VERSION 5.8 ;
BUSBITCHARS "[]" ;
DIVIDERCHAR "/" ;
UNITS
    DATABASE MICRONS 1000 ;
END UNITS

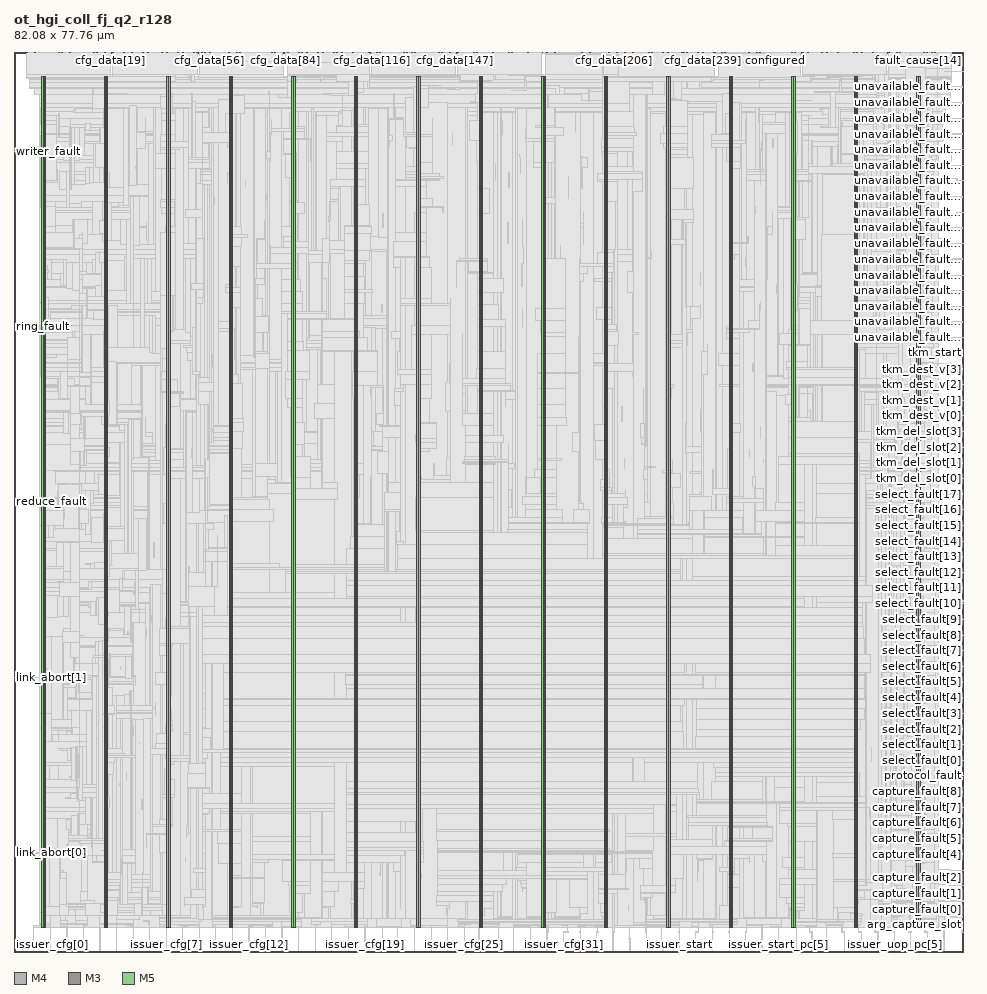
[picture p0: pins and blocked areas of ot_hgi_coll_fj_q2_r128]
MACRO ot_hgi_coll_fj_q2_r128
  FOREIGN ot_hgi_coll_fj_q2_r128 0 0 ;
  CLASS BLOCK ;
  SIZE 82.08 BY 77.76 ;
  PIN arg_capture_slot
    DIRECTION INPUT ;
    USE SIGNAL ;
    PORT
      LAYER M4 ;
        RECT  81.996 1.68 82.08 1.704 ;
    END
  END arg_capture_slot
  PIN capture_fault[0]
    DIRECTION INPUT ;
    USE SIGNAL ;
    PORT
      LAYER M4 ;
        RECT  81.996 3.024 82.08 3.048 ;
    END
  END capture_fault[0]
  PIN capture_fault[1]
    DIRECTION INPUT ;
    USE SIGNAL ;
    PORT
      LAYER M4 ;
        RECT  81.996 4.368 82.08 4.392 ;
    END
  END capture_fault[1]
  PIN capture_fault[2]
    DIRECTION INPUT ;
    USE SIGNAL ;
    PORT
      LAYER M4 ;
        RECT  81.996 5.712 82.08 5.736 ;
    END
  END capture_fault[2]
  PIN capture_fault[3]
    DIRECTION INPUT ;
    USE SIGNAL ;
    PORT
      LAYER M4 ;
        RECT  81.996 7.056 82.08 7.08 ;
    END
  END capture_fault[3]
  PIN capture_fault[4]
    DIRECTION INPUT ;
    USE SIGNAL ;
    PORT
      LAYER M4 ;
        RECT  81.996 8.448 82.08 8.472 ;
    END
  END capture_fault[4]
  PIN capture_fault[5]
    DIRECTION INPUT ;
    USE SIGNAL ;
    PORT
      LAYER M4 ;
        RECT  81.996 9.792 82.08 9.816 ;
    END
  END capture_fault[5]
  PIN capture_fault[6]
    DIRECTION INPUT ;
    USE SIGNAL ;
    PORT
      LAYER M4 ;
        RECT  81.996 11.136 82.08 11.16 ;
    END
  END capture_fault[6]
  PIN capture_fault[7]
    DIRECTION INPUT ;
    USE SIGNAL ;
    PORT
      LAYER M4 ;
        RECT  81.996 12.48 82.08 12.504 ;
    END
  END capture_fault[7]
  PIN capture_fault[8]
    DIRECTION INPUT ;
    USE SIGNAL ;
    PORT
      LAYER M4 ;
        RECT  81.996 13.824 82.08 13.848 ;
    END
  END capture_fault[8]
  PIN cfg_addr[0]
    DIRECTION INPUT ;
    USE SIGNAL ;
    PORT
      LAYER M3 ;
        RECT  1.116 77.722 1.134 77.76 ;
    END
  END cfg_addr[0]
  PIN cfg_addr[10]
    DIRECTION INPUT ;
    USE SIGNAL ;
    PORT
      LAYER M3 ;
        RECT  3.42 77.722 3.438 77.76 ;
    END
  END cfg_addr[10]
  PIN cfg_addr[11]
    DIRECTION INPUT ;
    USE SIGNAL ;
    PORT
      LAYER M3 ;
        RECT  3.672 77.722 3.69 77.76 ;
    END
  END cfg_addr[11]
  PIN cfg_addr[1]
    DIRECTION INPUT ;
    USE SIGNAL ;
    PORT
      LAYER M3 ;
        RECT  1.332 77.722 1.35 77.76 ;
    END
  END cfg_addr[1]
  PIN cfg_addr[2]
    DIRECTION INPUT ;
    USE SIGNAL ;
    PORT
      LAYER M3 ;
        RECT  1.584 77.722 1.602 77.76 ;
    END
  END cfg_addr[2]
  PIN cfg_addr[3]
    DIRECTION INPUT ;
    USE SIGNAL ;
    PORT
      LAYER M3 ;
        RECT  1.8 77.722 1.818 77.76 ;
    END
  END cfg_addr[3]
  PIN cfg_addr[4]
    DIRECTION INPUT ;
    USE SIGNAL ;
    PORT
      LAYER M3 ;
        RECT  2.052 77.722 2.07 77.76 ;
    END
  END cfg_addr[4]
  PIN cfg_addr[5]
    DIRECTION INPUT ;
    USE SIGNAL ;
    PORT
      LAYER M3 ;
        RECT  2.268 77.722 2.286 77.76 ;
    END
  END cfg_addr[5]
  PIN cfg_addr[6]
    DIRECTION INPUT ;
    USE SIGNAL ;
    PORT
      LAYER M3 ;
        RECT  2.52 77.722 2.538 77.76 ;
    END
  END cfg_addr[6]
  PIN cfg_addr[7]
    DIRECTION INPUT ;
    USE SIGNAL ;
    PORT
      LAYER M3 ;
        RECT  2.736 77.722 2.754 77.76 ;
    END
  END cfg_addr[7]
  PIN cfg_addr[8]
    DIRECTION INPUT ;
    USE SIGNAL ;
    PORT
      LAYER M3 ;
        RECT  2.988 77.722 3.006 77.76 ;
    END
  END cfg_addr[8]
  PIN cfg_addr[9]
    DIRECTION INPUT ;
    USE SIGNAL ;
    PORT
      LAYER M3 ;
        RECT  3.204 77.722 3.222 77.76 ;
    END
  END cfg_addr[9]
  PIN cfg_data[0]
    DIRECTION INPUT ;
    USE SIGNAL ;
    PORT
      LAYER M3 ;
        RECT  3.888 77.722 3.906 77.76 ;
    END
  END cfg_data[0]
  PIN cfg_data[100]
    DIRECTION INPUT ;
    USE SIGNAL ;
    PORT
      LAYER M5 ;
        RECT  27.168 77.676 27.192 77.76 ;
    END
  END cfg_data[100]
  PIN cfg_data[101]
    DIRECTION INPUT ;
    USE SIGNAL ;
    PORT
      LAYER M5 ;
        RECT  27.408 77.676 27.432 77.76 ;
    END
  END cfg_data[101]
  PIN cfg_data[102]
    DIRECTION INPUT ;
    USE SIGNAL ;
    PORT
      LAYER M5 ;
        RECT  27.648 77.676 27.672 77.76 ;
    END
  END cfg_data[102]
  PIN cfg_data[103]
    DIRECTION INPUT ;
    USE SIGNAL ;
    PORT
      LAYER M5 ;
        RECT  27.888 77.676 27.912 77.76 ;
    END
  END cfg_data[103]
  PIN cfg_data[104]
    DIRECTION INPUT ;
    USE SIGNAL ;
    PORT
      LAYER M5 ;
        RECT  28.128 77.676 28.152 77.76 ;
    END
  END cfg_data[104]
  PIN cfg_data[105]
    DIRECTION INPUT ;
    USE SIGNAL ;
    PORT
      LAYER M5 ;
        RECT  28.32 77.676 28.344 77.76 ;
    END
  END cfg_data[105]
  PIN cfg_data[106]
    DIRECTION INPUT ;
    USE SIGNAL ;
    PORT
      LAYER M5 ;
        RECT  28.56 77.676 28.584 77.76 ;
    END
  END cfg_data[106]
  PIN cfg_data[107]
    DIRECTION INPUT ;
    USE SIGNAL ;
    PORT
      LAYER M5 ;
        RECT  28.8 77.676 28.824 77.76 ;
    END
  END cfg_data[107]
  PIN cfg_data[108]
    DIRECTION INPUT ;
    USE SIGNAL ;
    PORT
      LAYER M5 ;
        RECT  29.04 77.676 29.064 77.76 ;
    END
  END cfg_data[108]
  PIN cfg_data[109]
    DIRECTION INPUT ;
    USE SIGNAL ;
    PORT
      LAYER M5 ;
        RECT  29.28 77.676 29.304 77.76 ;
    END
  END cfg_data[109]
  PIN cfg_data[10]
    DIRECTION INPUT ;
    USE SIGNAL ;
    PORT
      LAYER M3 ;
        RECT  6.228 77.722 6.246 77.76 ;
    END
  END cfg_data[10]
  PIN cfg_data[110]
    DIRECTION INPUT ;
    USE SIGNAL ;
    PORT
      LAYER M5 ;
        RECT  29.52 77.676 29.544 77.76 ;
    END
  END cfg_data[110]
  PIN cfg_data[111]
    DIRECTION INPUT ;
    USE SIGNAL ;
    PORT
      LAYER M5 ;
        RECT  29.76 77.676 29.784 77.76 ;
    END
  END cfg_data[111]
  PIN cfg_data[112]
    DIRECTION INPUT ;
    USE SIGNAL ;
    PORT
      LAYER M5 ;
        RECT  29.952 77.676 29.976 77.76 ;
    END
  END cfg_data[112]
  PIN cfg_data[113]
    DIRECTION INPUT ;
    USE SIGNAL ;
    PORT
      LAYER M5 ;
        RECT  30.192 77.676 30.216 77.76 ;
    END
  END cfg_data[113]
  PIN cfg_data[114]
    DIRECTION INPUT ;
    USE SIGNAL ;
    PORT
      LAYER M5 ;
        RECT  30.432 77.676 30.456 77.76 ;
    END
  END cfg_data[114]
  PIN cfg_data[115]
    DIRECTION INPUT ;
    USE SIGNAL ;
    PORT
      LAYER M5 ;
        RECT  30.672 77.676 30.696 77.76 ;
    END
  END cfg_data[115]
  PIN cfg_data[116]
    DIRECTION INPUT ;
    USE SIGNAL ;
    PORT
      LAYER M3 ;
        RECT  30.888 77.722 30.906 77.76 ;
    END
  END cfg_data[116]
  PIN cfg_data[117]
    DIRECTION INPUT ;
    USE SIGNAL ;
    PORT
      LAYER M3 ;
        RECT  31.14 77.722 31.158 77.76 ;
    END
  END cfg_data[117]
  PIN cfg_data[118]
    DIRECTION INPUT ;
    USE SIGNAL ;
    PORT
      LAYER M3 ;
        RECT  31.356 77.722 31.374 77.76 ;
    END
  END cfg_data[118]
  PIN cfg_data[119]
    DIRECTION INPUT ;
    USE SIGNAL ;
    PORT
      LAYER M3 ;
        RECT  31.608 77.722 31.626 77.76 ;
    END
  END cfg_data[119]
  PIN cfg_data[11]
    DIRECTION INPUT ;
    USE SIGNAL ;
    PORT
      LAYER M3 ;
        RECT  6.48 77.722 6.498 77.76 ;
    END
  END cfg_data[11]
  PIN cfg_data[120]
    DIRECTION INPUT ;
    USE SIGNAL ;
    PORT
      LAYER M3 ;
        RECT  31.824 77.722 31.842 77.76 ;
    END
  END cfg_data[120]
  PIN cfg_data[121]
    DIRECTION INPUT ;
    USE SIGNAL ;
    PORT
      LAYER M3 ;
        RECT  32.076 77.722 32.094 77.76 ;
    END
  END cfg_data[121]
  PIN cfg_data[122]
    DIRECTION INPUT ;
    USE SIGNAL ;
    PORT
      LAYER M3 ;
        RECT  32.292 77.722 32.31 77.76 ;
    END
  END cfg_data[122]
  PIN cfg_data[123]
    DIRECTION INPUT ;
    USE SIGNAL ;
    PORT
      LAYER M3 ;
        RECT  32.544 77.722 32.562 77.76 ;
    END
  END cfg_data[123]
  PIN cfg_data[124]
    DIRECTION INPUT ;
    USE SIGNAL ;
    PORT
      LAYER M3 ;
        RECT  32.76 77.722 32.778 77.76 ;
    END
  END cfg_data[124]
  PIN cfg_data[125]
    DIRECTION INPUT ;
    USE SIGNAL ;
    PORT
      LAYER M3 ;
        RECT  33.012 77.722 33.03 77.76 ;
    END
  END cfg_data[125]
  PIN cfg_data[126]
    DIRECTION INPUT ;
    USE SIGNAL ;
    PORT
      LAYER M3 ;
        RECT  33.228 77.722 33.246 77.76 ;
    END
  END cfg_data[126]
  PIN cfg_data[127]
    DIRECTION INPUT ;
    USE SIGNAL ;
    PORT
      LAYER M3 ;
        RECT  33.48 77.722 33.498 77.76 ;
    END
  END cfg_data[127]
  PIN cfg_data[128]
    DIRECTION INPUT ;
    USE SIGNAL ;
    PORT
      LAYER M3 ;
        RECT  33.696 77.722 33.714 77.76 ;
    END
  END cfg_data[128]
  PIN cfg_data[129]
    DIRECTION INPUT ;
    USE SIGNAL ;
    PORT
      LAYER M3 ;
        RECT  33.948 77.722 33.966 77.76 ;
    END
  END cfg_data[129]
  PIN cfg_data[12]
    DIRECTION INPUT ;
    USE SIGNAL ;
    PORT
      LAYER M3 ;
        RECT  6.696 77.722 6.714 77.76 ;
    END
  END cfg_data[12]
  PIN cfg_data[130]
    DIRECTION INPUT ;
    USE SIGNAL ;
    PORT
      LAYER M3 ;
        RECT  34.164 77.722 34.182 77.76 ;
    END
  END cfg_data[130]
  PIN cfg_data[131]
    DIRECTION INPUT ;
    USE SIGNAL ;
    PORT
      LAYER M3 ;
        RECT  34.38 77.722 34.398 77.76 ;
    END
  END cfg_data[131]
  PIN cfg_data[132]
    DIRECTION INPUT ;
    USE SIGNAL ;
    PORT
      LAYER M3 ;
        RECT  34.632 77.722 34.65 77.76 ;
    END
  END cfg_data[132]
  PIN cfg_data[133]
    DIRECTION INPUT ;
    USE SIGNAL ;
    PORT
      LAYER M3 ;
        RECT  34.848 77.722 34.866 77.76 ;
    END
  END cfg_data[133]
  PIN cfg_data[134]
    DIRECTION INPUT ;
    USE SIGNAL ;
    PORT
      LAYER M3 ;
        RECT  35.1 77.722 35.118 77.76 ;
    END
  END cfg_data[134]
  PIN cfg_data[135]
    DIRECTION INPUT ;
    USE SIGNAL ;
    PORT
      LAYER M3 ;
        RECT  35.316 77.722 35.334 77.76 ;
    END
  END cfg_data[135]
  PIN cfg_data[136]
    DIRECTION INPUT ;
    USE SIGNAL ;
    PORT
      LAYER M3 ;
        RECT  35.568 77.722 35.586 77.76 ;
    END
  END cfg_data[136]
  PIN cfg_data[137]
    DIRECTION INPUT ;
    USE SIGNAL ;
    PORT
      LAYER M3 ;
        RECT  35.784 77.722 35.802 77.76 ;
    END
  END cfg_data[137]
  PIN cfg_data[138]
    DIRECTION INPUT ;
    USE SIGNAL ;
    PORT
      LAYER M3 ;
        RECT  36.036 77.722 36.054 77.76 ;
    END
  END cfg_data[138]
  PIN cfg_data[139]
    DIRECTION INPUT ;
    USE SIGNAL ;
    PORT
      LAYER M3 ;
        RECT  36.252 77.722 36.27 77.76 ;
    END
  END cfg_data[139]
  PIN cfg_data[13]
    DIRECTION INPUT ;
    USE SIGNAL ;
    PORT
      LAYER M3 ;
        RECT  6.912 77.722 6.93 77.76 ;
    END
  END cfg_data[13]
  PIN cfg_data[140]
    DIRECTION INPUT ;
    USE SIGNAL ;
    PORT
      LAYER M3 ;
        RECT  36.504 77.722 36.522 77.76 ;
    END
  END cfg_data[140]
  PIN cfg_data[141]
    DIRECTION INPUT ;
    USE SIGNAL ;
    PORT
      LAYER M3 ;
        RECT  36.72 77.722 36.738 77.76 ;
    END
  END cfg_data[141]
  PIN cfg_data[142]
    DIRECTION INPUT ;
    USE SIGNAL ;
    PORT
      LAYER M3 ;
        RECT  36.972 77.722 36.99 77.76 ;
    END
  END cfg_data[142]
  PIN cfg_data[143]
    DIRECTION INPUT ;
    USE SIGNAL ;
    PORT
      LAYER M3 ;
        RECT  37.188 77.722 37.206 77.76 ;
    END
  END cfg_data[143]
  PIN cfg_data[144]
    DIRECTION INPUT ;
    USE SIGNAL ;
    PORT
      LAYER M3 ;
        RECT  37.44 77.722 37.458 77.76 ;
    END
  END cfg_data[144]
  PIN cfg_data[145]
    DIRECTION INPUT ;
    USE SIGNAL ;
    PORT
      LAYER M3 ;
        RECT  37.656 77.722 37.674 77.76 ;
    END
  END cfg_data[145]
  PIN cfg_data[146]
    DIRECTION INPUT ;
    USE SIGNAL ;
    PORT
      LAYER M3 ;
        RECT  37.872 77.722 37.89 77.76 ;
    END
  END cfg_data[146]
  PIN cfg_data[147]
    DIRECTION INPUT ;
    USE SIGNAL ;
    PORT
      LAYER M3 ;
        RECT  38.124 77.722 38.142 77.76 ;
    END
  END cfg_data[147]
  PIN cfg_data[148]
    DIRECTION INPUT ;
    USE SIGNAL ;
    PORT
      LAYER M5 ;
        RECT  38.352 77.676 38.376 77.76 ;
    END
  END cfg_data[148]
  PIN cfg_data[149]
    DIRECTION INPUT ;
    USE SIGNAL ;
    PORT
      LAYER M5 ;
        RECT  38.592 77.676 38.616 77.76 ;
    END
  END cfg_data[149]
  PIN cfg_data[14]
    DIRECTION INPUT ;
    USE SIGNAL ;
    PORT
      LAYER M3 ;
        RECT  7.164 77.722 7.182 77.76 ;
    END
  END cfg_data[14]
  PIN cfg_data[150]
    DIRECTION INPUT ;
    USE SIGNAL ;
    PORT
      LAYER M5 ;
        RECT  38.832 77.676 38.856 77.76 ;
    END
  END cfg_data[150]
  PIN cfg_data[151]
    DIRECTION INPUT ;
    USE SIGNAL ;
    PORT
      LAYER M5 ;
        RECT  39.072 77.676 39.096 77.76 ;
    END
  END cfg_data[151]
  PIN cfg_data[152]
    DIRECTION INPUT ;
    USE SIGNAL ;
    PORT
      LAYER M5 ;
        RECT  39.264 77.676 39.288 77.76 ;
    END
  END cfg_data[152]
  PIN cfg_data[153]
    DIRECTION INPUT ;
    USE SIGNAL ;
    PORT
      LAYER M5 ;
        RECT  39.504 77.676 39.528 77.76 ;
    END
  END cfg_data[153]
  PIN cfg_data[154]
    DIRECTION INPUT ;
    USE SIGNAL ;
    PORT
      LAYER M5 ;
        RECT  39.744 77.676 39.768 77.76 ;
    END
  END cfg_data[154]
  PIN cfg_data[155]
    DIRECTION INPUT ;
    USE SIGNAL ;
    PORT
      LAYER M5 ;
        RECT  39.984 77.676 40.008 77.76 ;
    END
  END cfg_data[155]
  PIN cfg_data[156]
    DIRECTION INPUT ;
    USE SIGNAL ;
    PORT
      LAYER M5 ;
        RECT  40.224 77.676 40.248 77.76 ;
    END
  END cfg_data[156]
  PIN cfg_data[157]
    DIRECTION INPUT ;
    USE SIGNAL ;
    PORT
      LAYER M5 ;
        RECT  40.464 77.676 40.488 77.76 ;
    END
  END cfg_data[157]
  PIN cfg_data[158]
    DIRECTION INPUT ;
    USE SIGNAL ;
    PORT
      LAYER M5 ;
        RECT  40.656 77.676 40.68 77.76 ;
    END
  END cfg_data[158]
  PIN cfg_data[159]
    DIRECTION INPUT ;
    USE SIGNAL ;
    PORT
      LAYER M5 ;
        RECT  40.896 77.676 40.92 77.76 ;
    END
  END cfg_data[159]
  PIN cfg_data[15]
    DIRECTION INPUT ;
    USE SIGNAL ;
    PORT
      LAYER M3 ;
        RECT  7.38 77.722 7.398 77.76 ;
    END
  END cfg_data[15]
  PIN cfg_data[160]
    DIRECTION INPUT ;
    USE SIGNAL ;
    PORT
      LAYER M5 ;
        RECT  41.136 77.676 41.16 77.76 ;
    END
  END cfg_data[160]
  PIN cfg_data[161]
    DIRECTION INPUT ;
    USE SIGNAL ;
    PORT
      LAYER M5 ;
        RECT  41.376 77.676 41.4 77.76 ;
    END
  END cfg_data[161]
  PIN cfg_data[162]
    DIRECTION INPUT ;
    USE SIGNAL ;
    PORT
      LAYER M5 ;
        RECT  41.616 77.676 41.64 77.76 ;
    END
  END cfg_data[162]
  PIN cfg_data[163]
    DIRECTION INPUT ;
    USE SIGNAL ;
    PORT
      LAYER M5 ;
        RECT  41.856 77.676 41.88 77.76 ;
    END
  END cfg_data[163]
  PIN cfg_data[164]
    DIRECTION INPUT ;
    USE SIGNAL ;
    PORT
      LAYER M5 ;
        RECT  42.096 77.676 42.12 77.76 ;
    END
  END cfg_data[164]
  PIN cfg_data[165]
    DIRECTION INPUT ;
    USE SIGNAL ;
    PORT
      LAYER M5 ;
        RECT  42.288 77.676 42.312 77.76 ;
    END
  END cfg_data[165]
  PIN cfg_data[166]
    DIRECTION INPUT ;
    USE SIGNAL ;
    PORT
      LAYER M5 ;
        RECT  42.528 77.676 42.552 77.76 ;
    END
  END cfg_data[166]
  PIN cfg_data[167]
    DIRECTION INPUT ;
    USE SIGNAL ;
    PORT
      LAYER M5 ;
        RECT  42.768 77.676 42.792 77.76 ;
    END
  END cfg_data[167]
  PIN cfg_data[168]
    DIRECTION INPUT ;
    USE SIGNAL ;
    PORT
      LAYER M5 ;
        RECT  43.008 77.676 43.032 77.76 ;
    END
  END cfg_data[168]
  PIN cfg_data[169]
    DIRECTION INPUT ;
    USE SIGNAL ;
    PORT
      LAYER M5 ;
        RECT  43.248 77.676 43.272 77.76 ;
    END
  END cfg_data[169]
  PIN cfg_data[16]
    DIRECTION INPUT ;
    USE SIGNAL ;
    PORT
      LAYER M3 ;
        RECT  7.632 77.722 7.65 77.76 ;
    END
  END cfg_data[16]
  PIN cfg_data[170]
    DIRECTION INPUT ;
    USE SIGNAL ;
    PORT
      LAYER M5 ;
        RECT  43.488 77.676 43.512 77.76 ;
    END
  END cfg_data[170]
  PIN cfg_data[171]
    DIRECTION INPUT ;
    USE SIGNAL ;
    PORT
      LAYER M5 ;
        RECT  43.728 77.676 43.752 77.76 ;
    END
  END cfg_data[171]
  PIN cfg_data[172]
    DIRECTION INPUT ;
    USE SIGNAL ;
    PORT
      LAYER M5 ;
        RECT  43.92 77.676 43.944 77.76 ;
    END
  END cfg_data[172]
  PIN cfg_data[173]
    DIRECTION INPUT ;
    USE SIGNAL ;
    PORT
      LAYER M5 ;
        RECT  44.16 77.676 44.184 77.76 ;
    END
  END cfg_data[173]
  PIN cfg_data[174]
    DIRECTION INPUT ;
    USE SIGNAL ;
    PORT
      LAYER M5 ;
        RECT  44.4 77.676 44.424 77.76 ;
    END
  END cfg_data[174]
  PIN cfg_data[175]
    DIRECTION INPUT ;
    USE SIGNAL ;
    PORT
      LAYER M5 ;
        RECT  44.64 77.676 44.664 77.76 ;
    END
  END cfg_data[175]
  PIN cfg_data[176]
    DIRECTION INPUT ;
    USE SIGNAL ;
    PORT
      LAYER M5 ;
        RECT  44.88 77.676 44.904 77.76 ;
    END
  END cfg_data[176]
  PIN cfg_data[177]
    DIRECTION INPUT ;
    USE SIGNAL ;
    PORT
      LAYER M5 ;
        RECT  45.12 77.676 45.144 77.76 ;
    END
  END cfg_data[177]
  PIN cfg_data[178]
    DIRECTION INPUT ;
    USE SIGNAL ;
    PORT
      LAYER M5 ;
        RECT  45.312 77.676 45.336 77.76 ;
    END
  END cfg_data[178]
  PIN cfg_data[179]
    DIRECTION INPUT ;
    USE SIGNAL ;
    PORT
      LAYER M5 ;
        RECT  45.552 77.676 45.576 77.76 ;
    END
  END cfg_data[179]
  PIN cfg_data[17]
    DIRECTION INPUT ;
    USE SIGNAL ;
    PORT
      LAYER M3 ;
        RECT  7.848 77.722 7.866 77.76 ;
    END
  END cfg_data[17]
  PIN cfg_data[180]
    DIRECTION INPUT ;
    USE SIGNAL ;
    PORT
      LAYER M3 ;
        RECT  45.792 77.722 45.81 77.76 ;
    END
  END cfg_data[180]
  PIN cfg_data[181]
    DIRECTION INPUT ;
    USE SIGNAL ;
    PORT
      LAYER M3 ;
        RECT  46.044 77.722 46.062 77.76 ;
    END
  END cfg_data[181]
  PIN cfg_data[182]
    DIRECTION INPUT ;
    USE SIGNAL ;
    PORT
      LAYER M3 ;
        RECT  46.26 77.722 46.278 77.76 ;
    END
  END cfg_data[182]
  PIN cfg_data[183]
    DIRECTION INPUT ;
    USE SIGNAL ;
    PORT
      LAYER M3 ;
        RECT  46.512 77.722 46.53 77.76 ;
    END
  END cfg_data[183]
  PIN cfg_data[184]
    DIRECTION INPUT ;
    USE SIGNAL ;
    PORT
      LAYER M3 ;
        RECT  46.728 77.722 46.746 77.76 ;
    END
  END cfg_data[184]
  PIN cfg_data[185]
    DIRECTION INPUT ;
    USE SIGNAL ;
    PORT
      LAYER M3 ;
        RECT  46.98 77.722 46.998 77.76 ;
    END
  END cfg_data[185]
  PIN cfg_data[186]
    DIRECTION INPUT ;
    USE SIGNAL ;
    PORT
      LAYER M3 ;
        RECT  47.196 77.722 47.214 77.76 ;
    END
  END cfg_data[186]
  PIN cfg_data[187]
    DIRECTION INPUT ;
    USE SIGNAL ;
    PORT
      LAYER M3 ;
        RECT  47.448 77.722 47.466 77.76 ;
    END
  END cfg_data[187]
  PIN cfg_data[188]
    DIRECTION INPUT ;
    USE SIGNAL ;
    PORT
      LAYER M3 ;
        RECT  47.664 77.722 47.682 77.76 ;
    END
  END cfg_data[188]
  PIN cfg_data[189]
    DIRECTION INPUT ;
    USE SIGNAL ;
    PORT
      LAYER M3 ;
        RECT  47.916 77.722 47.934 77.76 ;
    END
  END cfg_data[189]
  PIN cfg_data[18]
    DIRECTION INPUT ;
    USE SIGNAL ;
    PORT
      LAYER M3 ;
        RECT  8.1 77.722 8.118 77.76 ;
    END
  END cfg_data[18]
  PIN cfg_data[190]
    DIRECTION INPUT ;
    USE SIGNAL ;
    PORT
      LAYER M3 ;
        RECT  48.132 77.722 48.15 77.76 ;
    END
  END cfg_data[190]
  PIN cfg_data[191]
    DIRECTION INPUT ;
    USE SIGNAL ;
    PORT
      LAYER M3 ;
        RECT  48.348 77.722 48.366 77.76 ;
    END
  END cfg_data[191]
  PIN cfg_data[192]
    DIRECTION INPUT ;
    USE SIGNAL ;
    PORT
      LAYER M3 ;
        RECT  48.6 77.722 48.618 77.76 ;
    END
  END cfg_data[192]
  PIN cfg_data[193]
    DIRECTION INPUT ;
    USE SIGNAL ;
    PORT
      LAYER M3 ;
        RECT  48.816 77.722 48.834 77.76 ;
    END
  END cfg_data[193]
  PIN cfg_data[194]
    DIRECTION INPUT ;
    USE SIGNAL ;
    PORT
      LAYER M3 ;
        RECT  49.068 77.722 49.086 77.76 ;
    END
  END cfg_data[194]
  PIN cfg_data[195]
    DIRECTION INPUT ;
    USE SIGNAL ;
    PORT
      LAYER M3 ;
        RECT  49.284 77.722 49.302 77.76 ;
    END
  END cfg_data[195]
  PIN cfg_data[196]
    DIRECTION INPUT ;
    USE SIGNAL ;
    PORT
      LAYER M3 ;
        RECT  49.536 77.722 49.554 77.76 ;
    END
  END cfg_data[196]
  PIN cfg_data[197]
    DIRECTION INPUT ;
    USE SIGNAL ;
    PORT
      LAYER M3 ;
        RECT  49.752 77.722 49.77 77.76 ;
    END
  END cfg_data[197]
  PIN cfg_data[198]
    DIRECTION INPUT ;
    USE SIGNAL ;
    PORT
      LAYER M3 ;
        RECT  50.004 77.722 50.022 77.76 ;
    END
  END cfg_data[198]
  PIN cfg_data[199]
    DIRECTION INPUT ;
    USE SIGNAL ;
    PORT
      LAYER M3 ;
        RECT  50.22 77.722 50.238 77.76 ;
    END
  END cfg_data[199]
  PIN cfg_data[19]
    DIRECTION INPUT ;
    USE SIGNAL ;
    PORT
      LAYER M3 ;
        RECT  8.316 77.722 8.334 77.76 ;
    END
  END cfg_data[19]
  PIN cfg_data[1]
    DIRECTION INPUT ;
    USE SIGNAL ;
    PORT
      LAYER M3 ;
        RECT  4.14 77.722 4.158 77.76 ;
    END
  END cfg_data[1]
  PIN cfg_data[200]
    DIRECTION INPUT ;
    USE SIGNAL ;
    PORT
      LAYER M3 ;
        RECT  50.472 77.722 50.49 77.76 ;
    END
  END cfg_data[200]
  PIN cfg_data[201]
    DIRECTION INPUT ;
    USE SIGNAL ;
    PORT
      LAYER M3 ;
        RECT  50.688 77.722 50.706 77.76 ;
    END
  END cfg_data[201]
  PIN cfg_data[202]
    DIRECTION INPUT ;
    USE SIGNAL ;
    PORT
      LAYER M3 ;
        RECT  50.94 77.722 50.958 77.76 ;
    END
  END cfg_data[202]
  PIN cfg_data[203]
    DIRECTION INPUT ;
    USE SIGNAL ;
    PORT
      LAYER M3 ;
        RECT  51.156 77.722 51.174 77.76 ;
    END
  END cfg_data[203]
  PIN cfg_data[204]
    DIRECTION INPUT ;
    USE SIGNAL ;
    PORT
      LAYER M3 ;
        RECT  51.408 77.722 51.426 77.76 ;
    END
  END cfg_data[204]
  PIN cfg_data[205]
    DIRECTION INPUT ;
    USE SIGNAL ;
    PORT
      LAYER M3 ;
        RECT  51.624 77.722 51.642 77.76 ;
    END
  END cfg_data[205]
  PIN cfg_data[206]
    DIRECTION INPUT ;
    USE SIGNAL ;
    PORT
      LAYER M3 ;
        RECT  51.84 77.722 51.858 77.76 ;
    END
  END cfg_data[206]
  PIN cfg_data[207]
    DIRECTION INPUT ;
    USE SIGNAL ;
    PORT
      LAYER M3 ;
        RECT  52.092 77.722 52.11 77.76 ;
    END
  END cfg_data[207]
  PIN cfg_data[208]
    DIRECTION INPUT ;
    USE SIGNAL ;
    PORT
      LAYER M3 ;
        RECT  52.308 77.722 52.326 77.76 ;
    END
  END cfg_data[208]
  PIN cfg_data[209]
    DIRECTION INPUT ;
    USE SIGNAL ;
    PORT
      LAYER M3 ;
        RECT  52.56 77.722 52.578 77.76 ;
    END
  END cfg_data[209]
  PIN cfg_data[20]
    DIRECTION INPUT ;
    USE SIGNAL ;
    PORT
      LAYER M5 ;
        RECT  8.544 77.676 8.568 77.76 ;
    END
  END cfg_data[20]
  PIN cfg_data[210]
    DIRECTION INPUT ;
    USE SIGNAL ;
    PORT
      LAYER M3 ;
        RECT  52.776 77.722 52.794 77.76 ;
    END
  END cfg_data[210]
  PIN cfg_data[211]
    DIRECTION INPUT ;
    USE SIGNAL ;
    PORT
      LAYER M3 ;
        RECT  53.028 77.722 53.046 77.76 ;
    END
  END cfg_data[211]
  PIN cfg_data[212]
    DIRECTION INPUT ;
    USE SIGNAL ;
    PORT
      LAYER M5 ;
        RECT  53.232 77.676 53.256 77.76 ;
    END
  END cfg_data[212]
  PIN cfg_data[213]
    DIRECTION INPUT ;
    USE SIGNAL ;
    PORT
      LAYER M5 ;
        RECT  53.472 77.676 53.496 77.76 ;
    END
  END cfg_data[213]
  PIN cfg_data[214]
    DIRECTION INPUT ;
    USE SIGNAL ;
    PORT
      LAYER M5 ;
        RECT  53.712 77.676 53.736 77.76 ;
    END
  END cfg_data[214]
  PIN cfg_data[215]
    DIRECTION INPUT ;
    USE SIGNAL ;
    PORT
      LAYER M5 ;
        RECT  53.952 77.676 53.976 77.76 ;
    END
  END cfg_data[215]
  PIN cfg_data[216]
    DIRECTION INPUT ;
    USE SIGNAL ;
    PORT
      LAYER M5 ;
        RECT  54.192 77.676 54.216 77.76 ;
    END
  END cfg_data[216]
  PIN cfg_data[217]
    DIRECTION INPUT ;
    USE SIGNAL ;
    PORT
      LAYER M5 ;
        RECT  54.432 77.676 54.456 77.76 ;
    END
  END cfg_data[217]
  PIN cfg_data[218]
    DIRECTION INPUT ;
    USE SIGNAL ;
    PORT
      LAYER M5 ;
        RECT  54.624 77.676 54.648 77.76 ;
    END
  END cfg_data[218]
  PIN cfg_data[219]
    DIRECTION INPUT ;
    USE SIGNAL ;
    PORT
      LAYER M5 ;
        RECT  54.864 77.676 54.888 77.76 ;
    END
  END cfg_data[219]
  PIN cfg_data[21]
    DIRECTION INPUT ;
    USE SIGNAL ;
    PORT
      LAYER M5 ;
        RECT  8.784 77.676 8.808 77.76 ;
    END
  END cfg_data[21]
  PIN cfg_data[220]
    DIRECTION INPUT ;
    USE SIGNAL ;
    PORT
      LAYER M5 ;
        RECT  55.104 77.676 55.128 77.76 ;
    END
  END cfg_data[220]
  PIN cfg_data[221]
    DIRECTION INPUT ;
    USE SIGNAL ;
    PORT
      LAYER M5 ;
        RECT  55.344 77.676 55.368 77.76 ;
    END
  END cfg_data[221]
  PIN cfg_data[222]
    DIRECTION INPUT ;
    USE SIGNAL ;
    PORT
      LAYER M5 ;
        RECT  55.584 77.676 55.608 77.76 ;
    END
  END cfg_data[222]
  PIN cfg_data[223]
    DIRECTION INPUT ;
    USE SIGNAL ;
    PORT
      LAYER M5 ;
        RECT  55.824 77.676 55.848 77.76 ;
    END
  END cfg_data[223]
  PIN cfg_data[224]
    DIRECTION INPUT ;
    USE SIGNAL ;
    PORT
      LAYER M5 ;
        RECT  56.064 77.676 56.088 77.76 ;
    END
  END cfg_data[224]
  PIN cfg_data[225]
    DIRECTION INPUT ;
    USE SIGNAL ;
    PORT
      LAYER M5 ;
        RECT  56.256 77.676 56.28 77.76 ;
    END
  END cfg_data[225]
  PIN cfg_data[226]
    DIRECTION INPUT ;
    USE SIGNAL ;
    PORT
      LAYER M5 ;
        RECT  56.496 77.676 56.52 77.76 ;
    END
  END cfg_data[226]
  PIN cfg_data[227]
    DIRECTION INPUT ;
    USE SIGNAL ;
    PORT
      LAYER M5 ;
        RECT  56.736 77.676 56.76 77.76 ;
    END
  END cfg_data[227]
  PIN cfg_data[228]
    DIRECTION INPUT ;
    USE SIGNAL ;
    PORT
      LAYER M5 ;
        RECT  56.976 77.676 57 77.76 ;
    END
  END cfg_data[228]
  PIN cfg_data[229]
    DIRECTION INPUT ;
    USE SIGNAL ;
    PORT
      LAYER M5 ;
        RECT  57.216 77.676 57.24 77.76 ;
    END
  END cfg_data[229]
  PIN cfg_data[22]
    DIRECTION INPUT ;
    USE SIGNAL ;
    PORT
      LAYER M5 ;
        RECT  9.024 77.676 9.048 77.76 ;
    END
  END cfg_data[22]
  PIN cfg_data[230]
    DIRECTION INPUT ;
    USE SIGNAL ;
    PORT
      LAYER M5 ;
        RECT  57.456 77.676 57.48 77.76 ;
    END
  END cfg_data[230]
  PIN cfg_data[231]
    DIRECTION INPUT ;
    USE SIGNAL ;
    PORT
      LAYER M5 ;
        RECT  57.696 77.676 57.72 77.76 ;
    END
  END cfg_data[231]
  PIN cfg_data[232]
    DIRECTION INPUT ;
    USE SIGNAL ;
    PORT
      LAYER M5 ;
        RECT  57.888 77.676 57.912 77.76 ;
    END
  END cfg_data[232]
  PIN cfg_data[233]
    DIRECTION INPUT ;
    USE SIGNAL ;
    PORT
      LAYER M5 ;
        RECT  58.128 77.676 58.152 77.76 ;
    END
  END cfg_data[233]
  PIN cfg_data[234]
    DIRECTION INPUT ;
    USE SIGNAL ;
    PORT
      LAYER M5 ;
        RECT  58.368 77.676 58.392 77.76 ;
    END
  END cfg_data[234]
  PIN cfg_data[235]
    DIRECTION INPUT ;
    USE SIGNAL ;
    PORT
      LAYER M5 ;
        RECT  58.608 77.676 58.632 77.76 ;
    END
  END cfg_data[235]
  PIN cfg_data[236]
    DIRECTION INPUT ;
    USE SIGNAL ;
    PORT
      LAYER M5 ;
        RECT  58.848 77.676 58.872 77.76 ;
    END
  END cfg_data[236]
  PIN cfg_data[237]
    DIRECTION INPUT ;
    USE SIGNAL ;
    PORT
      LAYER M5 ;
        RECT  59.088 77.676 59.112 77.76 ;
    END
  END cfg_data[237]
  PIN cfg_data[238]
    DIRECTION INPUT ;
    USE SIGNAL ;
    PORT
      LAYER M5 ;
        RECT  59.28 77.676 59.304 77.76 ;
    END
  END cfg_data[238]
  PIN cfg_data[239]
    DIRECTION INPUT ;
    USE SIGNAL ;
    PORT
      LAYER M5 ;
        RECT  59.52 77.676 59.544 77.76 ;
    END
  END cfg_data[239]
  PIN cfg_data[23]
    DIRECTION INPUT ;
    USE SIGNAL ;
    PORT
      LAYER M5 ;
        RECT  9.264 77.676 9.288 77.76 ;
    END
  END cfg_data[23]
  PIN cfg_data[240]
    DIRECTION INPUT ;
    USE SIGNAL ;
    PORT
      LAYER M5 ;
        RECT  59.76 77.676 59.784 77.76 ;
    END
  END cfg_data[240]
  PIN cfg_data[241]
    DIRECTION INPUT ;
    USE SIGNAL ;
    PORT
      LAYER M5 ;
        RECT  60 77.676 60.024 77.76 ;
    END
  END cfg_data[241]
  PIN cfg_data[242]
    DIRECTION INPUT ;
    USE SIGNAL ;
    PORT
      LAYER M5 ;
        RECT  60.24 77.676 60.264 77.76 ;
    END
  END cfg_data[242]
  PIN cfg_data[243]
    DIRECTION INPUT ;
    USE SIGNAL ;
    PORT
      LAYER M5 ;
        RECT  60.48 77.676 60.504 77.76 ;
    END
  END cfg_data[243]
  PIN cfg_data[244]
    DIRECTION INPUT ;
    USE SIGNAL ;
    PORT
      LAYER M3 ;
        RECT  60.696 77.722 60.714 77.76 ;
    END
  END cfg_data[244]
  PIN cfg_data[245]
    DIRECTION INPUT ;
    USE SIGNAL ;
    PORT
      LAYER M3 ;
        RECT  60.948 77.722 60.966 77.76 ;
    END
  END cfg_data[245]
  PIN cfg_data[246]
    DIRECTION INPUT ;
    USE SIGNAL ;
    PORT
      LAYER M3 ;
        RECT  61.164 77.722 61.182 77.76 ;
    END
  END cfg_data[246]
  PIN cfg_data[247]
    DIRECTION INPUT ;
    USE SIGNAL ;
    PORT
      LAYER M3 ;
        RECT  61.416 77.722 61.434 77.76 ;
    END
  END cfg_data[247]
  PIN cfg_data[248]
    DIRECTION INPUT ;
    USE SIGNAL ;
    PORT
      LAYER M3 ;
        RECT  61.632 77.722 61.65 77.76 ;
    END
  END cfg_data[248]
  PIN cfg_data[249]
    DIRECTION INPUT ;
    USE SIGNAL ;
    PORT
      LAYER M3 ;
        RECT  61.884 77.722 61.902 77.76 ;
    END
  END cfg_data[249]
  PIN cfg_data[24]
    DIRECTION INPUT ;
    USE SIGNAL ;
    PORT
      LAYER M5 ;
        RECT  9.504 77.676 9.528 77.76 ;
    END
  END cfg_data[24]
  PIN cfg_data[250]
    DIRECTION INPUT ;
    USE SIGNAL ;
    PORT
      LAYER M3 ;
        RECT  62.1 77.722 62.118 77.76 ;
    END
  END cfg_data[250]
  PIN cfg_data[251]
    DIRECTION INPUT ;
    USE SIGNAL ;
    PORT
      LAYER M3 ;
        RECT  62.316 77.722 62.334 77.76 ;
    END
  END cfg_data[251]
  PIN cfg_data[252]
    DIRECTION INPUT ;
    USE SIGNAL ;
    PORT
      LAYER M3 ;
        RECT  62.568 77.722 62.586 77.76 ;
    END
  END cfg_data[252]
  PIN cfg_data[253]
    DIRECTION INPUT ;
    USE SIGNAL ;
    PORT
      LAYER M3 ;
        RECT  62.784 77.722 62.802 77.76 ;
    END
  END cfg_data[253]
  PIN cfg_data[254]
    DIRECTION INPUT ;
    USE SIGNAL ;
    PORT
      LAYER M3 ;
        RECT  63.036 77.722 63.054 77.76 ;
    END
  END cfg_data[254]
  PIN cfg_data[255]
    DIRECTION INPUT ;
    USE SIGNAL ;
    PORT
      LAYER M3 ;
        RECT  63.252 77.722 63.27 77.76 ;
    END
  END cfg_data[255]
  PIN cfg_data[25]
    DIRECTION INPUT ;
    USE SIGNAL ;
    PORT
      LAYER M5 ;
        RECT  9.696 77.676 9.72 77.76 ;
    END
  END cfg_data[25]
  PIN cfg_data[26]
    DIRECTION INPUT ;
    USE SIGNAL ;
    PORT
      LAYER M5 ;
        RECT  9.936 77.676 9.96 77.76 ;
    END
  END cfg_data[26]
  PIN cfg_data[27]
    DIRECTION INPUT ;
    USE SIGNAL ;
    PORT
      LAYER M5 ;
        RECT  10.176 77.676 10.2 77.76 ;
    END
  END cfg_data[27]
  PIN cfg_data[28]
    DIRECTION INPUT ;
    USE SIGNAL ;
    PORT
      LAYER M5 ;
        RECT  10.416 77.676 10.44 77.76 ;
    END
  END cfg_data[28]
  PIN cfg_data[29]
    DIRECTION INPUT ;
    USE SIGNAL ;
    PORT
      LAYER M5 ;
        RECT  10.656 77.676 10.68 77.76 ;
    END
  END cfg_data[29]
  PIN cfg_data[2]
    DIRECTION INPUT ;
    USE SIGNAL ;
    PORT
      LAYER M3 ;
        RECT  4.356 77.722 4.374 77.76 ;
    END
  END cfg_data[2]
  PIN cfg_data[30]
    DIRECTION INPUT ;
    USE SIGNAL ;
    PORT
      LAYER M5 ;
        RECT  10.896 77.676 10.92 77.76 ;
    END
  END cfg_data[30]
  PIN cfg_data[31]
    DIRECTION INPUT ;
    USE SIGNAL ;
    PORT
      LAYER M5 ;
        RECT  11.136 77.676 11.16 77.76 ;
    END
  END cfg_data[31]
  PIN cfg_data[32]
    DIRECTION INPUT ;
    USE SIGNAL ;
    PORT
      LAYER M5 ;
        RECT  11.328 77.676 11.352 77.76 ;
    END
  END cfg_data[32]
  PIN cfg_data[33]
    DIRECTION INPUT ;
    USE SIGNAL ;
    PORT
      LAYER M5 ;
        RECT  11.568 77.676 11.592 77.76 ;
    END
  END cfg_data[33]
  PIN cfg_data[34]
    DIRECTION INPUT ;
    USE SIGNAL ;
    PORT
      LAYER M5 ;
        RECT  11.808 77.676 11.832 77.76 ;
    END
  END cfg_data[34]
  PIN cfg_data[35]
    DIRECTION INPUT ;
    USE SIGNAL ;
    PORT
      LAYER M5 ;
        RECT  12.048 77.676 12.072 77.76 ;
    END
  END cfg_data[35]
  PIN cfg_data[36]
    DIRECTION INPUT ;
    USE SIGNAL ;
    PORT
      LAYER M5 ;
        RECT  12.288 77.676 12.312 77.76 ;
    END
  END cfg_data[36]
  PIN cfg_data[37]
    DIRECTION INPUT ;
    USE SIGNAL ;
    PORT
      LAYER M5 ;
        RECT  12.528 77.676 12.552 77.76 ;
    END
  END cfg_data[37]
  PIN cfg_data[38]
    DIRECTION INPUT ;
    USE SIGNAL ;
    PORT
      LAYER M5 ;
        RECT  12.768 77.676 12.792 77.76 ;
    END
  END cfg_data[38]
  PIN cfg_data[39]
    DIRECTION INPUT ;
    USE SIGNAL ;
    PORT
      LAYER M5 ;
        RECT  12.96 77.676 12.984 77.76 ;
    END
  END cfg_data[39]
  PIN cfg_data[3]
    DIRECTION INPUT ;
    USE SIGNAL ;
    PORT
      LAYER M3 ;
        RECT  4.608 77.722 4.626 77.76 ;
    END
  END cfg_data[3]
  PIN cfg_data[40]
    DIRECTION INPUT ;
    USE SIGNAL ;
    PORT
      LAYER M5 ;
        RECT  13.2 77.676 13.224 77.76 ;
    END
  END cfg_data[40]
  PIN cfg_data[41]
    DIRECTION INPUT ;
    USE SIGNAL ;
    PORT
      LAYER M5 ;
        RECT  13.44 77.676 13.464 77.76 ;
    END
  END cfg_data[41]
  PIN cfg_data[42]
    DIRECTION INPUT ;
    USE SIGNAL ;
    PORT
      LAYER M5 ;
        RECT  13.68 77.676 13.704 77.76 ;
    END
  END cfg_data[42]
  PIN cfg_data[43]
    DIRECTION INPUT ;
    USE SIGNAL ;
    PORT
      LAYER M5 ;
        RECT  13.92 77.676 13.944 77.76 ;
    END
  END cfg_data[43]
  PIN cfg_data[44]
    DIRECTION INPUT ;
    USE SIGNAL ;
    PORT
      LAYER M5 ;
        RECT  14.16 77.676 14.184 77.76 ;
    END
  END cfg_data[44]
  PIN cfg_data[45]
    DIRECTION INPUT ;
    USE SIGNAL ;
    PORT
      LAYER M5 ;
        RECT  14.352 77.676 14.376 77.76 ;
    END
  END cfg_data[45]
  PIN cfg_data[46]
    DIRECTION INPUT ;
    USE SIGNAL ;
    PORT
      LAYER M5 ;
        RECT  14.592 77.676 14.616 77.76 ;
    END
  END cfg_data[46]
  PIN cfg_data[47]
    DIRECTION INPUT ;
    USE SIGNAL ;
    PORT
      LAYER M5 ;
        RECT  14.832 77.676 14.856 77.76 ;
    END
  END cfg_data[47]
  PIN cfg_data[48]
    DIRECTION INPUT ;
    USE SIGNAL ;
    PORT
      LAYER M5 ;
        RECT  15.072 77.676 15.096 77.76 ;
    END
  END cfg_data[48]
  PIN cfg_data[49]
    DIRECTION INPUT ;
    USE SIGNAL ;
    PORT
      LAYER M5 ;
        RECT  15.312 77.676 15.336 77.76 ;
    END
  END cfg_data[49]
  PIN cfg_data[4]
    DIRECTION INPUT ;
    USE SIGNAL ;
    PORT
      LAYER M3 ;
        RECT  4.824 77.722 4.842 77.76 ;
    END
  END cfg_data[4]
  PIN cfg_data[50]
    DIRECTION INPUT ;
    USE SIGNAL ;
    PORT
      LAYER M5 ;
        RECT  15.552 77.676 15.576 77.76 ;
    END
  END cfg_data[50]
  PIN cfg_data[51]
    DIRECTION INPUT ;
    USE SIGNAL ;
    PORT
      LAYER M5 ;
        RECT  15.792 77.676 15.816 77.76 ;
    END
  END cfg_data[51]
  PIN cfg_data[52]
    DIRECTION INPUT ;
    USE SIGNAL ;
    PORT
      LAYER M3 ;
        RECT  16.02 77.722 16.038 77.76 ;
    END
  END cfg_data[52]
  PIN cfg_data[53]
    DIRECTION INPUT ;
    USE SIGNAL ;
    PORT
      LAYER M3 ;
        RECT  16.236 77.722 16.254 77.76 ;
    END
  END cfg_data[53]
  PIN cfg_data[54]
    DIRECTION INPUT ;
    USE SIGNAL ;
    PORT
      LAYER M3 ;
        RECT  16.488 77.722 16.506 77.76 ;
    END
  END cfg_data[54]
  PIN cfg_data[55]
    DIRECTION INPUT ;
    USE SIGNAL ;
    PORT
      LAYER M3 ;
        RECT  16.704 77.722 16.722 77.76 ;
    END
  END cfg_data[55]
  PIN cfg_data[56]
    DIRECTION INPUT ;
    USE SIGNAL ;
    PORT
      LAYER M3 ;
        RECT  16.92 77.722 16.938 77.76 ;
    END
  END cfg_data[56]
  PIN cfg_data[57]
    DIRECTION INPUT ;
    USE SIGNAL ;
    PORT
      LAYER M3 ;
        RECT  17.172 77.722 17.19 77.76 ;
    END
  END cfg_data[57]
  PIN cfg_data[58]
    DIRECTION INPUT ;
    USE SIGNAL ;
    PORT
      LAYER M3 ;
        RECT  17.388 77.722 17.406 77.76 ;
    END
  END cfg_data[58]
  PIN cfg_data[59]
    DIRECTION INPUT ;
    USE SIGNAL ;
    PORT
      LAYER M3 ;
        RECT  17.64 77.722 17.658 77.76 ;
    END
  END cfg_data[59]
  PIN cfg_data[5]
    DIRECTION INPUT ;
    USE SIGNAL ;
    PORT
      LAYER M3 ;
        RECT  5.076 77.722 5.094 77.76 ;
    END
  END cfg_data[5]
  PIN cfg_data[60]
    DIRECTION INPUT ;
    USE SIGNAL ;
    PORT
      LAYER M3 ;
        RECT  17.856 77.722 17.874 77.76 ;
    END
  END cfg_data[60]
  PIN cfg_data[61]
    DIRECTION INPUT ;
    USE SIGNAL ;
    PORT
      LAYER M3 ;
        RECT  18.108 77.722 18.126 77.76 ;
    END
  END cfg_data[61]
  PIN cfg_data[62]
    DIRECTION INPUT ;
    USE SIGNAL ;
    PORT
      LAYER M3 ;
        RECT  18.324 77.722 18.342 77.76 ;
    END
  END cfg_data[62]
  PIN cfg_data[63]
    DIRECTION INPUT ;
    USE SIGNAL ;
    PORT
      LAYER M3 ;
        RECT  18.576 77.722 18.594 77.76 ;
    END
  END cfg_data[63]
  PIN cfg_data[64]
    DIRECTION INPUT ;
    USE SIGNAL ;
    PORT
      LAYER M3 ;
        RECT  18.792 77.722 18.81 77.76 ;
    END
  END cfg_data[64]
  PIN cfg_data[65]
    DIRECTION INPUT ;
    USE SIGNAL ;
    PORT
      LAYER M3 ;
        RECT  19.044 77.722 19.062 77.76 ;
    END
  END cfg_data[65]
  PIN cfg_data[66]
    DIRECTION INPUT ;
    USE SIGNAL ;
    PORT
      LAYER M3 ;
        RECT  19.26 77.722 19.278 77.76 ;
    END
  END cfg_data[66]
  PIN cfg_data[67]
    DIRECTION INPUT ;
    USE SIGNAL ;
    PORT
      LAYER M3 ;
        RECT  19.512 77.722 19.53 77.76 ;
    END
  END cfg_data[67]
  PIN cfg_data[68]
    DIRECTION INPUT ;
    USE SIGNAL ;
    PORT
      LAYER M3 ;
        RECT  19.728 77.722 19.746 77.76 ;
    END
  END cfg_data[68]
  PIN cfg_data[69]
    DIRECTION INPUT ;
    USE SIGNAL ;
    PORT
      LAYER M3 ;
        RECT  19.98 77.722 19.998 77.76 ;
    END
  END cfg_data[69]
  PIN cfg_data[6]
    DIRECTION INPUT ;
    USE SIGNAL ;
    PORT
      LAYER M3 ;
        RECT  5.292 77.722 5.31 77.76 ;
    END
  END cfg_data[6]
  PIN cfg_data[70]
    DIRECTION INPUT ;
    USE SIGNAL ;
    PORT
      LAYER M3 ;
        RECT  20.196 77.722 20.214 77.76 ;
    END
  END cfg_data[70]
  PIN cfg_data[71]
    DIRECTION INPUT ;
    USE SIGNAL ;
    PORT
      LAYER M3 ;
        RECT  20.412 77.722 20.43 77.76 ;
    END
  END cfg_data[71]
  PIN cfg_data[72]
    DIRECTION INPUT ;
    USE SIGNAL ;
    PORT
      LAYER M3 ;
        RECT  20.664 77.722 20.682 77.76 ;
    END
  END cfg_data[72]
  PIN cfg_data[73]
    DIRECTION INPUT ;
    USE SIGNAL ;
    PORT
      LAYER M3 ;
        RECT  20.88 77.722 20.898 77.76 ;
    END
  END cfg_data[73]
  PIN cfg_data[74]
    DIRECTION INPUT ;
    USE SIGNAL ;
    PORT
      LAYER M3 ;
        RECT  21.132 77.722 21.15 77.76 ;
    END
  END cfg_data[74]
  PIN cfg_data[75]
    DIRECTION INPUT ;
    USE SIGNAL ;
    PORT
      LAYER M3 ;
        RECT  21.348 77.722 21.366 77.76 ;
    END
  END cfg_data[75]
  PIN cfg_data[76]
    DIRECTION INPUT ;
    USE SIGNAL ;
    PORT
      LAYER M3 ;
        RECT  21.6 77.722 21.618 77.76 ;
    END
  END cfg_data[76]
  PIN cfg_data[77]
    DIRECTION INPUT ;
    USE SIGNAL ;
    PORT
      LAYER M3 ;
        RECT  21.816 77.722 21.834 77.76 ;
    END
  END cfg_data[77]
  PIN cfg_data[78]
    DIRECTION INPUT ;
    USE SIGNAL ;
    PORT
      LAYER M3 ;
        RECT  22.068 77.722 22.086 77.76 ;
    END
  END cfg_data[78]
  PIN cfg_data[79]
    DIRECTION INPUT ;
    USE SIGNAL ;
    PORT
      LAYER M3 ;
        RECT  22.284 77.722 22.302 77.76 ;
    END
  END cfg_data[79]
  PIN cfg_data[7]
    DIRECTION INPUT ;
    USE SIGNAL ;
    PORT
      LAYER M3 ;
        RECT  5.544 77.722 5.562 77.76 ;
    END
  END cfg_data[7]
  PIN cfg_data[80]
    DIRECTION INPUT ;
    USE SIGNAL ;
    PORT
      LAYER M3 ;
        RECT  22.536 77.722 22.554 77.76 ;
    END
  END cfg_data[80]
  PIN cfg_data[81]
    DIRECTION INPUT ;
    USE SIGNAL ;
    PORT
      LAYER M3 ;
        RECT  22.752 77.722 22.77 77.76 ;
    END
  END cfg_data[81]
  PIN cfg_data[82]
    DIRECTION INPUT ;
    USE SIGNAL ;
    PORT
      LAYER M3 ;
        RECT  23.004 77.722 23.022 77.76 ;
    END
  END cfg_data[82]
  PIN cfg_data[83]
    DIRECTION INPUT ;
    USE SIGNAL ;
    PORT
      LAYER M3 ;
        RECT  23.22 77.722 23.238 77.76 ;
    END
  END cfg_data[83]
  PIN cfg_data[84]
    DIRECTION INPUT ;
    USE SIGNAL ;
    PORT
      LAYER M5 ;
        RECT  23.472 77.676 23.496 77.76 ;
    END
  END cfg_data[84]
  PIN cfg_data[85]
    DIRECTION INPUT ;
    USE SIGNAL ;
    PORT
      LAYER M5 ;
        RECT  23.664 77.676 23.688 77.76 ;
    END
  END cfg_data[85]
  PIN cfg_data[86]
    DIRECTION INPUT ;
    USE SIGNAL ;
    PORT
      LAYER M5 ;
        RECT  23.904 77.676 23.928 77.76 ;
    END
  END cfg_data[86]
  PIN cfg_data[87]
    DIRECTION INPUT ;
    USE SIGNAL ;
    PORT
      LAYER M5 ;
        RECT  24.144 77.676 24.168 77.76 ;
    END
  END cfg_data[87]
  PIN cfg_data[88]
    DIRECTION INPUT ;
    USE SIGNAL ;
    PORT
      LAYER M5 ;
        RECT  24.384 77.676 24.408 77.76 ;
    END
  END cfg_data[88]
  PIN cfg_data[89]
    DIRECTION INPUT ;
    USE SIGNAL ;
    PORT
      LAYER M5 ;
        RECT  24.624 77.676 24.648 77.76 ;
    END
  END cfg_data[89]
  PIN cfg_data[8]
    DIRECTION INPUT ;
    USE SIGNAL ;
    PORT
      LAYER M3 ;
        RECT  5.76 77.722 5.778 77.76 ;
    END
  END cfg_data[8]
  PIN cfg_data[90]
    DIRECTION INPUT ;
    USE SIGNAL ;
    PORT
      LAYER M5 ;
        RECT  24.864 77.676 24.888 77.76 ;
    END
  END cfg_data[90]
  PIN cfg_data[91]
    DIRECTION INPUT ;
    USE SIGNAL ;
    PORT
      LAYER M5 ;
        RECT  25.104 77.676 25.128 77.76 ;
    END
  END cfg_data[91]
  PIN cfg_data[92]
    DIRECTION INPUT ;
    USE SIGNAL ;
    PORT
      LAYER M5 ;
        RECT  25.296 77.676 25.32 77.76 ;
    END
  END cfg_data[92]
  PIN cfg_data[93]
    DIRECTION INPUT ;
    USE SIGNAL ;
    PORT
      LAYER M5 ;
        RECT  25.536 77.676 25.56 77.76 ;
    END
  END cfg_data[93]
  PIN cfg_data[94]
    DIRECTION INPUT ;
    USE SIGNAL ;
    PORT
      LAYER M5 ;
        RECT  25.776 77.676 25.8 77.76 ;
    END
  END cfg_data[94]
  PIN cfg_data[95]
    DIRECTION INPUT ;
    USE SIGNAL ;
    PORT
      LAYER M5 ;
        RECT  26.016 77.676 26.04 77.76 ;
    END
  END cfg_data[95]
  PIN cfg_data[96]
    DIRECTION INPUT ;
    USE SIGNAL ;
    PORT
      LAYER M5 ;
        RECT  26.256 77.676 26.28 77.76 ;
    END
  END cfg_data[96]
  PIN cfg_data[97]
    DIRECTION INPUT ;
    USE SIGNAL ;
    PORT
      LAYER M5 ;
        RECT  26.496 77.676 26.52 77.76 ;
    END
  END cfg_data[97]
  PIN cfg_data[98]
    DIRECTION INPUT ;
    USE SIGNAL ;
    PORT
      LAYER M5 ;
        RECT  26.688 77.676 26.712 77.76 ;
    END
  END cfg_data[98]
  PIN cfg_data[99]
    DIRECTION INPUT ;
    USE SIGNAL ;
    PORT
      LAYER M5 ;
        RECT  26.928 77.676 26.952 77.76 ;
    END
  END cfg_data[99]
  PIN cfg_data[9]
    DIRECTION INPUT ;
    USE SIGNAL ;
    PORT
      LAYER M3 ;
        RECT  6.012 77.722 6.03 77.76 ;
    END
  END cfg_data[9]
  PIN cfg_target[0]
    DIRECTION INPUT ;
    USE SIGNAL ;
    PORT
      LAYER M3 ;
        RECT  63.504 77.722 63.522 77.76 ;
    END
  END cfg_target[0]
  PIN cfg_target[1]
    DIRECTION INPUT ;
    USE SIGNAL ;
    PORT
      LAYER M3 ;
        RECT  63.72 77.722 63.738 77.76 ;
    END
  END cfg_target[1]
  PIN cfg_target[2]
    DIRECTION INPUT ;
    USE SIGNAL ;
    PORT
      LAYER M3 ;
        RECT  63.972 77.722 63.99 77.76 ;
    END
  END cfg_target[2]
  PIN cfg_target[3]
    DIRECTION INPUT ;
    USE SIGNAL ;
    PORT
      LAYER M3 ;
        RECT  64.188 77.722 64.206 77.76 ;
    END
  END cfg_target[3]
  PIN cfg_target[4]
    DIRECTION INPUT ;
    USE SIGNAL ;
    PORT
      LAYER M3 ;
        RECT  64.44 77.722 64.458 77.76 ;
    END
  END cfg_target[4]
  PIN cfg_target[5]
    DIRECTION INPUT ;
    USE SIGNAL ;
    PORT
      LAYER M3 ;
        RECT  64.656 77.722 64.674 77.76 ;
    END
  END cfg_target[5]
  PIN cfg_target[6]
    DIRECTION INPUT ;
    USE SIGNAL ;
    PORT
      LAYER M3 ;
        RECT  64.908 77.722 64.926 77.76 ;
    END
  END cfg_target[6]
  PIN cfg_target[7]
    DIRECTION INPUT ;
    USE SIGNAL ;
    PORT
      LAYER M3 ;
        RECT  65.124 77.722 65.142 77.76 ;
    END
  END cfg_target[7]
  PIN cfg_v
    DIRECTION INPUT ;
    USE SIGNAL ;
    PORT
      LAYER M3 ;
        RECT  65.376 77.722 65.394 77.76 ;
    END
  END cfg_v
  PIN clk
    DIRECTION INPUT ;
    USE SIGNAL ;
    PORT
      LAYER M3 ;
        RECT  65.592 77.722 65.61 77.76 ;
    END
  END clk
  PIN configured
    DIRECTION OUTPUT ;
    USE SIGNAL ;
    PORT
      LAYER M3 ;
        RECT  65.808 77.722 65.826 77.76 ;
    END
  END configured
  PIN desc_base[0]
    DIRECTION INPUT ;
    USE SIGNAL ;
    PORT
      LAYER M3 ;
        RECT  66.06 77.722 66.078 77.76 ;
    END
  END desc_base[0]
  PIN desc_base[10]
    DIRECTION INPUT ;
    USE SIGNAL ;
    PORT
      LAYER M5 ;
        RECT  68.4 77.676 68.424 77.76 ;
    END
  END desc_base[10]
  PIN desc_base[11]
    DIRECTION INPUT ;
    USE SIGNAL ;
    PORT
      LAYER M5 ;
        RECT  68.592 77.676 68.616 77.76 ;
    END
  END desc_base[11]
  PIN desc_base[1]
    DIRECTION INPUT ;
    USE SIGNAL ;
    PORT
      LAYER M3 ;
        RECT  66.276 77.722 66.294 77.76 ;
    END
  END desc_base[1]
  PIN desc_base[2]
    DIRECTION INPUT ;
    USE SIGNAL ;
    PORT
      LAYER M3 ;
        RECT  66.528 77.722 66.546 77.76 ;
    END
  END desc_base[2]
  PIN desc_base[3]
    DIRECTION INPUT ;
    USE SIGNAL ;
    PORT
      LAYER M3 ;
        RECT  66.744 77.722 66.762 77.76 ;
    END
  END desc_base[3]
  PIN desc_base[4]
    DIRECTION INPUT ;
    USE SIGNAL ;
    PORT
      LAYER M3 ;
        RECT  66.996 77.722 67.014 77.76 ;
    END
  END desc_base[4]
  PIN desc_base[5]
    DIRECTION INPUT ;
    USE SIGNAL ;
    PORT
      LAYER M3 ;
        RECT  67.212 77.722 67.23 77.76 ;
    END
  END desc_base[5]
  PIN desc_base[6]
    DIRECTION INPUT ;
    USE SIGNAL ;
    PORT
      LAYER M3 ;
        RECT  67.464 77.722 67.482 77.76 ;
    END
  END desc_base[6]
  PIN desc_base[7]
    DIRECTION INPUT ;
    USE SIGNAL ;
    PORT
      LAYER M3 ;
        RECT  67.68 77.722 67.698 77.76 ;
    END
  END desc_base[7]
  PIN desc_base[8]
    DIRECTION INPUT ;
    USE SIGNAL ;
    PORT
      LAYER M3 ;
        RECT  67.932 77.722 67.95 77.76 ;
    END
  END desc_base[8]
  PIN desc_base[9]
    DIRECTION INPUT ;
    USE SIGNAL ;
    PORT
      LAYER M5 ;
        RECT  68.16 77.676 68.184 77.76 ;
    END
  END desc_base[9]
  PIN desc_limit[0]
    DIRECTION INPUT ;
    USE SIGNAL ;
    PORT
      LAYER M5 ;
        RECT  68.832 77.676 68.856 77.76 ;
    END
  END desc_limit[0]
  PIN desc_limit[10]
    DIRECTION INPUT ;
    USE SIGNAL ;
    PORT
      LAYER M5 ;
        RECT  71.184 77.676 71.208 77.76 ;
    END
  END desc_limit[10]
  PIN desc_limit[11]
    DIRECTION INPUT ;
    USE SIGNAL ;
    PORT
      LAYER M5 ;
        RECT  71.424 77.676 71.448 77.76 ;
    END
  END desc_limit[11]
  PIN desc_limit[12]
    DIRECTION INPUT ;
    USE SIGNAL ;
    PORT
      LAYER M5 ;
        RECT  71.664 77.676 71.688 77.76 ;
    END
  END desc_limit[12]
  PIN desc_limit[1]
    DIRECTION INPUT ;
    USE SIGNAL ;
    PORT
      LAYER M5 ;
        RECT  69.072 77.676 69.096 77.76 ;
    END
  END desc_limit[1]
  PIN desc_limit[2]
    DIRECTION INPUT ;
    USE SIGNAL ;
    PORT
      LAYER M5 ;
        RECT  69.312 77.676 69.336 77.76 ;
    END
  END desc_limit[2]
  PIN desc_limit[3]
    DIRECTION INPUT ;
    USE SIGNAL ;
    PORT
      LAYER M5 ;
        RECT  69.552 77.676 69.576 77.76 ;
    END
  END desc_limit[3]
  PIN desc_limit[4]
    DIRECTION INPUT ;
    USE SIGNAL ;
    PORT
      LAYER M5 ;
        RECT  69.792 77.676 69.816 77.76 ;
    END
  END desc_limit[4]
  PIN desc_limit[5]
    DIRECTION INPUT ;
    USE SIGNAL ;
    PORT
      LAYER M5 ;
        RECT  70.032 77.676 70.056 77.76 ;
    END
  END desc_limit[5]
  PIN desc_limit[6]
    DIRECTION INPUT ;
    USE SIGNAL ;
    PORT
      LAYER M5 ;
        RECT  70.224 77.676 70.248 77.76 ;
    END
  END desc_limit[6]
  PIN desc_limit[7]
    DIRECTION INPUT ;
    USE SIGNAL ;
    PORT
      LAYER M5 ;
        RECT  70.464 77.676 70.488 77.76 ;
    END
  END desc_limit[7]
  PIN desc_limit[8]
    DIRECTION INPUT ;
    USE SIGNAL ;
    PORT
      LAYER M5 ;
        RECT  70.704 77.676 70.728 77.76 ;
    END
  END desc_limit[8]
  PIN desc_limit[9]
    DIRECTION INPUT ;
    USE SIGNAL ;
    PORT
      LAYER M5 ;
        RECT  70.944 77.676 70.968 77.76 ;
    END
  END desc_limit[9]
  PIN desc_loops[0]
    DIRECTION INPUT ;
    USE SIGNAL ;
    PORT
      LAYER M5 ;
        RECT  71.856 77.676 71.88 77.76 ;
    END
  END desc_loops[0]
  PIN desc_loops[10]
    DIRECTION INPUT ;
    USE SIGNAL ;
    PORT
      LAYER M5 ;
        RECT  74.208 77.676 74.232 77.76 ;
    END
  END desc_loops[10]
  PIN desc_loops[11]
    DIRECTION INPUT ;
    USE SIGNAL ;
    PORT
      LAYER M5 ;
        RECT  74.448 77.676 74.472 77.76 ;
    END
  END desc_loops[11]
  PIN desc_loops[12]
    DIRECTION INPUT ;
    USE SIGNAL ;
    PORT
      LAYER M5 ;
        RECT  74.688 77.676 74.712 77.76 ;
    END
  END desc_loops[12]
  PIN desc_loops[13]
    DIRECTION INPUT ;
    USE SIGNAL ;
    PORT
      LAYER M5 ;
        RECT  74.88 77.676 74.904 77.76 ;
    END
  END desc_loops[13]
  PIN desc_loops[14]
    DIRECTION INPUT ;
    USE SIGNAL ;
    PORT
      LAYER M5 ;
        RECT  75.12 77.676 75.144 77.76 ;
    END
  END desc_loops[14]
  PIN desc_loops[15]
    DIRECTION INPUT ;
    USE SIGNAL ;
    PORT
      LAYER M5 ;
        RECT  75.36 77.676 75.384 77.76 ;
    END
  END desc_loops[15]
  PIN desc_loops[1]
    DIRECTION INPUT ;
    USE SIGNAL ;
    PORT
      LAYER M5 ;
        RECT  72.096 77.676 72.12 77.76 ;
    END
  END desc_loops[1]
  PIN desc_loops[2]
    DIRECTION INPUT ;
    USE SIGNAL ;
    PORT
      LAYER M5 ;
        RECT  72.336 77.676 72.36 77.76 ;
    END
  END desc_loops[2]
  PIN desc_loops[3]
    DIRECTION INPUT ;
    USE SIGNAL ;
    PORT
      LAYER M5 ;
        RECT  72.576 77.676 72.6 77.76 ;
    END
  END desc_loops[3]
  PIN desc_loops[4]
    DIRECTION INPUT ;
    USE SIGNAL ;
    PORT
      LAYER M5 ;
        RECT  72.816 77.676 72.84 77.76 ;
    END
  END desc_loops[4]
  PIN desc_loops[5]
    DIRECTION INPUT ;
    USE SIGNAL ;
    PORT
      LAYER M5 ;
        RECT  73.056 77.676 73.08 77.76 ;
    END
  END desc_loops[5]
  PIN desc_loops[6]
    DIRECTION INPUT ;
    USE SIGNAL ;
    PORT
      LAYER M5 ;
        RECT  73.248 77.676 73.272 77.76 ;
    END
  END desc_loops[6]
  PIN desc_loops[7]
    DIRECTION INPUT ;
    USE SIGNAL ;
    PORT
      LAYER M5 ;
        RECT  73.488 77.676 73.512 77.76 ;
    END
  END desc_loops[7]
  PIN desc_loops[8]
    DIRECTION INPUT ;
    USE SIGNAL ;
    PORT
      LAYER M5 ;
        RECT  73.728 77.676 73.752 77.76 ;
    END
  END desc_loops[8]
  PIN desc_loops[9]
    DIRECTION INPUT ;
    USE SIGNAL ;
    PORT
      LAYER M5 ;
        RECT  73.968 77.676 73.992 77.76 ;
    END
  END desc_loops[9]
  PIN desc_v
    DIRECTION INPUT ;
    USE SIGNAL ;
    PORT
      LAYER M3 ;
        RECT  75.6 77.722 75.618 77.76 ;
    END
  END desc_v
  PIN fault
    DIRECTION OUTPUT ;
    USE SIGNAL ;
    PORT
      LAYER M3 ;
        RECT  75.816 77.722 75.834 77.76 ;
    END
  END fault
  PIN fault_cause[0]
    DIRECTION OUTPUT ;
    USE SIGNAL ;
    PORT
      LAYER M3 ;
        RECT  76.068 77.722 76.086 77.76 ;
    END
  END fault_cause[0]
  PIN fault_cause[10]
    DIRECTION OUTPUT ;
    USE SIGNAL ;
    PORT
      LAYER M3 ;
        RECT  78.408 77.722 78.426 77.76 ;
    END
  END fault_cause[10]
  PIN fault_cause[11]
    DIRECTION OUTPUT ;
    USE SIGNAL ;
    PORT
      LAYER M3 ;
        RECT  78.624 77.722 78.642 77.76 ;
    END
  END fault_cause[11]
  PIN fault_cause[12]
    DIRECTION OUTPUT ;
    USE SIGNAL ;
    PORT
      LAYER M3 ;
        RECT  78.876 77.722 78.894 77.76 ;
    END
  END fault_cause[12]
  PIN fault_cause[13]
    DIRECTION OUTPUT ;
    USE SIGNAL ;
    PORT
      LAYER M3 ;
        RECT  79.092 77.722 79.11 77.76 ;
    END
  END fault_cause[13]
  PIN fault_cause[14]
    DIRECTION OUTPUT ;
    USE SIGNAL ;
    PORT
      LAYER M3 ;
        RECT  79.308 77.722 79.326 77.76 ;
    END
  END fault_cause[14]
  PIN fault_cause[15]
    DIRECTION OUTPUT ;
    USE SIGNAL ;
    PORT
      LAYER M3 ;
        RECT  79.56 77.722 79.578 77.76 ;
    END
  END fault_cause[15]
  PIN fault_cause[1]
    DIRECTION OUTPUT ;
    USE SIGNAL ;
    PORT
      LAYER M3 ;
        RECT  76.284 77.722 76.302 77.76 ;
    END
  END fault_cause[1]
  PIN fault_cause[2]
    DIRECTION OUTPUT ;
    USE SIGNAL ;
    PORT
      LAYER M3 ;
        RECT  76.536 77.722 76.554 77.76 ;
    END
  END fault_cause[2]
  PIN fault_cause[3]
    DIRECTION OUTPUT ;
    USE SIGNAL ;
    PORT
      LAYER M3 ;
        RECT  76.752 77.722 76.77 77.76 ;
    END
  END fault_cause[3]
  PIN fault_cause[4]
    DIRECTION OUTPUT ;
    USE SIGNAL ;
    PORT
      LAYER M3 ;
        RECT  77.004 77.722 77.022 77.76 ;
    END
  END fault_cause[4]
  PIN fault_cause[5]
    DIRECTION OUTPUT ;
    USE SIGNAL ;
    PORT
      LAYER M3 ;
        RECT  77.22 77.722 77.238 77.76 ;
    END
  END fault_cause[5]
  PIN fault_cause[6]
    DIRECTION OUTPUT ;
    USE SIGNAL ;
    PORT
      LAYER M3 ;
        RECT  77.472 77.722 77.49 77.76 ;
    END
  END fault_cause[6]
  PIN fault_cause[7]
    DIRECTION OUTPUT ;
    USE SIGNAL ;
    PORT
      LAYER M3 ;
        RECT  77.688 77.722 77.706 77.76 ;
    END
  END fault_cause[7]
  PIN fault_cause[8]
    DIRECTION OUTPUT ;
    USE SIGNAL ;
    PORT
      LAYER M3 ;
        RECT  77.94 77.722 77.958 77.76 ;
    END
  END fault_cause[8]
  PIN fault_cause[9]
    DIRECTION OUTPUT ;
    USE SIGNAL ;
    PORT
      LAYER M3 ;
        RECT  78.156 77.722 78.174 77.76 ;
    END
  END fault_cause[9]
  PIN init_busy
    DIRECTION OUTPUT ;
    USE SIGNAL ;
    PORT
      LAYER M3 ;
        RECT  79.776 77.722 79.794 77.76 ;
    END
  END init_busy
  PIN issuer_busy
    DIRECTION INPUT ;
    USE SIGNAL ;
    PORT
      LAYER M3 ;
        RECT  1.692 0 1.71 0.038 ;
    END
  END issuer_busy
  PIN issuer_cfg[0]
    DIRECTION OUTPUT ;
    USE SIGNAL ;
    PORT
      LAYER M3 ;
        RECT  3.132 0 3.15 0.038 ;
    END
  END issuer_cfg[0]
  PIN issuer_cfg[10]
    DIRECTION OUTPUT ;
    USE SIGNAL ;
    PORT
      LAYER M3 ;
        RECT  17.424 0 17.442 0.038 ;
    END
  END issuer_cfg[10]
  PIN issuer_cfg[11]
    DIRECTION OUTPUT ;
    USE SIGNAL ;
    PORT
      LAYER M3 ;
        RECT  18.864 0 18.882 0.038 ;
    END
  END issuer_cfg[11]
  PIN issuer_cfg[12]
    DIRECTION OUTPUT ;
    USE SIGNAL ;
    PORT
      LAYER M3 ;
        RECT  20.304 0 20.322 0.038 ;
    END
  END issuer_cfg[12]
  PIN issuer_cfg[13]
    DIRECTION OUTPUT ;
    USE SIGNAL ;
    PORT
      LAYER M3 ;
        RECT  21.744 0 21.762 0.038 ;
    END
  END issuer_cfg[13]
  PIN issuer_cfg[14]
    DIRECTION OUTPUT ;
    USE SIGNAL ;
    PORT
      LAYER M3 ;
        RECT  23.148 0 23.166 0.038 ;
    END
  END issuer_cfg[14]
  PIN issuer_cfg[15]
    DIRECTION OUTPUT ;
    USE SIGNAL ;
    PORT
      LAYER M3 ;
        RECT  24.588 0 24.606 0.038 ;
    END
  END issuer_cfg[15]
  PIN issuer_cfg[16]
    DIRECTION OUTPUT ;
    USE SIGNAL ;
    PORT
      LAYER M3 ;
        RECT  26.028 0 26.046 0.038 ;
    END
  END issuer_cfg[16]
  PIN issuer_cfg[17]
    DIRECTION OUTPUT ;
    USE SIGNAL ;
    PORT
      LAYER M3 ;
        RECT  27.432 0 27.45 0.038 ;
    END
  END issuer_cfg[17]
  PIN issuer_cfg[18]
    DIRECTION OUTPUT ;
    USE SIGNAL ;
    PORT
      LAYER M3 ;
        RECT  28.872 0 28.89 0.038 ;
    END
  END issuer_cfg[18]
  PIN issuer_cfg[19]
    DIRECTION OUTPUT ;
    USE SIGNAL ;
    PORT
      LAYER M3 ;
        RECT  30.312 0 30.33 0.038 ;
    END
  END issuer_cfg[19]
  PIN issuer_cfg[1]
    DIRECTION OUTPUT ;
    USE SIGNAL ;
    PORT
      LAYER M3 ;
        RECT  4.572 0 4.59 0.038 ;
    END
  END issuer_cfg[1]
  PIN issuer_cfg[20]
    DIRECTION OUTPUT ;
    USE SIGNAL ;
    PORT
      LAYER M3 ;
        RECT  31.752 0 31.77 0.038 ;
    END
  END issuer_cfg[20]
  PIN issuer_cfg[21]
    DIRECTION OUTPUT ;
    USE SIGNAL ;
    PORT
      LAYER M3 ;
        RECT  33.156 0 33.174 0.038 ;
    END
  END issuer_cfg[21]
  PIN issuer_cfg[22]
    DIRECTION OUTPUT ;
    USE SIGNAL ;
    PORT
      LAYER M3 ;
        RECT  34.596 0 34.614 0.038 ;
    END
  END issuer_cfg[22]
  PIN issuer_cfg[23]
    DIRECTION OUTPUT ;
    USE SIGNAL ;
    PORT
      LAYER M3 ;
        RECT  36.036 0 36.054 0.038 ;
    END
  END issuer_cfg[23]
  PIN issuer_cfg[24]
    DIRECTION OUTPUT ;
    USE SIGNAL ;
    PORT
      LAYER M3 ;
        RECT  37.44 0 37.458 0.038 ;
    END
  END issuer_cfg[24]
  PIN issuer_cfg[25]
    DIRECTION OUTPUT ;
    USE SIGNAL ;
    PORT
      LAYER M3 ;
        RECT  38.88 0 38.898 0.038 ;
    END
  END issuer_cfg[25]
  PIN issuer_cfg[26]
    DIRECTION OUTPUT ;
    USE SIGNAL ;
    PORT
      LAYER M3 ;
        RECT  40.32 0 40.338 0.038 ;
    END
  END issuer_cfg[26]
  PIN issuer_cfg[27]
    DIRECTION OUTPUT ;
    USE SIGNAL ;
    PORT
      LAYER M3 ;
        RECT  41.76 0 41.778 0.038 ;
    END
  END issuer_cfg[27]
  PIN issuer_cfg[28]
    DIRECTION OUTPUT ;
    USE SIGNAL ;
    PORT
      LAYER M3 ;
        RECT  43.164 0 43.182 0.038 ;
    END
  END issuer_cfg[28]
  PIN issuer_cfg[29]
    DIRECTION OUTPUT ;
    USE SIGNAL ;
    PORT
      LAYER M3 ;
        RECT  44.604 0 44.622 0.038 ;
    END
  END issuer_cfg[29]
  PIN issuer_cfg[2]
    DIRECTION OUTPUT ;
    USE SIGNAL ;
    PORT
      LAYER M3 ;
        RECT  6.012 0 6.03 0.038 ;
    END
  END issuer_cfg[2]
  PIN issuer_cfg[30]
    DIRECTION OUTPUT ;
    USE SIGNAL ;
    PORT
      LAYER M3 ;
        RECT  46.044 0 46.062 0.038 ;
    END
  END issuer_cfg[30]
  PIN issuer_cfg[31]
    DIRECTION OUTPUT ;
    USE SIGNAL ;
    PORT
      LAYER M5 ;
        RECT  47.472 0 47.496 0.084 ;
    END
  END issuer_cfg[31]
  PIN issuer_cfg[32]
    DIRECTION OUTPUT ;
    USE SIGNAL ;
    PORT
      LAYER M5 ;
        RECT  48.912 0 48.936 0.084 ;
    END
  END issuer_cfg[32]
  PIN issuer_cfg[33]
    DIRECTION OUTPUT ;
    USE SIGNAL ;
    PORT
      LAYER M5 ;
        RECT  50.304 0 50.328 0.084 ;
    END
  END issuer_cfg[33]
  PIN issuer_cfg[34]
    DIRECTION OUTPUT ;
    USE SIGNAL ;
    PORT
      LAYER M5 ;
        RECT  51.744 0 51.768 0.084 ;
    END
  END issuer_cfg[34]
  PIN issuer_cfg[35]
    DIRECTION OUTPUT ;
    USE SIGNAL ;
    PORT
      LAYER M5 ;
        RECT  53.184 0 53.208 0.084 ;
    END
  END issuer_cfg[35]
  PIN issuer_cfg[36]
    DIRECTION OUTPUT ;
    USE SIGNAL ;
    PORT
      LAYER M5 ;
        RECT  54.624 0 54.648 0.084 ;
    END
  END issuer_cfg[36]
  PIN issuer_cfg[3]
    DIRECTION OUTPUT ;
    USE SIGNAL ;
    PORT
      LAYER M3 ;
        RECT  7.416 0 7.434 0.038 ;
    END
  END issuer_cfg[3]
  PIN issuer_cfg[4]
    DIRECTION OUTPUT ;
    USE SIGNAL ;
    PORT
      LAYER M3 ;
        RECT  8.856 0 8.874 0.038 ;
    END
  END issuer_cfg[4]
  PIN issuer_cfg[5]
    DIRECTION OUTPUT ;
    USE SIGNAL ;
    PORT
      LAYER M3 ;
        RECT  10.296 0 10.314 0.038 ;
    END
  END issuer_cfg[5]
  PIN issuer_cfg[6]
    DIRECTION OUTPUT ;
    USE SIGNAL ;
    PORT
      LAYER M3 ;
        RECT  11.7 0 11.718 0.038 ;
    END
  END issuer_cfg[6]
  PIN issuer_cfg[7]
    DIRECTION OUTPUT ;
    USE SIGNAL ;
    PORT
      LAYER M3 ;
        RECT  13.14 0 13.158 0.038 ;
    END
  END issuer_cfg[7]
  PIN issuer_cfg[8]
    DIRECTION OUTPUT ;
    USE SIGNAL ;
    PORT
      LAYER M3 ;
        RECT  14.58 0 14.598 0.038 ;
    END
  END issuer_cfg[8]
  PIN issuer_cfg[9]
    DIRECTION OUTPUT ;
    USE SIGNAL ;
    PORT
      LAYER M3 ;
        RECT  16.02 0 16.038 0.038 ;
    END
  END issuer_cfg[9]
  PIN issuer_fault
    DIRECTION INPUT ;
    USE SIGNAL ;
    PORT
      LAYER M5 ;
        RECT  56.064 0 56.088 0.084 ;
    END
  END issuer_fault
  PIN issuer_start
    DIRECTION OUTPUT ;
    USE SIGNAL ;
    PORT
      LAYER M5 ;
        RECT  57.456 0 57.48 0.084 ;
    END
  END issuer_start
  PIN issuer_start_pc[0]
    DIRECTION OUTPUT ;
    USE SIGNAL ;
    PORT
      LAYER M5 ;
        RECT  58.896 0 58.92 0.084 ;
    END
  END issuer_start_pc[0]
  PIN issuer_start_pc[1]
    DIRECTION OUTPUT ;
    USE SIGNAL ;
    PORT
      LAYER M5 ;
        RECT  60.336 0 60.36 0.084 ;
    END
  END issuer_start_pc[1]
  PIN issuer_start_pc[2]
    DIRECTION OUTPUT ;
    USE SIGNAL ;
    PORT
      LAYER M5 ;
        RECT  61.776 0 61.8 0.084 ;
    END
  END issuer_start_pc[2]
  PIN issuer_start_pc[3]
    DIRECTION OUTPUT ;
    USE SIGNAL ;
    PORT
      LAYER M5 ;
        RECT  63.216 0 63.24 0.084 ;
    END
  END issuer_start_pc[3]
  PIN issuer_start_pc[4]
    DIRECTION OUTPUT ;
    USE SIGNAL ;
    PORT
      LAYER M5 ;
        RECT  64.608 0 64.632 0.084 ;
    END
  END issuer_start_pc[4]
  PIN issuer_start_pc[5]
    DIRECTION OUTPUT ;
    USE SIGNAL ;
    PORT
      LAYER M5 ;
        RECT  66.048 0 66.072 0.084 ;
    END
  END issuer_start_pc[5]
  PIN issuer_start_pc[6]
    DIRECTION OUTPUT ;
    USE SIGNAL ;
    PORT
      LAYER M5 ;
        RECT  67.488 0 67.512 0.084 ;
    END
  END issuer_start_pc[6]
  PIN issuer_uop_pc[0]
    DIRECTION INPUT ;
    USE SIGNAL ;
    PORT
      LAYER M5 ;
        RECT  68.928 0 68.952 0.084 ;
    END
  END issuer_uop_pc[0]
  PIN issuer_uop_pc[1]
    DIRECTION INPUT ;
    USE SIGNAL ;
    PORT
      LAYER M5 ;
        RECT  70.32 0 70.344 0.084 ;
    END
  END issuer_uop_pc[1]
  PIN issuer_uop_pc[2]
    DIRECTION INPUT ;
    USE SIGNAL ;
    PORT
      LAYER M5 ;
        RECT  71.76 0 71.784 0.084 ;
    END
  END issuer_uop_pc[2]
  PIN issuer_uop_pc[3]
    DIRECTION INPUT ;
    USE SIGNAL ;
    PORT
      LAYER M5 ;
        RECT  73.2 0 73.224 0.084 ;
    END
  END issuer_uop_pc[3]
  PIN issuer_uop_pc[4]
    DIRECTION INPUT ;
    USE SIGNAL ;
    PORT
      LAYER M5 ;
        RECT  74.64 0 74.664 0.084 ;
    END
  END issuer_uop_pc[4]
  PIN issuer_uop_pc[5]
    DIRECTION INPUT ;
    USE SIGNAL ;
    PORT
      LAYER M5 ;
        RECT  76.08 0 76.104 0.084 ;
    END
  END issuer_uop_pc[5]
  PIN issuer_uop_pc[6]
    DIRECTION INPUT ;
    USE SIGNAL ;
    PORT
      LAYER M5 ;
        RECT  77.472 0 77.496 0.084 ;
    END
  END issuer_uop_pc[6]
  PIN issuer_uop_v
    DIRECTION INPUT ;
    USE SIGNAL ;
    PORT
      LAYER M5 ;
        RECT  78.912 0 78.936 0.084 ;
    END
  END issuer_uop_v
  PIN launch_v
    DIRECTION INPUT ;
    USE SIGNAL ;
    PORT
      LAYER M3 ;
        RECT  80.028 77.722 80.046 77.76 ;
    END
  END launch_v
  PIN link_abort[0]
    DIRECTION INPUT ;
    USE SIGNAL ;
    PORT
      LAYER M4 ;
        RECT  0 8.544 0.084 8.568 ;
    END
  END link_abort[0]
  PIN link_abort[1]
    DIRECTION INPUT ;
    USE SIGNAL ;
    PORT
      LAYER M4 ;
        RECT  0 23.712 0.084 23.736 ;
    END
  END link_abort[1]
  PIN program_active
    DIRECTION INPUT ;
    USE SIGNAL ;
    PORT
      LAYER M5 ;
        RECT  80.352 0 80.376 0.084 ;
    END
  END program_active
  PIN program_fault
    DIRECTION OUTPUT ;
    USE SIGNAL ;
    PORT
      LAYER M3 ;
        RECT  80.244 77.722 80.262 77.76 ;
    END
  END program_fault
  PIN protocol_fault
    DIRECTION INPUT ;
    USE SIGNAL ;
    PORT
      LAYER M4 ;
        RECT  81.996 15.216 82.08 15.24 ;
    END
  END protocol_fault
  PIN qid[0]
    DIRECTION INPUT ;
    USE SIGNAL ;
    PORT
      LAYER M3 ;
        RECT  80.496 77.722 80.514 77.76 ;
    END
  END qid[0]
  PIN qid[1]
    DIRECTION INPUT ;
    USE SIGNAL ;
    PORT
      LAYER M3 ;
        RECT  80.712 77.722 80.73 77.76 ;
    END
  END qid[1]
  PIN reduce_fault
    DIRECTION INPUT ;
    USE SIGNAL ;
    PORT
      LAYER M4 ;
        RECT  0 38.88 0.084 38.904 ;
    END
  END reduce_fault
  PIN ring_fault
    DIRECTION INPUT ;
    USE SIGNAL ;
    PORT
      LAYER M4 ;
        RECT  0 54 0.084 54.024 ;
    END
  END ring_fault
  PIN rst_n
    DIRECTION INPUT ;
    USE SIGNAL ;
    PORT
      LAYER M3 ;
        RECT  80.964 77.722 80.982 77.76 ;
    END
  END rst_n
  PIN select_fault[0]
    DIRECTION INPUT ;
    USE SIGNAL ;
    PORT
      LAYER M4 ;
        RECT  81.996 16.56 82.08 16.584 ;
    END
  END select_fault[0]
  PIN select_fault[10]
    DIRECTION INPUT ;
    USE SIGNAL ;
    PORT
      LAYER M4 ;
        RECT  81.996 30.096 82.08 30.12 ;
    END
  END select_fault[10]
  PIN select_fault[11]
    DIRECTION INPUT ;
    USE SIGNAL ;
    PORT
      LAYER M4 ;
        RECT  81.996 31.44 82.08 31.464 ;
    END
  END select_fault[11]
  PIN select_fault[12]
    DIRECTION INPUT ;
    USE SIGNAL ;
    PORT
      LAYER M4 ;
        RECT  81.996 32.784 82.08 32.808 ;
    END
  END select_fault[12]
  PIN select_fault[13]
    DIRECTION INPUT ;
    USE SIGNAL ;
    PORT
      LAYER M4 ;
        RECT  81.996 34.128 82.08 34.152 ;
    END
  END select_fault[13]
  PIN select_fault[14]
    DIRECTION INPUT ;
    USE SIGNAL ;
    PORT
      LAYER M4 ;
        RECT  81.996 35.472 82.08 35.496 ;
    END
  END select_fault[14]
  PIN select_fault[15]
    DIRECTION INPUT ;
    USE SIGNAL ;
    PORT
      LAYER M4 ;
        RECT  81.996 36.816 82.08 36.84 ;
    END
  END select_fault[15]
  PIN select_fault[16]
    DIRECTION INPUT ;
    USE SIGNAL ;
    PORT
      LAYER M4 ;
        RECT  81.996 38.208 82.08 38.232 ;
    END
  END select_fault[16]
  PIN select_fault[17]
    DIRECTION INPUT ;
    USE SIGNAL ;
    PORT
      LAYER M4 ;
        RECT  81.996 39.552 82.08 39.576 ;
    END
  END select_fault[17]
  PIN select_fault[1]
    DIRECTION INPUT ;
    USE SIGNAL ;
    PORT
      LAYER M4 ;
        RECT  81.996 17.904 82.08 17.928 ;
    END
  END select_fault[1]
  PIN select_fault[2]
    DIRECTION INPUT ;
    USE SIGNAL ;
    PORT
      LAYER M4 ;
        RECT  81.996 19.248 82.08 19.272 ;
    END
  END select_fault[2]
  PIN select_fault[3]
    DIRECTION INPUT ;
    USE SIGNAL ;
    PORT
      LAYER M4 ;
        RECT  81.996 20.592 82.08 20.616 ;
    END
  END select_fault[3]
  PIN select_fault[4]
    DIRECTION INPUT ;
    USE SIGNAL ;
    PORT
      LAYER M4 ;
        RECT  81.996 21.936 82.08 21.96 ;
    END
  END select_fault[4]
  PIN select_fault[5]
    DIRECTION INPUT ;
    USE SIGNAL ;
    PORT
      LAYER M4 ;
        RECT  81.996 23.328 82.08 23.352 ;
    END
  END select_fault[5]
  PIN select_fault[6]
    DIRECTION INPUT ;
    USE SIGNAL ;
    PORT
      LAYER M4 ;
        RECT  81.996 24.672 82.08 24.696 ;
    END
  END select_fault[6]
  PIN select_fault[7]
    DIRECTION INPUT ;
    USE SIGNAL ;
    PORT
      LAYER M4 ;
        RECT  81.996 26.016 82.08 26.04 ;
    END
  END select_fault[7]
  PIN select_fault[8]
    DIRECTION INPUT ;
    USE SIGNAL ;
    PORT
      LAYER M4 ;
        RECT  81.996 27.36 82.08 27.384 ;
    END
  END select_fault[8]
  PIN select_fault[9]
    DIRECTION INPUT ;
    USE SIGNAL ;
    PORT
      LAYER M4 ;
        RECT  81.996 28.704 82.08 28.728 ;
    END
  END select_fault[9]
  PIN tkm_del_slot[0]
    DIRECTION INPUT ;
    USE SIGNAL ;
    PORT
      LAYER M4 ;
        RECT  81.996 40.896 82.08 40.92 ;
    END
  END tkm_del_slot[0]
  PIN tkm_del_slot[1]
    DIRECTION INPUT ;
    USE SIGNAL ;
    PORT
      LAYER M4 ;
        RECT  81.996 42.24 82.08 42.264 ;
    END
  END tkm_del_slot[1]
  PIN tkm_del_slot[2]
    DIRECTION INPUT ;
    USE SIGNAL ;
    PORT
      LAYER M4 ;
        RECT  81.996 43.584 82.08 43.608 ;
    END
  END tkm_del_slot[2]
  PIN tkm_del_slot[3]
    DIRECTION INPUT ;
    USE SIGNAL ;
    PORT
      LAYER M4 ;
        RECT  81.996 44.976 82.08 45 ;
    END
  END tkm_del_slot[3]
  PIN tkm_dest_v[0]
    DIRECTION INPUT ;
    USE SIGNAL ;
    PORT
      LAYER M4 ;
        RECT  81.996 46.32 82.08 46.344 ;
    END
  END tkm_dest_v[0]
  PIN tkm_dest_v[1]
    DIRECTION INPUT ;
    USE SIGNAL ;
    PORT
      LAYER M4 ;
        RECT  81.996 47.664 82.08 47.688 ;
    END
  END tkm_dest_v[1]
  PIN tkm_dest_v[2]
    DIRECTION INPUT ;
    USE SIGNAL ;
    PORT
      LAYER M4 ;
        RECT  81.996 49.008 82.08 49.032 ;
    END
  END tkm_dest_v[2]
  PIN tkm_dest_v[3]
    DIRECTION INPUT ;
    USE SIGNAL ;
    PORT
      LAYER M4 ;
        RECT  81.996 50.352 82.08 50.376 ;
    END
  END tkm_dest_v[3]
  PIN tkm_start
    DIRECTION INPUT ;
    USE SIGNAL ;
    PORT
      LAYER M4 ;
        RECT  81.996 51.744 82.08 51.768 ;
    END
  END tkm_start
  PIN unavailable_fault[0]
    DIRECTION INPUT ;
    USE SIGNAL ;
    PORT
      LAYER M4 ;
        RECT  81.996 53.088 82.08 53.112 ;
    END
  END unavailable_fault[0]
  PIN unavailable_fault[10]
    DIRECTION INPUT ;
    USE SIGNAL ;
    PORT
      LAYER M4 ;
        RECT  81.996 66.624 82.08 66.648 ;
    END
  END unavailable_fault[10]
  PIN unavailable_fault[11]
    DIRECTION INPUT ;
    USE SIGNAL ;
    PORT
      LAYER M4 ;
        RECT  81.996 67.968 82.08 67.992 ;
    END
  END unavailable_fault[11]
  PIN unavailable_fault[12]
    DIRECTION INPUT ;
    USE SIGNAL ;
    PORT
      LAYER M4 ;
        RECT  81.996 69.312 82.08 69.336 ;
    END
  END unavailable_fault[12]
  PIN unavailable_fault[13]
    DIRECTION INPUT ;
    USE SIGNAL ;
    PORT
      LAYER M4 ;
        RECT  81.996 70.656 82.08 70.68 ;
    END
  END unavailable_fault[13]
  PIN unavailable_fault[14]
    DIRECTION INPUT ;
    USE SIGNAL ;
    PORT
      LAYER M4 ;
        RECT  81.996 72 82.08 72.024 ;
    END
  END unavailable_fault[14]
  PIN unavailable_fault[15]
    DIRECTION INPUT ;
    USE SIGNAL ;
    PORT
      LAYER M4 ;
        RECT  81.996 73.344 82.08 73.368 ;
    END
  END unavailable_fault[15]
  PIN unavailable_fault[16]
    DIRECTION INPUT ;
    USE SIGNAL ;
    PORT
      LAYER M4 ;
        RECT  81.996 74.736 82.08 74.76 ;
    END
  END unavailable_fault[16]
  PIN unavailable_fault[17]
    DIRECTION INPUT ;
    USE SIGNAL ;
    PORT
      LAYER M4 ;
        RECT  81.996 76.08 82.08 76.104 ;
    END
  END unavailable_fault[17]
  PIN unavailable_fault[1]
    DIRECTION INPUT ;
    USE SIGNAL ;
    PORT
      LAYER M4 ;
        RECT  81.996 54.432 82.08 54.456 ;
    END
  END unavailable_fault[1]
  PIN unavailable_fault[2]
    DIRECTION INPUT ;
    USE SIGNAL ;
    PORT
      LAYER M4 ;
        RECT  81.996 55.776 82.08 55.8 ;
    END
  END unavailable_fault[2]
  PIN unavailable_fault[3]
    DIRECTION INPUT ;
    USE SIGNAL ;
    PORT
      LAYER M4 ;
        RECT  81.996 57.12 82.08 57.144 ;
    END
  END unavailable_fault[3]
  PIN unavailable_fault[4]
    DIRECTION INPUT ;
    USE SIGNAL ;
    PORT
      LAYER M4 ;
        RECT  81.996 58.464 82.08 58.488 ;
    END
  END unavailable_fault[4]
  PIN unavailable_fault[5]
    DIRECTION INPUT ;
    USE SIGNAL ;
    PORT
      LAYER M4 ;
        RECT  81.996 59.856 82.08 59.88 ;
    END
  END unavailable_fault[5]
  PIN unavailable_fault[6]
    DIRECTION INPUT ;
    USE SIGNAL ;
    PORT
      LAYER M4 ;
        RECT  81.996 61.2 82.08 61.224 ;
    END
  END unavailable_fault[6]
  PIN unavailable_fault[7]
    DIRECTION INPUT ;
    USE SIGNAL ;
    PORT
      LAYER M4 ;
        RECT  81.996 62.544 82.08 62.568 ;
    END
  END unavailable_fault[7]
  PIN unavailable_fault[8]
    DIRECTION INPUT ;
    USE SIGNAL ;
    PORT
      LAYER M4 ;
        RECT  81.996 63.888 82.08 63.912 ;
    END
  END unavailable_fault[8]
  PIN unavailable_fault[9]
    DIRECTION INPUT ;
    USE SIGNAL ;
    PORT
      LAYER M4 ;
        RECT  81.996 65.232 82.08 65.256 ;
    END
  END unavailable_fault[9]
  PIN writer_fault
    DIRECTION INPUT ;
    USE SIGNAL ;
    PORT
      LAYER M4 ;
        RECT  0 69.168 0.084 69.192 ;
    END
  END writer_fault
  PIN VDD
    DIRECTION INOUT ;
    USE POWER ;
    PORT
      LAYER M5 ;
        RECT  78.192 2.151 78.312 75.609 ;
        RECT  72.792 2.151 72.912 75.609 ;
        RECT  67.392 2.151 67.512 75.609 ;
        RECT  61.992 2.151 62.112 75.609 ;
        RECT  56.592 2.151 56.712 75.609 ;
        RECT  51.192 2.151 51.312 75.609 ;
        RECT  45.792 2.151 45.912 75.609 ;
        RECT  40.392 2.151 40.512 75.609 ;
        RECT  34.992 2.151 35.112 75.609 ;
        RECT  29.592 2.151 29.712 75.609 ;
        RECT  24.192 2.151 24.312 75.609 ;
        RECT  18.792 2.151 18.912 75.609 ;
        RECT  13.392 2.151 13.512 75.609 ;
        RECT  7.992 2.151 8.112 75.609 ;
        RECT  2.592 2.151 2.712 75.609 ;
    END
  END VDD
  PIN VSS
    DIRECTION INOUT ;
    USE GROUND ;
    PORT
      LAYER M5 ;
        RECT  78 2.137 78.12 75.623 ;
        RECT  72.6 2.137 72.72 75.623 ;
        RECT  67.2 2.137 67.32 75.623 ;
        RECT  61.8 2.137 61.92 75.623 ;
        RECT  56.4 2.137 56.52 75.623 ;
        RECT  51 2.137 51.12 75.623 ;
        RECT  45.6 2.137 45.72 75.623 ;
        RECT  40.2 2.137 40.32 75.623 ;
        RECT  34.8 2.137 34.92 75.623 ;
        RECT  29.4 2.137 29.52 75.623 ;
        RECT  24 2.137 24.12 75.623 ;
        RECT  18.6 2.137 18.72 75.623 ;
        RECT  13.2 2.137 13.32 75.623 ;
        RECT  7.8 2.137 7.92 75.623 ;
        RECT  2.4 2.137 2.52 75.623 ;
    END
  END VSS
  OBS
    LAYER LVTN ;
     RECT  39.42 10.125 39.798 10.26 ;
     RECT  14.85 15.525 15.282 15.66 ;
     RECT  12.366 16.2 12.798 16.335 ;
     RECT  24.246 16.605 24.57 16.74 ;
     RECT  12.582 17.685 12.852 17.82 ;
     RECT  52.866 18.765 53.244 18.9 ;
     RECT  28.782 19.305 29.214 19.44 ;
     RECT  55.62 19.44 56.052 19.575 ;
     RECT  54.81 19.98 55.296 20.115 ;
     RECT  55.728 19.98 56.16 20.115 ;
     RECT  54.54 20.385 55.026 20.52 ;
     RECT  55.566 20.385 55.89 20.52 ;
     RECT  56.268 20.385 56.808 20.52 ;
     RECT  54.324 20.52 54.81 20.655 ;
     RECT  49.356 20.925 50.22 21.06 ;
     RECT  54.324 20.925 54.81 21.06 ;
     RECT  55.242 20.925 55.674 21.06 ;
     RECT  56.322 21.06 57.078 21.195 ;
     RECT  56.538 21.6 56.97 21.735 ;
     RECT  25.164 22.005 25.488 22.14 ;
     RECT  54.702 22.005 55.026 22.14 ;
     RECT  55.35 22.005 55.782 22.14 ;
     RECT  56.43 22.005 56.97 22.14 ;
     RECT  35.1 23.22 35.424 23.355 ;
     RECT  34.83 23.625 35.478 23.76 ;
     RECT  20.088 25.245 20.628 25.38 ;
     RECT  53.946 26.325 54.486 26.46 ;
     RECT  56.7 27 57.456 27.135 ;
     RECT  21.006 27.54 21.276 27.675 ;
     RECT  21.222 27.945 21.654 28.08 ;
     RECT  58.482 29.16 58.806 29.295 ;
     RECT  59.562 29.16 59.724 29.295 ;
     RECT  28.566 30.78 29.214 30.915 ;
     RECT  29.754 31.185 30.294 31.32 ;
     RECT  45.63 33.48 45.954 33.615 ;
     RECT  49.41 33.48 49.95 33.615 ;
     RECT  57.672 34.02 57.996 34.155 ;
     RECT  38.178 36.18 38.718 36.315 ;
     RECT  75.492 36.585 76.032 36.72 ;
     RECT  68.526 42.66 69.066 42.795 ;
     RECT  68.31 43.065 69.714 43.2 ;
     RECT  37.8 43.2 38.124 43.335 ;
     RECT  68.58 43.2 68.85 43.335 ;
     RECT  36.666 43.605 36.99 43.74 ;
     RECT  68.472 43.74 68.904 43.875 ;
     RECT  66.042 44.145 67.446 44.28 ;
     RECT  66.96 44.28 67.338 44.415 ;
     RECT  37.368 44.685 38.124 44.82 ;
     RECT  35.37 44.82 35.694 44.955 ;
     RECT  37.908 44.82 38.232 44.955 ;
     RECT  37.8 46.98 38.88 47.115 ;
     RECT  15.606 61.02 16.146 61.155 ;
     RECT  74.25 67.5 75.654 67.635 ;
     RECT  37.368 68.58 38.448 68.715 ;
     RECT  13.608 69.525 14.04 69.66 ;
     RECT  53.73 69.66 54.108 69.795 ;
     RECT  53.892 70.605 54.324 70.74 ;
     RECT  13.662 71.145 13.986 71.28 ;
     RECT  13.824 71.28 14.094 71.415 ;
     RECT  60.102 71.28 60.48 71.415 ;
     RECT  12.528 71.685 13.284 71.82 ;
     RECT  50.598 71.685 50.976 71.82 ;
     RECT  13.176 71.82 13.446 71.955 ;
     RECT  59.076 71.82 59.508 71.955 ;
     RECT  65.826 73.98 67.23 74.115 ;
     RECT  75.114 74.52 76.518 74.655 ;
    LAYER LVTP ;
     RECT  39.42 9.99 39.798 10.125 ;
     RECT  14.85 15.39 15.282 15.525 ;
     RECT  12.366 16.335 12.798 16.47 ;
     RECT  24.246 16.47 24.57 16.605 ;
     RECT  12.582 17.55 12.852 17.685 ;
     RECT  52.866 18.63 53.244 18.765 ;
     RECT  28.782 19.17 29.214 19.305 ;
     RECT  55.62 19.575 56.052 19.71 ;
     RECT  54.81 20.115 55.296 20.25 ;
     RECT  55.728 20.115 56.16 20.25 ;
     RECT  54.54 20.25 55.026 20.385 ;
     RECT  55.566 20.25 55.89 20.385 ;
     RECT  56.268 20.25 56.808 20.385 ;
     RECT  49.356 20.79 50.22 20.925 ;
     RECT  54.324 20.655 54.81 20.925 ;
     RECT  55.242 20.79 55.674 20.925 ;
     RECT  56.322 21.195 57.078 21.33 ;
     RECT  56.538 21.735 56.97 21.87 ;
     RECT  25.164 21.87 25.488 22.005 ;
     RECT  54.702 21.87 55.026 22.005 ;
     RECT  55.35 21.87 55.782 22.005 ;
     RECT  56.43 21.87 56.97 22.005 ;
     RECT  35.1 23.355 35.424 23.49 ;
     RECT  34.83 23.49 35.478 23.625 ;
     RECT  20.088 25.11 20.628 25.245 ;
     RECT  53.946 26.19 54.486 26.325 ;
     RECT  56.7 27.135 57.456 27.27 ;
     RECT  21.006 27.675 21.276 27.81 ;
     RECT  21.222 27.81 21.654 27.945 ;
     RECT  58.482 29.295 58.806 29.43 ;
     RECT  59.562 29.295 59.724 29.43 ;
     RECT  28.566 30.915 29.214 31.05 ;
     RECT  29.754 31.05 30.294 31.185 ;
     RECT  45.63 33.615 45.954 33.75 ;
     RECT  49.41 33.615 49.95 33.75 ;
     RECT  57.672 34.155 57.996 34.29 ;
     RECT  38.178 36.315 38.718 36.45 ;
     RECT  75.492 36.45 76.032 36.585 ;
     RECT  68.526 42.795 69.066 42.93 ;
     RECT  68.31 42.93 69.714 43.065 ;
     RECT  37.8 43.335 38.124 43.47 ;
     RECT  68.58 43.335 68.85 43.47 ;
     RECT  36.666 43.47 36.99 43.605 ;
     RECT  68.472 43.875 68.904 44.01 ;
     RECT  66.042 44.01 67.446 44.145 ;
     RECT  66.96 44.415 67.338 44.55 ;
     RECT  37.368 44.55 38.124 44.685 ;
     RECT  35.37 44.955 35.694 45.09 ;
     RECT  37.908 44.955 38.232 45.09 ;
     RECT  37.8 47.115 38.88 47.25 ;
     RECT  15.606 61.155 16.146 61.29 ;
     RECT  74.25 67.635 75.654 67.77 ;
     RECT  37.368 68.715 38.448 68.85 ;
     RECT  13.608 69.39 14.04 69.525 ;
     RECT  53.73 69.795 54.108 69.93 ;
     RECT  53.892 70.47 54.324 70.605 ;
     RECT  13.662 71.01 13.986 71.145 ;
     RECT  13.824 71.415 14.094 71.55 ;
     RECT  60.102 71.415 60.48 71.55 ;
     RECT  12.528 71.55 13.284 71.685 ;
     RECT  50.598 71.55 50.976 71.685 ;
     RECT  13.176 71.955 13.446 72.09 ;
     RECT  59.076 71.955 59.508 72.09 ;
     RECT  65.826 74.115 67.23 74.25 ;
     RECT  75.114 74.655 76.518 74.79 ;
    LAYER RVTN ;
     RECT  2.16 2.16 79.92 2.295 ;
     RECT  2.16 2.565 79.92 2.835 ;
     RECT  2.16 3.105 79.92 3.375 ;
     RECT  2.16 3.645 79.92 3.915 ;
     RECT  2.16 4.185 79.92 4.455 ;
     RECT  2.16 4.725 79.92 4.995 ;
     RECT  2.16 5.265 79.92 5.535 ;
     RECT  2.16 5.805 79.92 6.075 ;
     RECT  2.16 6.345 79.92 6.615 ;
     RECT  2.16 6.885 79.92 7.155 ;
     RECT  2.16 7.425 79.92 7.695 ;
     RECT  2.16 7.965 79.92 8.235 ;
     RECT  2.16 8.505 79.92 8.775 ;
     RECT  2.16 9.045 79.92 9.315 ;
     RECT  2.16 9.585 79.92 9.855 ;
     RECT  2.16 10.125 39.42 10.26 ;
     RECT  39.798 10.125 79.92 10.26 ;
     RECT  2.16 10.26 79.92 10.395 ;
     RECT  2.16 10.665 79.92 10.935 ;
     RECT  2.16 11.205 79.92 11.475 ;
     RECT  2.16 11.745 79.92 12.015 ;
     RECT  2.16 12.285 79.92 12.555 ;
     RECT  2.16 12.825 79.92 13.095 ;
     RECT  2.16 13.365 79.92 13.635 ;
     RECT  2.16 13.905 79.92 14.175 ;
     RECT  2.16 14.445 79.92 14.715 ;
     RECT  2.16 14.985 79.92 15.255 ;
     RECT  2.16 15.525 14.85 15.66 ;
     RECT  15.282 15.525 79.92 15.66 ;
     RECT  2.16 15.66 79.92 15.795 ;
     RECT  2.16 16.065 79.92 16.2 ;
     RECT  2.16 16.2 12.366 16.335 ;
     RECT  12.798 16.2 79.92 16.335 ;
     RECT  2.16 16.605 24.246 16.74 ;
     RECT  24.57 16.605 79.92 16.74 ;
     RECT  2.16 16.74 79.92 16.875 ;
     RECT  2.16 17.145 79.92 17.415 ;
     RECT  2.16 17.685 12.582 17.82 ;
     RECT  12.852 17.685 79.92 17.82 ;
     RECT  2.16 17.82 79.92 17.955 ;
     RECT  2.16 18.225 79.92 18.495 ;
     RECT  2.16 18.765 52.866 18.9 ;
     RECT  53.244 18.765 79.92 18.9 ;
     RECT  2.16 18.9 79.92 19.035 ;
     RECT  2.16 19.305 28.782 19.44 ;
     RECT  29.214 19.305 79.92 19.44 ;
     RECT  2.16 19.44 55.62 19.575 ;
     RECT  56.052 19.44 79.92 19.575 ;
     RECT  2.16 19.845 79.92 19.98 ;
     RECT  2.16 19.98 54.81 20.115 ;
     RECT  55.296 19.98 55.728 20.115 ;
     RECT  56.16 19.98 79.92 20.115 ;
     RECT  2.16 20.385 54.54 20.52 ;
     RECT  55.026 20.385 55.566 20.52 ;
     RECT  55.89 20.385 56.268 20.52 ;
     RECT  56.808 20.385 79.92 20.52 ;
     RECT  2.16 20.52 54.324 20.655 ;
     RECT  54.81 20.52 79.92 20.655 ;
     RECT  2.16 20.925 49.356 21.06 ;
     RECT  50.22 20.925 54.324 21.06 ;
     RECT  54.81 20.925 55.242 21.06 ;
     RECT  55.674 20.925 79.92 21.06 ;
     RECT  2.16 21.06 56.322 21.195 ;
     RECT  57.078 21.06 79.92 21.195 ;
     RECT  2.16 21.465 79.92 21.6 ;
     RECT  2.16 21.6 56.538 21.735 ;
     RECT  56.97 21.6 79.92 21.735 ;
     RECT  2.16 22.005 25.164 22.14 ;
     RECT  25.488 22.005 54.702 22.14 ;
     RECT  55.026 22.005 55.35 22.14 ;
     RECT  55.782 22.005 56.43 22.14 ;
     RECT  56.97 22.005 79.92 22.14 ;
     RECT  2.16 22.14 79.92 22.275 ;
     RECT  2.16 22.545 79.92 22.815 ;
     RECT  2.16 23.085 79.92 23.22 ;
     RECT  2.16 23.22 35.1 23.355 ;
     RECT  35.424 23.22 79.92 23.355 ;
     RECT  2.16 23.625 34.83 23.76 ;
     RECT  35.478 23.625 79.92 23.76 ;
     RECT  2.16 23.76 79.92 23.895 ;
     RECT  2.16 24.165 79.92 24.435 ;
     RECT  2.16 24.705 79.92 24.975 ;
     RECT  2.16 25.245 20.088 25.38 ;
     RECT  20.628 25.245 79.92 25.38 ;
     RECT  2.16 25.38 79.92 25.515 ;
     RECT  2.16 25.785 79.92 26.055 ;
     RECT  2.16 26.325 53.946 26.46 ;
     RECT  54.486 26.325 79.92 26.46 ;
     RECT  2.16 26.46 79.92 26.595 ;
     RECT  2.16 26.865 79.92 27 ;
     RECT  2.16 27 56.7 27.135 ;
     RECT  57.456 27 79.92 27.135 ;
     RECT  2.16 27.405 79.92 27.54 ;
     RECT  2.16 27.54 21.006 27.675 ;
     RECT  21.276 27.54 79.92 27.675 ;
     RECT  2.16 27.945 21.222 28.08 ;
     RECT  21.654 27.945 79.92 28.08 ;
     RECT  2.16 28.08 79.92 28.215 ;
     RECT  2.16 28.485 79.92 28.755 ;
     RECT  2.16 29.025 79.92 29.16 ;
     RECT  2.16 29.16 58.482 29.295 ;
     RECT  58.806 29.16 59.562 29.295 ;
     RECT  59.724 29.16 79.92 29.295 ;
     RECT  2.16 29.565 79.92 29.835 ;
     RECT  2.16 30.105 79.92 30.375 ;
     RECT  2.16 30.645 79.92 30.78 ;
     RECT  2.16 30.78 28.566 30.915 ;
     RECT  29.214 30.78 79.92 30.915 ;
     RECT  2.16 31.185 29.754 31.32 ;
     RECT  30.294 31.185 79.92 31.32 ;
     RECT  2.16 31.32 79.92 31.455 ;
     RECT  2.16 31.725 79.92 31.995 ;
     RECT  2.16 32.265 79.92 32.535 ;
     RECT  2.16 32.805 79.92 33.075 ;
     RECT  2.16 33.345 79.92 33.48 ;
     RECT  2.16 33.48 45.63 33.615 ;
     RECT  45.954 33.48 49.41 33.615 ;
     RECT  49.95 33.48 79.92 33.615 ;
     RECT  2.16 33.885 79.92 34.02 ;
     RECT  2.16 34.02 57.672 34.155 ;
     RECT  57.996 34.02 79.92 34.155 ;
     RECT  2.16 34.425 79.92 34.695 ;
     RECT  2.16 34.965 79.92 35.235 ;
     RECT  2.16 35.505 79.92 35.775 ;
     RECT  2.16 36.045 79.92 36.18 ;
     RECT  2.16 36.18 38.178 36.315 ;
     RECT  38.718 36.18 79.92 36.315 ;
     RECT  2.16 36.585 75.492 36.72 ;
     RECT  76.032 36.585 79.92 36.72 ;
     RECT  2.16 36.72 79.92 36.855 ;
     RECT  2.16 37.125 79.92 37.395 ;
     RECT  2.16 37.665 79.92 37.935 ;
     RECT  2.16 38.205 79.92 38.475 ;
     RECT  2.16 38.745 79.92 39.015 ;
     RECT  2.16 39.285 79.92 39.555 ;
     RECT  2.16 39.825 79.92 40.095 ;
     RECT  2.16 40.365 79.92 40.635 ;
     RECT  2.16 40.905 79.92 41.175 ;
     RECT  2.16 41.445 79.92 41.715 ;
     RECT  2.16 41.985 79.92 42.255 ;
     RECT  2.16 42.525 79.92 42.66 ;
     RECT  2.16 42.66 68.526 42.795 ;
     RECT  69.066 42.66 79.92 42.795 ;
     RECT  2.16 43.065 68.31 43.2 ;
     RECT  69.714 43.065 79.92 43.2 ;
     RECT  2.16 43.2 37.8 43.335 ;
     RECT  38.124 43.2 68.58 43.335 ;
     RECT  68.85 43.2 79.92 43.335 ;
     RECT  2.16 43.605 36.666 43.74 ;
     RECT  36.99 43.605 79.92 43.74 ;
     RECT  2.16 43.74 68.472 43.875 ;
     RECT  68.904 43.74 79.92 43.875 ;
     RECT  2.16 44.145 66.042 44.28 ;
     RECT  67.446 44.145 79.92 44.28 ;
     RECT  2.16 44.28 66.96 44.415 ;
     RECT  67.338 44.28 79.92 44.415 ;
     RECT  2.16 44.685 37.368 44.82 ;
     RECT  38.124 44.685 79.92 44.82 ;
     RECT  2.16 44.82 35.37 44.955 ;
     RECT  35.694 44.82 37.908 44.955 ;
     RECT  38.232 44.82 79.92 44.955 ;
     RECT  2.16 45.225 79.92 45.495 ;
     RECT  2.16 45.765 79.92 46.035 ;
     RECT  2.16 46.305 79.92 46.575 ;
     RECT  2.16 46.845 79.92 46.98 ;
     RECT  2.16 46.98 37.8 47.115 ;
     RECT  38.88 46.98 79.92 47.115 ;
     RECT  2.16 47.385 79.92 47.655 ;
     RECT  2.16 47.925 79.92 48.195 ;
     RECT  2.16 48.465 79.92 48.735 ;
     RECT  2.16 49.005 79.92 49.275 ;
     RECT  2.16 49.545 79.92 49.815 ;
     RECT  2.16 50.085 79.92 50.355 ;
     RECT  2.16 50.625 79.92 50.895 ;
     RECT  2.16 51.165 79.92 51.435 ;
     RECT  2.16 51.705 79.92 51.975 ;
     RECT  2.16 52.245 79.92 52.515 ;
     RECT  2.16 52.785 79.92 53.055 ;
     RECT  2.16 53.325 79.92 53.595 ;
     RECT  2.16 53.865 79.92 54.135 ;
     RECT  2.16 54.405 79.92 54.675 ;
     RECT  2.16 54.945 79.92 55.215 ;
     RECT  2.16 55.485 79.92 55.755 ;
     RECT  2.16 56.025 79.92 56.295 ;
     RECT  2.16 56.565 79.92 56.835 ;
     RECT  2.16 57.105 79.92 57.375 ;
     RECT  2.16 57.645 79.92 57.915 ;
     RECT  2.16 58.185 79.92 58.455 ;
     RECT  2.16 58.725 79.92 58.995 ;
     RECT  2.16 59.265 79.92 59.535 ;
     RECT  2.16 59.805 79.92 60.075 ;
     RECT  2.16 60.345 79.92 60.615 ;
     RECT  2.16 60.885 79.92 61.02 ;
     RECT  2.16 61.02 15.606 61.155 ;
     RECT  16.146 61.02 79.92 61.155 ;
     RECT  2.16 61.425 79.92 61.695 ;
     RECT  2.16 61.965 79.92 62.235 ;
     RECT  2.16 62.505 79.92 62.775 ;
     RECT  2.16 63.045 79.92 63.315 ;
     RECT  2.16 63.585 79.92 63.855 ;
     RECT  2.16 64.125 79.92 64.395 ;
     RECT  2.16 64.665 79.92 64.935 ;
     RECT  2.16 65.205 79.92 65.475 ;
     RECT  2.16 65.745 79.92 66.015 ;
     RECT  2.16 66.285 79.92 66.555 ;
     RECT  2.16 66.825 79.92 67.095 ;
     RECT  2.16 67.365 79.92 67.5 ;
     RECT  2.16 67.5 74.25 67.635 ;
     RECT  75.654 67.5 79.92 67.635 ;
     RECT  2.16 67.905 79.92 68.175 ;
     RECT  2.16 68.445 79.92 68.58 ;
     RECT  2.16 68.58 37.368 68.715 ;
     RECT  38.448 68.58 79.92 68.715 ;
     RECT  2.16 68.985 79.92 69.255 ;
     RECT  2.16 69.525 13.608 69.66 ;
     RECT  14.04 69.525 79.92 69.66 ;
     RECT  2.16 69.66 53.73 69.795 ;
     RECT  54.108 69.66 79.92 69.795 ;
     RECT  2.16 70.065 79.92 70.335 ;
     RECT  2.16 70.605 53.892 70.74 ;
     RECT  54.324 70.605 79.92 70.74 ;
     RECT  2.16 70.74 79.92 70.875 ;
     RECT  2.16 71.145 13.662 71.28 ;
     RECT  13.986 71.145 79.92 71.28 ;
     RECT  2.16 71.28 13.824 71.415 ;
     RECT  14.094 71.28 60.102 71.415 ;
     RECT  60.48 71.28 79.92 71.415 ;
     RECT  2.16 71.685 12.528 71.82 ;
     RECT  13.284 71.685 50.598 71.82 ;
     RECT  50.976 71.685 79.92 71.82 ;
     RECT  2.16 71.82 13.176 71.955 ;
     RECT  13.446 71.82 59.076 71.955 ;
     RECT  59.508 71.82 79.92 71.955 ;
     RECT  2.16 72.225 79.92 72.495 ;
     RECT  2.16 72.765 79.92 73.035 ;
     RECT  2.16 73.305 79.92 73.575 ;
     RECT  2.16 73.845 79.92 73.98 ;
     RECT  2.16 73.98 65.826 74.115 ;
     RECT  67.23 73.98 79.92 74.115 ;
     RECT  2.16 74.385 79.92 74.52 ;
     RECT  2.16 74.52 75.114 74.655 ;
     RECT  76.518 74.52 79.92 74.655 ;
     RECT  2.16 74.925 79.92 75.195 ;
     RECT  2.16 75.465 79.92 75.6 ;
    LAYER RVTP ;
     RECT  2.16 2.295 79.92 2.565 ;
     RECT  2.16 2.835 79.92 3.105 ;
     RECT  2.16 3.375 79.92 3.645 ;
     RECT  2.16 3.915 79.92 4.185 ;
     RECT  2.16 4.455 79.92 4.725 ;
     RECT  2.16 4.995 79.92 5.265 ;
     RECT  2.16 5.535 79.92 5.805 ;
     RECT  2.16 6.075 79.92 6.345 ;
     RECT  2.16 6.615 79.92 6.885 ;
     RECT  2.16 7.155 79.92 7.425 ;
     RECT  2.16 7.695 79.92 7.965 ;
     RECT  2.16 8.235 79.92 8.505 ;
     RECT  2.16 8.775 79.92 9.045 ;
     RECT  2.16 9.315 79.92 9.585 ;
     RECT  2.16 9.855 79.92 9.99 ;
     RECT  2.16 9.99 39.42 10.125 ;
     RECT  39.798 9.99 79.92 10.125 ;
     RECT  2.16 10.395 79.92 10.665 ;
     RECT  2.16 10.935 79.92 11.205 ;
     RECT  2.16 11.475 79.92 11.745 ;
     RECT  2.16 12.015 79.92 12.285 ;
     RECT  2.16 12.555 79.92 12.825 ;
     RECT  2.16 13.095 79.92 13.365 ;
     RECT  2.16 13.635 79.92 13.905 ;
     RECT  2.16 14.175 79.92 14.445 ;
     RECT  2.16 14.715 79.92 14.985 ;
     RECT  2.16 15.255 79.92 15.39 ;
     RECT  2.16 15.39 14.85 15.525 ;
     RECT  15.282 15.39 79.92 15.525 ;
     RECT  2.16 15.795 79.92 16.065 ;
     RECT  2.16 16.335 12.366 16.47 ;
     RECT  12.798 16.335 79.92 16.47 ;
     RECT  2.16 16.47 24.246 16.605 ;
     RECT  24.57 16.47 79.92 16.605 ;
     RECT  2.16 16.875 79.92 17.145 ;
     RECT  2.16 17.415 79.92 17.55 ;
     RECT  2.16 17.55 12.582 17.685 ;
     RECT  12.852 17.55 79.92 17.685 ;
     RECT  2.16 17.955 79.92 18.225 ;
     RECT  2.16 18.495 79.92 18.63 ;
     RECT  2.16 18.63 52.866 18.765 ;
     RECT  53.244 18.63 79.92 18.765 ;
     RECT  2.16 19.035 79.92 19.17 ;
     RECT  2.16 19.17 28.782 19.305 ;
     RECT  29.214 19.17 79.92 19.305 ;
     RECT  2.16 19.575 55.62 19.71 ;
     RECT  56.052 19.575 79.92 19.71 ;
     RECT  2.16 19.71 79.92 19.845 ;
     RECT  2.16 20.115 54.81 20.25 ;
     RECT  55.296 20.115 55.728 20.25 ;
     RECT  56.16 20.115 79.92 20.25 ;
     RECT  2.16 20.25 54.54 20.385 ;
     RECT  55.026 20.25 55.566 20.385 ;
     RECT  55.89 20.25 56.268 20.385 ;
     RECT  56.808 20.25 79.92 20.385 ;
     RECT  2.16 20.655 54.324 20.79 ;
     RECT  54.81 20.655 79.92 20.79 ;
     RECT  2.16 20.79 49.356 20.925 ;
     RECT  50.22 20.79 54.324 20.925 ;
     RECT  54.81 20.79 55.242 20.925 ;
     RECT  55.674 20.79 79.92 20.925 ;
     RECT  2.16 21.195 56.322 21.33 ;
     RECT  57.078 21.195 79.92 21.33 ;
     RECT  2.16 21.33 79.92 21.465 ;
     RECT  2.16 21.735 56.538 21.87 ;
     RECT  2.16 21.87 25.164 22.005 ;
     RECT  25.488 21.87 54.702 22.005 ;
     RECT  55.026 21.87 55.35 22.005 ;
     RECT  55.782 21.87 56.43 22.005 ;
     RECT  56.97 21.735 79.92 22.005 ;
     RECT  2.16 22.275 79.92 22.545 ;
     RECT  2.16 22.815 79.92 23.085 ;
     RECT  2.16 23.355 35.1 23.49 ;
     RECT  35.424 23.355 79.92 23.49 ;
     RECT  2.16 23.49 34.83 23.625 ;
     RECT  35.478 23.49 79.92 23.625 ;
     RECT  2.16 23.895 79.92 24.165 ;
     RECT  2.16 24.435 79.92 24.705 ;
     RECT  2.16 24.975 79.92 25.11 ;
     RECT  2.16 25.11 20.088 25.245 ;
     RECT  20.628 25.11 79.92 25.245 ;
     RECT  2.16 25.515 79.92 25.785 ;
     RECT  2.16 26.055 79.92 26.19 ;
     RECT  2.16 26.19 53.946 26.325 ;
     RECT  54.486 26.19 79.92 26.325 ;
     RECT  2.16 26.595 79.92 26.865 ;
     RECT  2.16 27.135 56.7 27.27 ;
     RECT  57.456 27.135 79.92 27.27 ;
     RECT  2.16 27.27 79.92 27.405 ;
     RECT  2.16 27.675 21.006 27.81 ;
     RECT  21.276 27.675 79.92 27.81 ;
     RECT  2.16 27.81 21.222 27.945 ;
     RECT  21.654 27.81 79.92 27.945 ;
     RECT  2.16 28.215 79.92 28.485 ;
     RECT  2.16 28.755 79.92 29.025 ;
     RECT  2.16 29.295 58.482 29.43 ;
     RECT  58.806 29.295 59.562 29.43 ;
     RECT  59.724 29.295 79.92 29.43 ;
     RECT  2.16 29.43 79.92 29.565 ;
     RECT  2.16 29.835 79.92 30.105 ;
     RECT  2.16 30.375 79.92 30.645 ;
     RECT  2.16 30.915 28.566 31.05 ;
     RECT  29.214 30.915 79.92 31.05 ;
     RECT  2.16 31.05 29.754 31.185 ;
     RECT  30.294 31.05 79.92 31.185 ;
     RECT  2.16 31.455 79.92 31.725 ;
     RECT  2.16 31.995 79.92 32.265 ;
     RECT  2.16 32.535 79.92 32.805 ;
     RECT  2.16 33.075 79.92 33.345 ;
     RECT  2.16 33.615 45.63 33.75 ;
     RECT  45.954 33.615 49.41 33.75 ;
     RECT  49.95 33.615 79.92 33.75 ;
     RECT  2.16 33.75 79.92 33.885 ;
     RECT  2.16 34.155 57.672 34.29 ;
     RECT  57.996 34.155 79.92 34.29 ;
     RECT  2.16 34.29 79.92 34.425 ;
     RECT  2.16 34.695 79.92 34.965 ;
     RECT  2.16 35.235 79.92 35.505 ;
     RECT  2.16 35.775 79.92 36.045 ;
     RECT  2.16 36.315 38.178 36.45 ;
     RECT  38.718 36.315 79.92 36.45 ;
     RECT  2.16 36.45 75.492 36.585 ;
     RECT  76.032 36.45 79.92 36.585 ;
     RECT  2.16 36.855 79.92 37.125 ;
     RECT  2.16 37.395 79.92 37.665 ;
     RECT  2.16 37.935 79.92 38.205 ;
     RECT  2.16 38.475 79.92 38.745 ;
     RECT  2.16 39.015 79.92 39.285 ;
     RECT  2.16 39.555 79.92 39.825 ;
     RECT  2.16 40.095 79.92 40.365 ;
     RECT  2.16 40.635 79.92 40.905 ;
     RECT  2.16 41.175 79.92 41.445 ;
     RECT  2.16 41.715 79.92 41.985 ;
     RECT  2.16 42.255 79.92 42.525 ;
     RECT  2.16 42.795 68.526 42.93 ;
     RECT  69.066 42.795 79.92 42.93 ;
     RECT  2.16 42.93 68.31 43.065 ;
     RECT  69.714 42.93 79.92 43.065 ;
     RECT  2.16 43.335 37.8 43.47 ;
     RECT  38.124 43.335 68.58 43.47 ;
     RECT  68.85 43.335 79.92 43.47 ;
     RECT  2.16 43.47 36.666 43.605 ;
     RECT  36.99 43.47 79.92 43.605 ;
     RECT  2.16 43.875 68.472 44.01 ;
     RECT  68.904 43.875 79.92 44.01 ;
     RECT  2.16 44.01 66.042 44.145 ;
     RECT  67.446 44.01 79.92 44.145 ;
     RECT  2.16 44.415 66.96 44.55 ;
     RECT  67.338 44.415 79.92 44.55 ;
     RECT  2.16 44.55 37.368 44.685 ;
     RECT  38.124 44.55 79.92 44.685 ;
     RECT  2.16 44.955 35.37 45.09 ;
     RECT  35.694 44.955 37.908 45.09 ;
     RECT  38.232 44.955 79.92 45.09 ;
     RECT  2.16 45.09 79.92 45.225 ;
     RECT  2.16 45.495 79.92 45.765 ;
     RECT  2.16 46.035 79.92 46.305 ;
     RECT  2.16 46.575 79.92 46.845 ;
     RECT  2.16 47.115 37.8 47.25 ;
     RECT  38.88 47.115 79.92 47.25 ;
     RECT  2.16 47.25 79.92 47.385 ;
     RECT  2.16 47.655 79.92 47.925 ;
     RECT  2.16 48.195 79.92 48.465 ;
     RECT  2.16 48.735 79.92 49.005 ;
     RECT  2.16 49.275 79.92 49.545 ;
     RECT  2.16 49.815 79.92 50.085 ;
     RECT  2.16 50.355 79.92 50.625 ;
     RECT  2.16 50.895 79.92 51.165 ;
     RECT  2.16 51.435 79.92 51.705 ;
     RECT  2.16 51.975 79.92 52.245 ;
     RECT  2.16 52.515 79.92 52.785 ;
     RECT  2.16 53.055 79.92 53.325 ;
     RECT  2.16 53.595 79.92 53.865 ;
     RECT  2.16 54.135 79.92 54.405 ;
     RECT  2.16 54.675 79.92 54.945 ;
     RECT  2.16 55.215 79.92 55.485 ;
     RECT  2.16 55.755 79.92 56.025 ;
     RECT  2.16 56.295 79.92 56.565 ;
     RECT  2.16 56.835 79.92 57.105 ;
     RECT  2.16 57.375 79.92 57.645 ;
     RECT  2.16 57.915 79.92 58.185 ;
     RECT  2.16 58.455 79.92 58.725 ;
     RECT  2.16 58.995 79.92 59.265 ;
     RECT  2.16 59.535 79.92 59.805 ;
     RECT  2.16 60.075 79.92 60.345 ;
     RECT  2.16 60.615 79.92 60.885 ;
     RECT  2.16 61.155 15.606 61.29 ;
     RECT  16.146 61.155 79.92 61.29 ;
     RECT  2.16 61.29 79.92 61.425 ;
     RECT  2.16 61.695 79.92 61.965 ;
     RECT  2.16 62.235 79.92 62.505 ;
     RECT  2.16 62.775 79.92 63.045 ;
     RECT  2.16 63.315 79.92 63.585 ;
     RECT  2.16 63.855 79.92 64.125 ;
     RECT  2.16 64.395 79.92 64.665 ;
     RECT  2.16 64.935 79.92 65.205 ;
     RECT  2.16 65.475 79.92 65.745 ;
     RECT  2.16 66.015 79.92 66.285 ;
     RECT  2.16 66.555 79.92 66.825 ;
     RECT  2.16 67.095 79.92 67.365 ;
     RECT  2.16 67.635 74.25 67.77 ;
     RECT  75.654 67.635 79.92 67.77 ;
     RECT  2.16 67.77 79.92 67.905 ;
     RECT  2.16 68.175 79.92 68.445 ;
     RECT  2.16 68.715 37.368 68.85 ;
     RECT  38.448 68.715 79.92 68.85 ;
     RECT  2.16 68.85 79.92 68.985 ;
     RECT  2.16 69.255 79.92 69.39 ;
     RECT  2.16 69.39 13.608 69.525 ;
     RECT  14.04 69.39 79.92 69.525 ;
     RECT  2.16 69.795 53.73 69.93 ;
     RECT  54.108 69.795 79.92 69.93 ;
     RECT  2.16 69.93 79.92 70.065 ;
     RECT  2.16 70.335 79.92 70.47 ;
     RECT  2.16 70.47 53.892 70.605 ;
     RECT  54.324 70.47 79.92 70.605 ;
     RECT  2.16 70.875 79.92 71.01 ;
     RECT  2.16 71.01 13.662 71.145 ;
     RECT  13.986 71.01 79.92 71.145 ;
     RECT  2.16 71.415 13.824 71.55 ;
     RECT  14.094 71.415 60.102 71.55 ;
     RECT  60.48 71.415 79.92 71.55 ;
     RECT  2.16 71.55 12.528 71.685 ;
     RECT  13.284 71.55 50.598 71.685 ;
     RECT  50.976 71.55 79.92 71.685 ;
     RECT  2.16 71.955 13.176 72.09 ;
     RECT  13.446 71.955 59.076 72.09 ;
     RECT  59.508 71.955 79.92 72.09 ;
     RECT  2.16 72.09 79.92 72.225 ;
     RECT  2.16 72.495 79.92 72.765 ;
     RECT  2.16 73.035 79.92 73.305 ;
     RECT  2.16 73.575 79.92 73.845 ;
     RECT  2.16 74.115 65.826 74.25 ;
     RECT  67.23 74.115 79.92 74.25 ;
     RECT  2.16 74.25 79.92 74.385 ;
     RECT  2.16 74.655 75.114 74.79 ;
     RECT  76.518 74.655 79.92 74.79 ;
     RECT  2.16 74.79 79.92 74.925 ;
     RECT  2.16 75.195 79.92 75.465 ;
    LAYER M1 ;
     RECT  2.16 2.151 79.92 75.609 ;
    LAYER M2 ;
     RECT  1.327 74.592 1.579 74.61 ;
     RECT  1.111 75.51 1.579 75.528 ;
     RECT  1.579 74.592 1.795 75.528 ;
     RECT  1.687 2.232 2.16 2.25 ;
     RECT  1.795 74.052 2.16 75.528 ;
     RECT  2.371 76.896 2.543 76.914 ;
     RECT  3.415 76.896 3.875 76.914 ;
     RECT  7.843 77.706 7.979 77.724 ;
     RECT  31.747 0.036 31.847 0.054 ;
     RECT  2.16 2.151 32.467 75.609 ;
     RECT  32.467 2.106 33.503 75.609 ;
     RECT  33.503 2.151 34.843 75.609 ;
     RECT  34.843 2.151 35.267 75.69 ;
     RECT  40.171 0.036 40.343 0.054 ;
     RECT  41.755 0.036 41.855 0.054 ;
     RECT  45.787 77.706 45.959 77.724 ;
     RECT  35.267 2.151 46.039 75.609 ;
     RECT  46.039 1.728 46.139 75.609 ;
     RECT  46.139 2.151 48.667 75.609 ;
     RECT  48.667 2.106 49.199 75.609 ;
     RECT  53.131 1.152 53.231 1.17 ;
     RECT  60.691 76.986 60.835 77.004 ;
     RECT  60.835 76.896 60.935 77.076 ;
     RECT  60.935 76.986 60.971 77.076 ;
     RECT  61.879 77.706 61.979 77.724 ;
     RECT  67.135 77.706 67.559 77.724 ;
     RECT  49.199 2.151 73.975 75.609 ;
     RECT  73.975 2.151 75.839 76.104 ;
     RECT  78.403 76.896 79.187 76.914 ;
     RECT  75.839 2.151 79.92 75.609 ;
     RECT  79.92 72 80.051 73.53 ;
     RECT  79.92 70.074 80.267 70.632 ;
     RECT  79.92 2.232 80.375 3.096 ;
     RECT  79.92 8.478 80.375 8.496 ;
     RECT  79.92 9.828 80.375 9.846 ;
     RECT  79.92 32.742 80.375 32.76 ;
     RECT  79.92 35.55 80.375 35.568 ;
     RECT  79.92 40.842 80.375 40.86 ;
     RECT  79.92 47.628 80.375 47.646 ;
     RECT  79.92 42.3 80.411 42.318 ;
     RECT  79.92 67.914 80.411 68.13 ;
     RECT  80.267 70.614 80.411 70.632 ;
     RECT  80.051 72 80.411 72.684 ;
     RECT  79.92 74.358 80.411 75.186 ;
     RECT  80.411 72.666 80.519 72.684 ;
     RECT  79.92 11.25 80.735 11.268 ;
     RECT  80.051 73.512 80.735 73.53 ;
     RECT  79.92 5.85 80.807 5.868 ;
     RECT  80.375 2.538 80.915 3.096 ;
     RECT  79.92 7.128 80.915 7.146 ;
     RECT  79.92 46.35 80.915 46.368 ;
     RECT  79.92 50.868 80.915 50.886 ;
     RECT  80.411 74.358 80.915 75.15 ;
     RECT  79.92 12.528 80.951 12.546 ;
     RECT  79.92 15.462 80.951 15.48 ;
     RECT  79.92 16.812 80.951 16.83 ;
     RECT  79.92 17.892 80.951 17.91 ;
     RECT  79.92 19.512 80.951 19.53 ;
     RECT  79.92 20.592 80.951 20.61 ;
     RECT  79.92 21.942 80.951 21.96 ;
     RECT  79.92 24.678 80.951 24.696 ;
     RECT  79.92 25.992 80.951 26.01 ;
     RECT  79.92 28.692 80.951 28.71 ;
     RECT  79.92 31.392 80.951 31.41 ;
     RECT  79.92 34.128 80.951 34.146 ;
     RECT  79.92 36.792 80.951 36.81 ;
     RECT  79.92 39.492 80.951 39.51 ;
     RECT  79.92 43.542 80.951 43.56 ;
     RECT  79.92 45.162 80.951 45.18 ;
     RECT  79.92 51.912 80.951 51.93 ;
     RECT  79.92 53.262 80.951 53.28 ;
     RECT  79.92 54.612 80.951 54.63 ;
     RECT  79.92 55.692 80.951 55.71 ;
     RECT  79.92 57.312 80.951 57.33 ;
     RECT  79.92 58.464 80.951 58.482 ;
     RECT  79.92 60.012 80.951 60.03 ;
     RECT  79.92 61.632 80.951 61.65 ;
     RECT  79.92 62.442 80.951 62.46 ;
     RECT  79.92 65.142 80.951 65.16 ;
     RECT  80.915 74.862 80.951 75.15 ;
     RECT  79.92 48.816 80.987 48.834 ;
     RECT  80.411 68.112 80.987 68.13 ;
     RECT  80.951 75.132 80.987 75.15 ;
     RECT  79.92 27.342 81.491 27.36 ;
     RECT  79.92 38.178 81.491 38.196 ;
     RECT  79.92 63.792 81.491 63.81 ;
     RECT  79.92 66.798 81.491 66.816 ;
     RECT  79.92 23.256 81.527 23.274 ;
     RECT  80.915 2.538 81.923 2.556 ;
     RECT  79.92 4.392 81.995 4.41 ;
     RECT  79.92 30.312 81.995 30.33 ;
    LAYER M3 ;
     RECT  31.752 0.012 31.77 0.031 ;
     RECT  40.32 0.012 40.338 0.031 ;
     RECT  41.76 0.012 41.778 0.031 ;
     RECT  31.752 0.031 31.842 0.059 ;
     RECT  40.176 0.031 40.338 0.059 ;
     RECT  41.76 0.031 41.85 0.059 ;
     RECT  53.208 0.091 53.226 1.147 ;
     RECT  53.136 1.147 53.226 1.175 ;
     RECT  46.044 0.012 46.062 1.723 ;
     RECT  31.824 0.059 31.842 2.101 ;
     RECT  33.156 0.012 33.174 2.101 ;
     RECT  48.924 1.723 48.942 2.101 ;
     RECT  1.692 0.012 1.71 2.143 ;
     RECT  3.132 0.012 3.15 2.143 ;
     RECT  7.416 0.012 7.434 2.143 ;
     RECT  13.14 0.012 13.158 2.143 ;
     RECT  18.864 0.012 18.882 2.143 ;
     RECT  24.588 0.012 24.606 2.143 ;
     RECT  28.872 0.012 28.89 2.143 ;
     RECT  34.596 0.012 34.614 2.143 ;
     RECT  40.176 0.059 40.194 2.143 ;
     RECT  46.044 1.723 46.134 2.143 ;
     RECT  50.436 1.723 50.454 2.143 ;
     RECT  55.944 0.571 55.962 2.143 ;
     RECT  61.776 1.723 61.794 2.143 ;
     RECT  67.572 0.091 67.59 2.143 ;
     RECT  72.972 1.723 72.99 2.143 ;
     RECT  78.696 1.723 78.714 2.143 ;
     RECT  4.572 0.012 4.59 2.191 ;
     RECT  6.012 0.012 6.03 2.191 ;
     RECT  10.296 0.012 10.314 2.191 ;
     RECT  13.14 2.143 13.305 2.191 ;
     RECT  14.58 0.012 14.598 2.191 ;
     RECT  17.424 0.012 17.442 2.191 ;
     RECT  20.304 0.012 20.322 2.191 ;
     RECT  21.744 0.012 21.762 2.191 ;
     RECT  23.148 0.012 23.166 2.191 ;
     RECT  24.015 2.143 24.606 2.191 ;
     RECT  28.872 2.143 29.505 2.191 ;
     RECT  30.312 0.012 30.33 2.191 ;
     RECT  31.824 2.101 33.498 2.191 ;
     RECT  34.596 2.143 34.905 2.191 ;
     RECT  37.44 0.012 37.458 2.191 ;
     RECT  38.88 0.012 38.898 2.191 ;
     RECT  40.176 2.143 40.305 2.191 ;
     RECT  41.832 0.059 41.85 2.191 ;
     RECT  43.164 0.012 43.182 2.191 ;
     RECT  45.615 2.143 46.134 2.191 ;
     RECT  48.672 2.101 49.194 2.191 ;
     RECT  50.436 2.143 51.105 2.191 ;
     RECT  54.648 1.723 54.666 2.191 ;
     RECT  55.944 2.143 56.505 2.191 ;
     RECT  59.148 1.723 59.166 2.191 ;
     RECT  60.336 1.723 60.354 2.191 ;
     RECT  66.06 0.091 66.078 2.191 ;
     RECT  68.724 1.723 68.742 2.191 ;
     RECT  16.02 0.012 16.038 2.227 ;
     RECT  43.164 2.191 43.542 2.227 ;
     RECT  44.604 0.012 44.622 2.227 ;
     RECT  1.692 2.143 3.15 2.255 ;
     RECT  74.376 1.723 74.394 2.255 ;
     RECT  75.852 1.723 75.87 2.255 ;
     RECT  77.256 1.723 77.274 2.255 ;
     RECT  80.352 0.571 80.37 2.255 ;
     RECT  6.012 2.191 6.102 2.263 ;
     RECT  10.08 2.191 10.314 2.263 ;
     RECT  14.58 2.191 15.03 2.263 ;
     RECT  15.912 2.227 16.038 2.263 ;
     RECT  20.304 2.191 20.646 2.263 ;
     RECT  21.744 2.191 22.338 2.263 ;
     RECT  34.272 2.191 34.905 2.263 ;
     RECT  36.036 0.012 36.054 2.263 ;
     RECT  37.404 2.191 37.458 2.263 ;
     RECT  43.164 2.227 44.622 2.263 ;
     RECT  45.36 2.191 46.134 2.263 ;
     RECT  47.844 1.723 47.862 2.263 ;
     RECT  48.672 2.191 49.374 2.263 ;
     RECT  50.112 2.191 51.105 2.263 ;
     RECT  51.84 1.723 51.858 2.263 ;
     RECT  53.136 1.175 53.154 2.263 ;
     RECT  54.648 2.191 56.505 2.263 ;
     RECT  57.492 1.723 57.51 2.263 ;
     RECT  63.252 1.723 63.27 2.263 ;
     RECT  67.215 2.143 67.59 2.263 ;
     RECT  68.4 2.191 69.354 2.263 ;
     RECT  70.2 0.571 70.218 2.263 ;
     RECT  71.532 1.723 71.55 2.263 ;
     RECT  8.856 0.012 8.874 2.299 ;
     RECT  18.615 2.143 18.882 2.299 ;
     RECT  26.028 0.012 26.046 2.299 ;
     RECT  48.672 2.263 51.105 2.299 ;
     RECT  51.84 2.263 53.154 2.299 ;
     RECT  54.648 2.263 57.51 2.299 ;
     RECT  63.252 2.263 63.558 2.299 ;
     RECT  64.62 0.091 64.638 2.299 ;
     RECT  17.172 2.191 17.442 2.335 ;
     RECT  26.028 2.299 26.19 2.335 ;
     RECT  70.2 2.263 71.55 2.335 ;
     RECT  3.996 2.191 4.59 2.371 ;
     RECT  6.012 2.263 6.354 2.371 ;
     RECT  7.416 2.143 7.905 2.371 ;
     RECT  8.856 2.299 8.946 2.371 ;
     RECT  9.684 2.263 10.35 2.371 ;
     RECT  11.7 0.012 11.718 2.371 ;
     RECT  14.22 2.263 16.038 2.371 ;
     RECT  17.172 2.335 17.658 2.371 ;
     RECT  18.615 2.299 18.99 2.371 ;
     RECT  20.304 2.263 22.338 2.371 ;
     RECT  25.812 2.335 26.19 2.371 ;
     RECT  27.432 0.012 27.45 2.371 ;
     RECT  28.584 2.191 29.505 2.371 ;
     RECT  38.376 2.191 38.898 2.371 ;
     RECT  40.176 2.191 41.85 2.371 ;
     RECT  43.164 2.263 46.134 2.371 ;
     RECT  47.268 2.263 47.862 2.371 ;
     RECT  48.672 2.299 57.51 2.371 ;
     RECT  60.084 2.191 60.39 2.371 ;
     RECT  61.776 2.143 61.905 2.371 ;
     RECT  63.252 2.299 64.638 2.371 ;
     RECT  65.376 2.191 66.33 2.371 ;
     RECT  70.128 2.335 71.55 2.371 ;
     RECT  72.615 2.143 72.99 2.371 ;
     RECT  78.015 2.143 78.714 2.371 ;
     RECT  12.564 2.191 13.305 2.413 ;
     RECT  14.112 2.371 16.038 2.413 ;
     RECT  27.432 2.371 29.505 2.413 ;
     RECT  30.312 2.191 30.582 2.413 ;
     RECT  38.376 2.371 39.402 2.461 ;
     RECT  40.176 2.371 41.958 2.461 ;
     RECT  2.304 2.255 3.15 2.489 ;
     RECT  3.996 2.371 6.354 2.489 ;
     RECT  7.416 2.371 10.35 2.489 ;
     RECT  58.536 2.191 59.166 2.533 ;
     RECT  60.084 2.371 62.514 2.533 ;
     RECT  81.9 1.675 81.918 2.561 ;
     RECT  38.376 2.461 41.958 2.569 ;
     RECT  43.164 2.371 57.51 2.569 ;
     RECT  67.215 2.263 69.354 2.569 ;
     RECT  70.128 2.371 71.694 2.569 ;
     RECT  12.564 2.413 16.038 2.605 ;
     RECT  27.432 2.413 30.582 2.605 ;
     RECT  38.376 2.569 57.51 2.605 ;
     RECT  58.536 2.533 62.514 2.605 ;
     RECT  67.215 2.569 71.694 2.605 ;
     RECT  72.615 2.371 73.17 2.605 ;
     RECT  11.664 2.371 11.718 2.641 ;
     RECT  17.172 2.371 22.338 2.641 ;
     RECT  23.148 2.191 24.822 2.641 ;
     RECT  25.668 2.371 26.514 2.641 ;
     RECT  27.252 2.605 30.582 2.641 ;
     RECT  38.376 2.605 62.514 2.641 ;
     RECT  67.215 2.605 73.17 2.641 ;
     RECT  3.996 2.489 4.59 2.759 ;
     RECT  5.328 2.489 6.354 2.759 ;
     RECT  11.196 2.641 11.718 2.759 ;
     RECT  77.4 2.371 79.326 2.803 ;
     RECT  17.172 2.641 24.822 2.827 ;
     RECT  38.304 2.641 62.514 2.831 ;
     RECT  8.82 2.489 10.35 2.839 ;
     RECT  75.96 2.371 76.302 2.839 ;
     RECT  12.564 2.605 16.182 2.875 ;
     RECT  17.028 2.827 24.822 2.875 ;
     RECT  25.668 2.641 30.582 2.875 ;
     RECT  34.272 2.263 37.458 2.875 ;
     RECT  38.304 2.831 54.486 2.875 ;
     RECT  55.224 2.831 62.514 2.875 ;
     RECT  63.252 2.371 66.33 2.875 ;
     RECT  67.215 2.641 73.206 2.875 ;
     RECT  55.224 2.875 73.206 2.903 ;
     RECT  77.4 2.803 79.686 2.909 ;
     RECT  31.32 2.191 33.498 2.911 ;
     RECT  34.272 2.875 54.486 2.911 ;
     RECT  12.564 2.875 30.582 3.001 ;
     RECT  31.32 2.911 54.486 3.001 ;
     RECT  75.96 2.839 76.374 3.001 ;
     RECT  75.816 3.001 76.374 3.037 ;
     RECT  80.892 3.019 80.91 3.101 ;
     RECT  2.415 2.489 3.15 3.115 ;
     RECT  3.996 2.759 4.41 3.115 ;
     RECT  72.615 2.903 73.206 3.145 ;
     RECT  11.808 3.145 11.826 3.181 ;
     RECT  12.564 3.001 54.486 3.181 ;
     RECT  75.816 3.037 76.626 3.181 ;
     RECT  72.615 3.145 73.35 3.299 ;
     RECT  72.615 3.299 73.206 3.335 ;
     RECT  77.688 2.909 79.686 3.335 ;
     RECT  2.415 3.115 4.41 3.379 ;
     RECT  7.416 2.489 8.097 3.379 ;
     RECT  8.82 2.839 10.854 3.379 ;
     RECT  2.34 3.379 4.41 3.437 ;
     RECT  74.916 2.371 74.934 3.451 ;
     RECT  7.416 3.379 10.854 3.569 ;
     RECT  5.328 2.759 5.346 3.613 ;
     RECT  6.336 2.759 6.354 3.613 ;
     RECT  7.416 3.569 8.154 3.613 ;
     RECT  8.928 3.569 10.854 3.613 ;
     RECT  11.808 3.181 54.486 3.613 ;
     RECT  2.415 3.437 4.41 3.649 ;
     RECT  5.22 3.613 5.346 3.649 ;
     RECT  6.336 3.613 8.154 3.649 ;
     RECT  55.224 2.903 71.874 3.685 ;
     RECT  72.615 3.335 72.897 3.685 ;
     RECT  75.816 3.181 76.95 3.721 ;
     RECT  77.724 3.335 79.686 3.721 ;
     RECT  2.415 3.649 8.154 3.839 ;
     RECT  8.928 3.613 54.486 3.847 ;
     RECT  55.224 3.685 72.897 3.847 ;
     RECT  74.88 3.451 74.934 3.847 ;
     RECT  75.708 3.721 76.986 3.847 ;
     RECT  2.415 3.839 8.097 3.875 ;
     RECT  74.88 3.847 76.986 3.931 ;
     RECT  4.68 3.875 8.097 3.947 ;
     RECT  77.724 3.721 79.794 3.947 ;
     RECT  2.415 3.875 3.942 3.965 ;
     RECT  4.68 3.947 4.698 3.983 ;
     RECT  8.928 3.847 72.897 4.081 ;
     RECT  5.472 3.947 8.097 4.109 ;
     RECT  74.7 3.931 76.986 4.157 ;
     RECT  77.724 3.947 79.686 4.181 ;
     RECT  75.852 4.157 76.986 4.261 ;
     RECT  77.724 4.181 79.506 4.261 ;
     RECT  74.7 4.157 75.042 4.351 ;
     RECT  75.852 4.261 79.506 4.379 ;
     RECT  5.724 4.109 6.966 4.415 ;
     RECT  76.14 4.379 78.297 4.415 ;
     RECT  81.972 4.363 81.99 4.415 ;
     RECT  74.664 4.351 75.042 4.487 ;
     RECT  8.928 4.081 72.99 4.507 ;
     RECT  7.815 4.109 8.097 4.693 ;
     RECT  8.928 4.507 73.458 4.693 ;
     RECT  76.248 4.415 78.297 4.793 ;
     RECT  5.724 4.415 6.318 5.189 ;
     RECT  7.815 4.693 73.458 5.305 ;
     RECT  7.815 5.305 73.926 5.431 ;
     RECT  75.024 4.487 75.042 5.431 ;
     RECT  76.248 4.793 76.986 5.459 ;
     RECT  76.248 5.459 76.806 5.773 ;
     RECT  80.784 5.707 80.802 5.873 ;
     RECT  79.2 4.379 79.506 5.881 ;
     RECT  79.2 5.881 79.722 5.999 ;
     RECT  7.815 5.431 75.042 6.007 ;
     RECT  76.068 5.773 76.806 6.007 ;
     RECT  78.015 4.793 78.297 6.151 ;
     RECT  79.2 5.999 79.506 6.151 ;
     RECT  7.815 6.007 76.806 6.232 ;
     RECT  78.015 6.151 79.506 6.232 ;
     RECT  3.924 3.965 3.942 6.283 ;
     RECT  3.924 6.283 3.978 6.781 ;
     RECT  3.924 6.781 4.302 7.079 ;
     RECT  80.892 7.051 80.91 7.151 ;
     RECT  7.815 6.232 79.506 7.735 ;
     RECT  5.796 5.189 6.318 8.311 ;
     RECT  7.092 7.735 79.506 8.311 ;
     RECT  80.352 8.443 80.37 8.501 ;
     RECT  2.415 3.965 3.042 8.539 ;
     RECT  2.304 8.539 3.042 8.545 ;
     RECT  3.924 7.079 3.942 8.545 ;
     RECT  2.304 8.545 3.942 8.735 ;
     RECT  2.415 8.735 3.942 8.815 ;
     RECT  2.415 8.815 4.122 8.851 ;
     RECT  2.415 8.851 4.59 8.969 ;
     RECT  4.572 8.969 4.59 9.275 ;
     RECT  5.796 8.311 79.506 9.391 ;
     RECT  5.652 9.391 79.506 9.643 ;
     RECT  5.616 9.643 79.506 9.661 ;
     RECT  5.616 9.661 79.794 9.787 ;
     RECT  5.616 9.787 80.37 9.851 ;
     RECT  4.824 9.895 4.842 9.931 ;
     RECT  5.616 9.851 79.794 9.931 ;
     RECT  4.824 9.931 79.794 10.027 ;
     RECT  4.716 10.027 79.794 10.229 ;
     RECT  4.716 10.229 79.506 10.597 ;
     RECT  80.712 11.131 80.73 11.273 ;
     RECT  4.572 10.597 79.506 11.407 ;
     RECT  2.415 8.969 3.762 11.551 ;
     RECT  4.536 11.407 79.506 11.551 ;
     RECT  2.415 11.551 79.506 12.181 ;
     RECT  2.415 12.181 79.794 12.479 ;
     RECT  80.928 12.475 80.946 12.551 ;
     RECT  2.415 12.479 79.506 13.819 ;
     RECT  2.415 13.819 79.794 14.207 ;
     RECT  2.415 14.207 79.506 14.909 ;
     RECT  80.928 15.211 80.946 15.485 ;
     RECT  2.415 14.909 3.042 16.141 ;
     RECT  3.816 14.909 79.506 16.141 ;
     RECT  2.415 16.141 79.578 16.331 ;
     RECT  80.928 16.555 80.946 16.835 ;
     RECT  80.928 17.887 80.946 17.933 ;
     RECT  2.415 16.331 79.506 18.221 ;
     RECT  2.415 18.221 3.042 19.111 ;
     RECT  3.816 18.221 79.506 19.111 ;
     RECT  2.415 19.111 79.506 19.309 ;
     RECT  2.34 19.309 79.506 19.373 ;
     RECT  80.928 19.243 80.946 19.535 ;
     RECT  2.415 19.373 79.506 20.587 ;
     RECT  80.928 20.587 80.946 20.624 ;
     RECT  2.34 20.587 79.506 20.651 ;
     RECT  2.415 20.651 79.506 20.731 ;
     RECT  2.415 20.731 79.614 20.849 ;
     RECT  2.415 20.849 79.578 21.775 ;
     RECT  2.376 21.775 79.578 21.929 ;
     RECT  80.928 21.928 80.946 21.965 ;
     RECT  2.415 21.929 79.578 23.089 ;
     RECT  2.34 23.089 79.578 23.161 ;
     RECT  2.34 23.161 79.722 23.351 ;
     RECT  81.504 23.251 81.522 23.357 ;
     RECT  2.34 23.351 79.578 23.707 ;
     RECT  2.304 23.707 79.578 23.855 ;
     RECT  80.928 24.664 80.946 24.701 ;
     RECT  2.376 23.855 79.578 25.079 ;
     RECT  2.376 25.079 79.506 25.745 ;
     RECT  80.928 25.987 80.946 26.045 ;
     RECT  2.415 25.745 79.506 26.365 ;
     RECT  2.415 26.365 79.686 26.519 ;
     RECT  2.415 26.519 79.506 27.175 ;
     RECT  81.468 27.337 81.486 27.389 ;
     RECT  80.928 28.687 80.946 28.733 ;
     RECT  2.376 27.175 79.506 29.291 ;
     RECT  2.412 29.291 79.506 29.911 ;
     RECT  2.412 29.911 79.794 30.037 ;
     RECT  2.376 30.037 79.794 30.173 ;
     RECT  81.972 30.091 81.99 30.335 ;
     RECT  2.376 30.173 79.614 31.189 ;
     RECT  2.376 31.189 79.794 31.451 ;
     RECT  80.928 31.387 80.946 31.469 ;
     RECT  2.415 31.451 79.794 32.189 ;
     RECT  80.352 32.737 80.37 32.813 ;
     RECT  2.415 32.189 79.506 33.151 ;
     RECT  80.928 34.123 80.946 34.16 ;
     RECT  2.376 33.151 79.506 34.591 ;
     RECT  2.376 34.591 79.794 34.889 ;
     RECT  2.376 34.889 79.506 35.429 ;
     RECT  80.352 35.467 80.37 35.573 ;
     RECT  2.415 35.429 79.506 36.589 ;
     RECT  80.928 36.787 80.946 36.845 ;
     RECT  2.34 36.589 79.506 38.155 ;
     RECT  2.34 38.155 79.65 38.173 ;
     RECT  81.468 38.173 81.486 38.237 ;
     RECT  2.34 38.173 79.866 38.273 ;
     RECT  2.34 38.273 79.506 38.579 ;
     RECT  2.34 38.579 79.218 38.875 ;
     RECT  2.304 38.875 79.218 39.209 ;
     RECT  2.304 39.209 2.697 39.245 ;
     RECT  3.492 39.209 79.218 39.281 ;
     RECT  80.928 39.487 80.946 39.581 ;
     RECT  3.816 39.281 79.218 40.441 ;
     RECT  3.564 40.441 79.218 40.469 ;
     RECT  80.352 40.837 80.37 40.925 ;
     RECT  3.564 40.469 6.174 41.485 ;
     RECT  6.984 40.469 79.218 41.485 ;
     RECT  3.564 41.485 79.218 41.521 ;
     RECT  2.415 39.245 2.697 41.605 ;
     RECT  3.492 41.521 79.218 41.605 ;
     RECT  2.415 41.605 79.218 41.881 ;
     RECT  2.415 41.881 79.722 42.179 ;
     RECT  80.388 42.235 80.406 42.323 ;
     RECT  2.415 42.179 79.29 43.141 ;
     RECT  2.376 43.141 79.29 43.411 ;
     RECT  80.928 43.537 80.946 43.613 ;
     RECT  2.376 43.411 79.578 43.709 ;
     RECT  2.376 43.709 31.266 43.799 ;
     RECT  32.112 43.709 79.578 43.871 ;
     RECT  32.112 43.871 79.254 44.237 ;
     RECT  32.112 44.237 71.694 44.455 ;
     RECT  32.04 44.455 71.694 44.689 ;
     RECT  2.376 43.799 31.086 44.879 ;
     RECT  72.432 44.237 79.254 44.959 ;
     RECT  32.004 44.689 71.694 44.995 ;
     RECT  72.432 44.959 79.29 44.995 ;
     RECT  32.004 44.995 79.29 45.149 ;
     RECT  80.928 44.971 80.946 45.185 ;
     RECT  2.415 44.879 31.086 45.403 ;
     RECT  2.415 45.403 31.122 45.451 ;
     RECT  32.004 45.149 49.518 45.451 ;
     RECT  2.415 45.451 49.518 45.761 ;
     RECT  50.328 45.149 79.29 45.931 ;
     RECT  50.292 45.931 79.29 46.003 ;
     RECT  2.415 45.761 48.942 46.111 ;
     RECT  80.892 46.315 80.91 46.373 ;
     RECT  2.376 46.111 48.942 46.579 ;
     RECT  2.376 46.579 49.014 46.741 ;
     RECT  49.752 46.003 79.29 46.741 ;
     RECT  2.376 46.741 79.29 46.769 ;
     RECT  80.352 47.623 80.37 47.693 ;
     RECT  2.415 46.769 79.29 47.731 ;
     RECT  2.376 47.731 79.29 48.811 ;
     RECT  2.376 48.811 79.578 48.901 ;
     RECT  2.376 48.901 79.65 48.941 ;
     RECT  2.376 48.941 79.578 48.965 ;
     RECT  2.376 48.965 79.434 49.001 ;
     RECT  80.964 48.811 80.982 49.037 ;
     RECT  2.376 49.001 79.29 49.747 ;
     RECT  2.304 49.747 79.29 50.161 ;
     RECT  2.304 50.161 79.47 50.521 ;
     RECT  2.304 50.521 79.794 50.819 ;
     RECT  2.304 50.819 79.506 50.855 ;
     RECT  80.892 50.347 80.91 50.891 ;
     RECT  2.304 50.855 79.47 50.927 ;
     RECT  80.928 51.739 80.946 51.935 ;
     RECT  2.304 50.927 79.29 52.249 ;
     RECT  2.304 52.249 79.434 52.591 ;
     RECT  2.304 52.591 79.794 52.853 ;
     RECT  80.928 53.083 80.946 53.285 ;
     RECT  2.304 52.853 79.29 54.131 ;
     RECT  80.928 54.427 80.946 54.635 ;
     RECT  2.376 54.131 79.29 54.701 ;
     RECT  2.415 54.701 79.29 55.291 ;
     RECT  2.415 55.291 79.434 55.381 ;
     RECT  2.415 55.381 79.542 55.481 ;
     RECT  80.928 55.687 80.946 55.805 ;
     RECT  2.415 55.481 79.434 56.021 ;
     RECT  2.415 56.021 79.362 56.059 ;
     RECT  2.34 56.059 79.362 56.255 ;
     RECT  80.928 57.115 80.946 57.335 ;
     RECT  2.415 56.255 79.362 57.451 ;
     RECT  2.415 57.451 79.434 57.541 ;
     RECT  80.928 58.459 80.946 58.496 ;
     RECT  2.415 57.541 79.506 58.531 ;
     RECT  2.415 58.531 79.794 58.649 ;
     RECT  2.415 58.649 79.65 59.611 ;
     RECT  80.928 59.851 80.946 60.035 ;
     RECT  2.415 59.611 79.794 60.269 ;
     RECT  2.415 60.269 79.29 60.691 ;
     RECT  80.928 61.195 80.946 61.655 ;
     RECT  80.928 62.437 80.946 62.573 ;
     RECT  2.376 60.691 79.29 62.699 ;
     RECT  2.376 62.699 79.218 63.895 ;
     RECT  81.468 63.787 81.486 63.917 ;
     RECT  2.376 63.895 79.29 63.931 ;
     RECT  2.376 63.931 79.434 64.049 ;
     RECT  2.376 64.049 79.254 64.363 ;
     RECT  80.928 65.137 80.946 65.261 ;
     RECT  2.304 64.363 79.254 65.399 ;
     RECT  2.304 65.399 79.218 66.631 ;
     RECT  81.468 66.619 81.486 66.821 ;
     RECT  2.304 66.631 79.254 67.171 ;
     RECT  2.304 67.171 79.47 67.441 ;
     RECT  80.388 67.909 80.406 67.997 ;
     RECT  2.304 67.441 79.506 68.251 ;
     RECT  2.304 68.251 79.614 68.485 ;
     RECT  2.304 68.485 79.686 68.791 ;
     RECT  2.304 68.791 79.794 69.163 ;
     RECT  80.964 68.107 80.982 69.341 ;
     RECT  2.268 69.163 79.794 69.485 ;
     RECT  2.304 69.485 79.794 70.069 ;
     RECT  2.304 70.069 80.262 70.529 ;
     RECT  2.34 70.529 80.262 70.609 ;
     RECT  2.34 70.609 80.406 70.685 ;
     RECT  2.34 70.685 80.262 71.491 ;
     RECT  2.304 71.491 80.262 71.989 ;
     RECT  2.304 71.989 80.406 72.661 ;
     RECT  2.304 72.661 80.514 72.931 ;
     RECT  2.232 72.931 80.514 73.339 ;
     RECT  2.232 73.339 80.91 74.047 ;
     RECT  1.8 74.047 80.91 74.587 ;
     RECT  1.332 74.587 80.91 74.731 ;
     RECT  1.332 74.731 80.946 75.127 ;
     RECT  1.332 75.127 80.982 75.389 ;
     RECT  68.724 75.389 80.982 75.461 ;
     RECT  1.332 75.389 10.53 75.505 ;
     RECT  1.116 75.505 10.53 75.533 ;
     RECT  9.54 75.533 10.53 75.569 ;
     RECT  11.376 75.389 15.174 75.569 ;
     RECT  15.912 75.389 40.77 75.569 ;
     RECT  55.764 75.389 58.662 75.569 ;
     RECT  74.916 75.461 80.982 75.569 ;
     RECT  54.504 75.389 54.594 75.581 ;
     RECT  59.796 75.389 67.95 75.581 ;
     RECT  24.015 75.569 40.698 75.617 ;
     RECT  56.415 75.569 58.158 75.617 ;
     RECT  77.94 75.569 80.982 75.617 ;
     RECT  24.156 75.617 40.698 75.725 ;
     RECT  69.192 75.461 74.142 75.725 ;
     RECT  11.376 75.569 15.102 75.773 ;
     RECT  56.736 75.617 58.158 75.773 ;
     RECT  1.116 75.533 8.586 75.821 ;
     RECT  9.54 75.569 10.098 75.821 ;
     RECT  11.376 75.773 13.374 75.821 ;
     RECT  14.184 75.773 15.102 75.821 ;
     RECT  15.912 75.569 23.274 75.821 ;
     RECT  24.156 75.725 40.662 75.821 ;
     RECT  41.616 75.389 44.334 75.821 ;
     RECT  45.396 75.389 52.794 75.821 ;
     RECT  54.576 75.581 54.594 75.821 ;
     RECT  56.772 75.773 58.158 75.821 ;
     RECT  59.796 75.581 59.814 75.821 ;
     RECT  69.192 75.725 72.522 75.821 ;
     RECT  73.296 75.725 74.142 75.821 ;
     RECT  74.916 75.569 77.202 75.821 ;
     RECT  73.98 75.821 73.998 76.109 ;
     RECT  77.94 75.617 77.958 76.363 ;
     RECT  78.768 75.617 80.982 76.363 ;
     RECT  14.76 75.821 14.778 76.397 ;
     RECT  56.772 75.821 57.438 76.397 ;
     RECT  70.56 75.821 70.578 76.397 ;
     RECT  60.912 75.581 67.95 76.891 ;
     RECT  9.54 75.821 9.558 76.925 ;
     RECT  16.02 75.821 23.274 76.925 ;
     RECT  75.6 75.821 77.202 76.939 ;
     RECT  77.94 76.363 80.982 76.939 ;
     RECT  25.668 75.821 26.046 76.973 ;
     RECT  28.872 75.821 28.89 76.973 ;
     RECT  60.84 76.891 67.95 76.981 ;
     RECT  56.772 76.397 56.79 77.467 ;
     RECT  45.936 75.821 52.794 77.563 ;
     RECT  26.028 76.973 26.046 77.645 ;
     RECT  56.772 77.467 56.898 77.645 ;
     RECT  45.936 77.563 53.046 77.701 ;
     RECT  1.116 75.821 8.334 77.741 ;
     RECT  16.02 76.925 23.238 77.741 ;
     RECT  30.888 75.821 38.142 77.741 ;
     RECT  45.792 77.701 53.046 77.741 ;
     RECT  60.696 76.981 67.95 77.741 ;
     RECT  75.6 76.939 80.982 77.741 ;
    LAYER M4 ;
     RECT  0.06 23.712 2.329 23.736 ;
     RECT  0.06 38.88 2.329 38.904 ;
     RECT  2.329 23.328 2.365 23.736 ;
     RECT  0.06 54 2.365 54.024 ;
     RECT  0.06 69.168 2.365 69.192 ;
     RECT  2.329 3.408 2.408 3.432 ;
     RECT  0.06 8.544 2.408 8.568 ;
     RECT  2.329 19.344 2.408 19.368 ;
     RECT  2.329 20.592 2.408 20.616 ;
     RECT  2.365 23.328 2.408 24.504 ;
     RECT  2.401 29.808 2.408 29.832 ;
     RECT  2.365 33.552 2.408 33.576 ;
     RECT  2.329 36.816 2.408 36.84 ;
     RECT  2.329 38.16 2.408 38.904 ;
     RECT  2.365 43.536 2.408 43.56 ;
     RECT  2.365 46.32 2.408 46.344 ;
     RECT  2.365 48.432 2.408 48.456 ;
     RECT  2.365 54 2.408 54.696 ;
     RECT  2.329 56.064 2.408 56.088 ;
     RECT  2.365 60.816 2.408 60.84 ;
     RECT  2.365 62.16 2.408 62.184 ;
     RECT  2.365 67.584 2.408 67.608 ;
     RECT  2.365 68.928 2.408 69.192 ;
     RECT  2.329 70.8 2.408 70.824 ;
     RECT  2.408 2.148 2.512 75.612 ;
     RECT  2.512 2.418 2.704 75.342 ;
     RECT  2.704 54.672 3.011 56.52 ;
     RECT  3.011 54.672 3.161 55.56 ;
     RECT  2.704 66.528 3.203 68.952 ;
     RECT  2.704 58.128 3.233 59.832 ;
     RECT  2.704 18.192 3.251 27.288 ;
     RECT  3.251 18.192 3.341 18.792 ;
     RECT  2.704 35.808 3.413 36.888 ;
     RECT  3.203 68.928 3.521 68.952 ;
     RECT  3.413 36.48 3.557 36.888 ;
     RECT  2.704 62.16 3.587 64.872 ;
     RECT  2.704 51.36 3.665 51.624 ;
     RECT  2.704 33.312 3.697 34.728 ;
     RECT  2.704 70.416 3.697 70.728 ;
     RECT  2.704 71.856 3.697 72.312 ;
     RECT  2.704 31.92 3.733 31.944 ;
     RECT  2.704 28.944 3.737 30.792 ;
     RECT  3.203 66.528 3.737 67.608 ;
     RECT  2.704 48.432 3.769 48.456 ;
     RECT  2.704 49.536 3.769 49.56 ;
     RECT  2.704 38.16 3.781 39.048 ;
     RECT  3.781 38.16 3.805 39.768 ;
     RECT  3.769 48.432 3.805 49.56 ;
     RECT  3.805 38.16 3.868 40.392 ;
     RECT  3.697 70.416 3.884 72.312 ;
     RECT  3.737 66.528 3.913 67.416 ;
     RECT  2.704 3.12 3.925 3.96 ;
     RECT  3.733 31.92 3.949 32.04 ;
     RECT  3.913 66.24 3.949 67.416 ;
     RECT  3.884 70.416 3.971 72.408 ;
     RECT  3.769 17.568 3.985 17.592 ;
     RECT  3.805 47.808 3.985 49.56 ;
     RECT  3.233 58.128 3.985 58.632 ;
     RECT  3.905 6.288 3.989 6.312 ;
     RECT  3.251 20.112 4.213 27.288 ;
     RECT  4.213 20.112 4.237 27.72 ;
     RECT  4.237 20.112 4.249 27.96 ;
     RECT  3.949 31.776 4.273 32.04 ;
     RECT  3.697 33.312 4.273 35.352 ;
     RECT  2.704 46.08 4.273 46.584 ;
     RECT  3.737 28.992 4.309 30.792 ;
     RECT  4.273 31.776 4.309 35.352 ;
     RECT  3.985 57.552 4.309 58.632 ;
     RECT  3.233 59.808 4.309 59.832 ;
     RECT  4.309 28.992 4.313 35.352 ;
     RECT  3.557 36.576 4.316 36.888 ;
     RECT  3.868 38.16 4.316 39.048 ;
     RECT  3.341 18.768 4.525 18.792 ;
     RECT  4.309 57.552 4.525 59.832 ;
     RECT  3.587 64.368 4.525 64.872 ;
     RECT  3.949 65.904 4.525 67.416 ;
     RECT  4.021 6.816 4.547 6.84 ;
     RECT  4.525 57.312 4.565 59.832 ;
     RECT  3.985 47.808 4.601 50.184 ;
     RECT  3.985 17.424 4.633 17.592 ;
     RECT  4.249 20.112 4.637 22.824 ;
     RECT  4.693 10.032 4.705 10.056 ;
     RECT  3.925 3.12 4.709 4.152 ;
     RECT  4.313 28.992 4.709 31.8 ;
     RECT  4.273 44.832 4.709 46.584 ;
     RECT  2.704 8.784 4.739 8.808 ;
     RECT  4.709 28.992 4.745 30.36 ;
     RECT  3.868 40.368 4.745 40.392 ;
     RECT  4.525 64.368 4.777 67.416 ;
     RECT  4.273 68.4 4.777 68.856 ;
     RECT  4.777 64.368 4.781 68.856 ;
     RECT  4.781 65.904 4.789 68.856 ;
     RECT  3.665 51.6 4.813 51.624 ;
     RECT  4.705 10.032 4.849 10.296 ;
     RECT  4.525 11.424 4.849 11.448 ;
     RECT  4.789 65.904 4.849 69.288 ;
     RECT  3.971 70.416 4.849 72.024 ;
     RECT  4.709 44.832 4.883 46.536 ;
     RECT  4.453 13.296 4.885 13.32 ;
     RECT  4.849 65.904 4.889 72.024 ;
     RECT  4.633 16.56 4.921 17.592 ;
     RECT  4.313 32.88 4.925 35.352 ;
     RECT  4.925 34.656 4.931 35.352 ;
     RECT  4.777 15.12 4.957 15.144 ;
     RECT  4.921 16.56 4.957 17.64 ;
     RECT  3.161 55.536 4.957 55.56 ;
     RECT  4.889 65.904 4.961 71.208 ;
     RECT  4.849 10.032 4.993 11.448 ;
     RECT  4.525 18.768 4.993 19.032 ;
     RECT  4.637 20.112 4.993 20.856 ;
     RECT  4.709 31.344 4.997 31.8 ;
     RECT  4.565 57.312 5.029 59.592 ;
     RECT  4.925 32.88 5.033 33.288 ;
     RECT  4.813 51.36 5.065 51.624 ;
     RECT  2.704 52.944 5.065 53.544 ;
     RECT  3.587 62.16 5.065 62.808 ;
     RECT  4.745 29.232 5.141 30.36 ;
     RECT  4.249 24 5.173 27.96 ;
     RECT  2.704 60.816 5.173 60.84 ;
     RECT  5.065 62.16 5.173 63.288 ;
     RECT  5.137 72.528 5.173 72.552 ;
     RECT  4.883 45.12 5.177 46.536 ;
     RECT  5.065 51.36 5.18 51.816 ;
     RECT  4.601 47.808 5.213 49.56 ;
     RECT  4.961 66.288 5.213 71.208 ;
     RECT  5.173 60.816 5.219 63.288 ;
     RECT  5.173 24 5.249 28.008 ;
     RECT  5.213 47.856 5.249 49.56 ;
     RECT  4.931 34.656 5.285 34.68 ;
     RECT  5.249 24.96 5.315 28.008 ;
     RECT  4.957 14.832 5.317 17.64 ;
     RECT  5.173 72.528 5.317 72.792 ;
     RECT  5.141 29.52 5.321 30.36 ;
     RECT  4.637 22.032 5.353 22.824 ;
     RECT  4.997 31.344 5.393 31.512 ;
     RECT  4.885 13.296 5.42 13.656 ;
     RECT  5.317 14.832 5.42 17.736 ;
     RECT  5.353 22.032 5.429 23.592 ;
     RECT  5.42 13.296 5.453 17.736 ;
     RECT  5.315 27.312 5.465 28.008 ;
     RECT  5.321 30.24 5.465 30.36 ;
     RECT  5.033 33.024 5.465 33.288 ;
     RECT  5.18 51.216 5.469 51.816 ;
     RECT  5.065 52.944 5.469 53.592 ;
     RECT  4.993 10.032 5.497 11.784 ;
     RECT  5.429 22.464 5.573 23.592 ;
     RECT  5.497 10.032 5.605 11.976 ;
     RECT  4.316 36.576 5.605 39.048 ;
     RECT  5.605 9.552 5.609 11.976 ;
     RECT  5.469 51.216 5.641 53.592 ;
     RECT  5.029 57.12 5.677 59.592 ;
     RECT  5.213 68.352 5.681 71.208 ;
     RECT  2.704 41.616 5.717 43.848 ;
     RECT  5.609 9.552 5.725 9.816 ;
     RECT  5.605 36.528 5.821 39.048 ;
     RECT  4.993 40.416 5.821 40.44 ;
     RECT  4.781 64.368 5.821 64.632 ;
     RECT  5.177 45.12 5.825 46.488 ;
     RECT  5.785 50.112 5.857 50.136 ;
     RECT  5.641 51.216 5.857 54.216 ;
     RECT  4.957 55.536 5.857 55.848 ;
     RECT  5.821 36.528 5.861 40.44 ;
     RECT  5.453 13.056 5.933 17.736 ;
     RECT  5.857 50.112 5.933 55.848 ;
     RECT  5.677 56.88 5.941 59.592 ;
     RECT  5.717 42.048 5.996 43.848 ;
     RECT  5.825 45.12 5.996 46.248 ;
     RECT  5.465 27.312 6.005 27.336 ;
     RECT  5.996 42.048 6.083 46.248 ;
     RECT  5.681 68.784 6.113 71.208 ;
     RECT  4.709 3.12 6.145 3.144 ;
     RECT  4.709 4.128 6.145 4.152 ;
     RECT  5.609 10.992 6.145 11.976 ;
     RECT  5.933 13.056 6.145 13.32 ;
     RECT  5.861 36.528 6.145 39.912 ;
     RECT  5.213 66.288 6.149 66.696 ;
     RECT  6.149 66.432 6.181 66.696 ;
     RECT  6.083 44.304 6.185 46.248 ;
     RECT  5.249 47.856 6.217 48.936 ;
     RECT  6.113 70.944 6.217 71.208 ;
     RECT  5.933 14.448 6.289 17.736 ;
     RECT  4.993 18.768 6.289 20.856 ;
     RECT  5.933 54.768 6.289 55.848 ;
     RECT  5.941 56.88 6.289 57.336 ;
     RECT  6.083 42.048 6.293 43.32 ;
     RECT  5.941 58.512 6.293 59.592 ;
     RECT  6.289 54.768 6.329 57.336 ;
     RECT  5.219 61.2 6.365 63.288 ;
     RECT  5.465 30.24 6.433 30.264 ;
     RECT  5.393 31.344 6.433 31.368 ;
     RECT  6.181 66.432 6.545 67.8 ;
     RECT  5.725 9.648 6.577 9.816 ;
     RECT  6.145 10.992 6.577 13.32 ;
     RECT  6.145 36.096 6.581 39.912 ;
     RECT  6.433 29.76 6.613 30.264 ;
     RECT  6.217 47.28 6.613 48.936 ;
     RECT  5.933 50.112 6.613 53.352 ;
     RECT  6.217 70.944 6.617 71.544 ;
     RECT  6.145 33.504 6.649 33.528 ;
     RECT  6.581 36.096 6.685 37.56 ;
     RECT  6.613 47.28 6.697 53.352 ;
     RECT  6.577 9.648 6.716 13.32 ;
     RECT  5.573 22.464 6.716 23.544 ;
     RECT  6.289 14.448 6.721 20.856 ;
     RECT  6.433 31.344 6.725 32.04 ;
     RECT  6.721 14.448 6.757 20.952 ;
     RECT  6.716 22.08 6.757 23.544 ;
     RECT  6.293 58.656 6.757 59.592 ;
     RECT  6.365 61.968 6.757 63.288 ;
     RECT  5.821 64.368 6.757 64.872 ;
     RECT  6.721 74.688 6.767 74.712 ;
     RECT  5.317 72.528 6.785 72.84 ;
     RECT  6.716 9.072 6.803 13.32 ;
     RECT  6.581 38.784 6.833 39.912 ;
     RECT  6.767 74.064 6.833 74.712 ;
     RECT  6.545 66.48 6.865 67.8 ;
     RECT  6.113 68.784 6.865 69.816 ;
     RECT  6.329 54.768 6.901 55.464 ;
     RECT  6.649 33.12 6.937 33.528 ;
     RECT  6.613 29.04 7.009 30.264 ;
     RECT  6.329 56.64 7.009 57.336 ;
     RECT  6.757 58.656 7.009 59.832 ;
     RECT  5.315 24.96 7.045 26.328 ;
     RECT  7.009 29.04 7.117 30.312 ;
     RECT  6.803 9.792 7.153 13.32 ;
     RECT  6.757 14.448 7.153 23.832 ;
     RECT  7.117 29.04 7.261 30.6 ;
     RECT  6.833 39.552 7.261 39.912 ;
     RECT  7.153 9.792 7.333 23.832 ;
     RECT  7.045 24.96 7.333 26.856 ;
     RECT  7.261 39.552 7.333 40.056 ;
     RECT  7.225 41.232 7.333 41.256 ;
     RECT  6.865 66.48 7.369 69.816 ;
     RECT  6.617 70.944 7.369 71.256 ;
     RECT  7.009 56.64 7.549 57.576 ;
     RECT  7.009 58.656 7.549 60.456 ;
     RECT  7.333 9.792 7.669 26.856 ;
     RECT  6.757 61.968 7.669 64.872 ;
     RECT  6.685 35.424 7.729 37.56 ;
     RECT  7.369 66.48 7.729 71.256 ;
     RECT  6.785 72.528 7.729 72.936 ;
     RECT  6.697 50.544 7.765 53.352 ;
     RECT  7.765 50.544 7.801 53.592 ;
     RECT  6.901 54.672 7.801 55.464 ;
     RECT  6.145 3.12 7.808 4.152 ;
     RECT  6.757 7.776 7.808 7.8 ;
     RECT  7.549 8.784 7.808 8.808 ;
     RECT  7.669 9.792 7.808 26.904 ;
     RECT  7.261 28.272 7.808 30.6 ;
     RECT  6.725 32.016 7.808 32.04 ;
     RECT  6.937 33.12 7.808 33.624 ;
     RECT  7.729 35.424 7.808 37.896 ;
     RECT  7.333 39.552 7.808 41.256 ;
     RECT  6.293 43.056 7.808 43.32 ;
     RECT  6.185 44.4 7.808 46.248 ;
     RECT  6.697 47.28 7.808 49.224 ;
     RECT  7.801 50.544 7.808 55.464 ;
     RECT  7.549 56.64 7.808 60.456 ;
     RECT  7.669 61.44 7.808 64.872 ;
     RECT  7.729 66.48 7.808 72.936 ;
     RECT  6.833 74.064 7.808 74.088 ;
     RECT  7.808 2.148 7.912 75.612 ;
     RECT  7.912 2.418 8.104 75.612 ;
     RECT  8.104 26.832 8.129 27.912 ;
     RECT  8.104 29.04 8.129 29.832 ;
     RECT  8.104 6.912 8.201 25.8 ;
     RECT  8.104 45.552 8.201 55.896 ;
     RECT  8.201 23.808 8.243 25.8 ;
     RECT  8.104 32.448 8.273 35.544 ;
     RECT  8.243 23.808 8.345 25.752 ;
     RECT  8.273 33.36 8.417 35.544 ;
     RECT  8.104 61.44 8.417 64.728 ;
     RECT  8.417 33.36 8.489 33.384 ;
     RECT  8.104 75.12 8.513 75.612 ;
     RECT  8.201 6.912 8.531 22.824 ;
     RECT  8.531 6.912 8.849 22.2 ;
     RECT  8.201 45.552 8.849 51 ;
     RECT  8.849 45.552 8.921 50.808 ;
     RECT  8.104 3.12 8.957 4.44 ;
     RECT  8.201 52.224 8.957 55.896 ;
     RECT  8.417 64.416 9.029 64.728 ;
     RECT  8.104 39.456 9.097 41.256 ;
     RECT  8.104 42.288 9.097 43.992 ;
     RECT  8.921 45.552 9.097 45.576 ;
     RECT  8.104 30.816 9.101 31.32 ;
     RECT  8.957 4.128 9.109 4.44 ;
     RECT  8.104 5.712 9.109 5.784 ;
     RECT  9.101 31.2 9.133 31.32 ;
     RECT  8.417 61.44 9.169 63.288 ;
     RECT  9.109 4.128 9.205 5.784 ;
     RECT  8.849 6.912 9.205 20.184 ;
     RECT  8.104 36.768 9.241 38.376 ;
     RECT  9.097 39.456 9.241 43.992 ;
     RECT  9.205 4.128 9.347 20.184 ;
     RECT  9.133 31.2 9.349 32.28 ;
     RECT  9.349 31.2 9.353 33 ;
     RECT  8.513 75.12 9.389 75.816 ;
     RECT  8.129 27.744 9.421 27.912 ;
     RECT  9.029 64.464 9.493 64.728 ;
     RECT  8.104 66.048 9.493 72.84 ;
     RECT  8.849 21.264 9.529 22.2 ;
     RECT  9.421 27.456 9.529 27.912 ;
     RECT  8.129 29.376 9.529 29.832 ;
     RECT  8.417 34.416 9.529 35.544 ;
     RECT  9.241 36.768 9.529 43.992 ;
     RECT  9.097 45.024 9.529 45.576 ;
     RECT  9.353 32.256 9.533 33 ;
     RECT  8.104 57.168 9.565 59.736 ;
     RECT  8.345 23.808 9.637 25.56 ;
     RECT  9.565 57.168 9.709 60.12 ;
     RECT  9.169 61.104 9.709 63.288 ;
     RECT  9.529 76.896 9.731 76.92 ;
     RECT  9.637 56.016 9.745 56.04 ;
     RECT  9.709 57.168 9.745 63.288 ;
     RECT  9.529 34.416 9.785 45.576 ;
     RECT  9.347 4.128 9.821 7.656 ;
     RECT  8.104 74.112 9.821 74.136 ;
     RECT  9.785 34.464 9.889 45.576 ;
     RECT  9.493 64.464 9.929 72.84 ;
     RECT  9.529 21.264 9.961 22.248 ;
     RECT  9.929 66.24 9.997 72.84 ;
     RECT  9.347 8.832 10.028 20.184 ;
     RECT  9.961 21.264 10.028 22.584 ;
     RECT  9.529 27.456 10.105 29.832 ;
     RECT  9.745 56.016 10.105 63.288 ;
     RECT  9.929 64.464 10.105 65.256 ;
     RECT  9.821 5.136 10.109 7.656 ;
     RECT  9.889 34.464 10.109 46.008 ;
     RECT  8.921 47.28 10.109 50.808 ;
     RECT  9.637 23.664 10.141 25.56 ;
     RECT  10.105 26.784 10.145 29.832 ;
     RECT  10.028 8.832 10.181 22.584 ;
     RECT  9.389 75.264 10.211 75.816 ;
     RECT  10.141 23.664 10.213 25.656 ;
     RECT  10.145 26.784 10.213 28.488 ;
     RECT  10.181 8.832 10.253 20.184 ;
     RECT  10.109 34.464 10.289 41.544 ;
     RECT  10.109 42.528 10.289 46.008 ;
     RECT  8.957 52.224 10.309 54.984 ;
     RECT  10.181 21.264 10.321 22.584 ;
     RECT  10.213 23.664 10.321 28.488 ;
     RECT  10.105 56.016 10.325 65.256 ;
     RECT  9.353 31.2 10.357 31.272 ;
     RECT  10.289 42.72 10.361 46.008 ;
     RECT  8.957 3.12 10.393 3.144 ;
     RECT  9.821 4.128 10.393 4.152 ;
     RECT  10.357 30.864 10.429 31.272 ;
     RECT  10.145 29.616 10.501 29.832 ;
     RECT  10.429 30.864 10.501 31.992 ;
     RECT  9.533 32.976 10.501 33 ;
     RECT  10.109 6.672 10.537 7.656 ;
     RECT  10.253 8.832 10.537 20.088 ;
     RECT  9.997 66.24 10.541 73.176 ;
     RECT  10.541 66.336 10.577 73.176 ;
     RECT  10.577 66.336 10.643 72.984 ;
     RECT  10.501 29.616 10.721 33 ;
     RECT  10.721 31.056 10.789 33 ;
     RECT  10.289 34.464 10.789 37.416 ;
     RECT  10.789 31.056 10.793 37.416 ;
     RECT  10.325 61.056 10.865 65.256 ;
     RECT  10.109 47.28 10.933 50.712 ;
     RECT  10.361 42.768 10.969 46.008 ;
     RECT  10.309 52.224 10.969 55.032 ;
     RECT  10.325 56.016 10.969 59.928 ;
     RECT  10.393 3.12 11.036 4.152 ;
     RECT  10.109 5.136 11.036 5.592 ;
     RECT  10.969 42.768 11.041 46.152 ;
     RECT  10.933 47.232 11.041 50.712 ;
     RECT  11.036 3.12 11.081 5.592 ;
     RECT  11.041 42.768 11.081 50.712 ;
     RECT  11.081 42.768 11.117 50.664 ;
     RECT  10.537 6.672 11.221 20.088 ;
     RECT  10.969 52.224 11.261 59.928 ;
     RECT  10.211 75.264 11.317 75.384 ;
     RECT  10.321 21.264 11.329 28.488 ;
     RECT  10.721 29.616 11.329 30.072 ;
     RECT  10.793 32.976 11.477 37.416 ;
     RECT  11.477 33.024 11.509 37.416 ;
     RECT  10.289 38.496 11.509 41.544 ;
     RECT  11.261 56.016 11.513 59.928 ;
     RECT  11.081 4.128 11.545 5.592 ;
     RECT  11.509 33.024 11.617 41.544 ;
     RECT  11.117 42.768 11.617 42.792 ;
     RECT  10.865 61.152 11.653 65.256 ;
     RECT  10.643 66.336 11.653 69.864 ;
     RECT  11.545 4.128 11.657 5.64 ;
     RECT  11.329 21.264 11.689 30.072 ;
     RECT  10.793 31.056 11.689 31.464 ;
     RECT  11.261 52.224 11.689 54.984 ;
     RECT  11.617 33.024 11.729 42.792 ;
     RECT  11.657 5.232 11.797 5.64 ;
     RECT  11.221 6.672 11.797 20.136 ;
     RECT  11.689 21.264 11.833 31.464 ;
     RECT  11.513 56.064 11.873 59.928 ;
     RECT  11.797 5.232 11.941 20.136 ;
     RECT  11.833 21.264 11.941 31.752 ;
     RECT  11.689 51.84 11.941 54.984 ;
     RECT  11.653 61.152 12.013 69.864 ;
     RECT  10.643 70.896 12.013 72.984 ;
     RECT  12.013 61.152 12.053 72.984 ;
     RECT  11.873 57.072 12.193 59.928 ;
     RECT  12.053 61.152 12.193 72.936 ;
     RECT  11.941 51.696 12.233 54.984 ;
     RECT  11.729 42.48 12.265 42.792 ;
     RECT  11.117 43.92 12.265 50.664 ;
     RECT  11.657 4.128 12.625 4.152 ;
     RECT  11.941 5.232 12.625 31.752 ;
     RECT  11.729 33.024 12.697 41.256 ;
     RECT  12.265 42.48 12.697 50.664 ;
     RECT  12.233 51.696 12.697 54.168 ;
     RECT  11.873 56.064 12.733 56.088 ;
     RECT  11.081 3.12 12.841 3.144 ;
     RECT  12.625 4.128 12.841 31.752 ;
     RECT  12.841 3.12 12.853 31.752 ;
     RECT  12.697 33.024 12.853 54.168 ;
     RECT  12.853 3.12 13.208 54.168 ;
     RECT  12.733 55.248 13.208 56.088 ;
     RECT  12.193 57.072 13.208 72.936 ;
     RECT  12.661 74.064 13.208 74.088 ;
     RECT  11.317 75.264 13.208 75.816 ;
     RECT  13.208 2.148 13.312 75.816 ;
     RECT  13.312 2.418 13.504 75.816 ;
     RECT  13.504 53.616 13.681 74.136 ;
     RECT  13.681 53.616 13.717 73.896 ;
     RECT  13.717 53.616 13.781 72.936 ;
     RECT  13.781 53.808 13.925 72.936 ;
     RECT  13.504 75.264 13.955 75.816 ;
     RECT  13.504 3.12 14.393 40.872 ;
     RECT  13.504 43.536 14.393 52.536 ;
     RECT  13.504 41.904 14.605 42.552 ;
     RECT  14.393 43.536 14.605 46.776 ;
     RECT  13.925 53.808 14.681 72.84 ;
     RECT  13.955 75.792 14.749 75.816 ;
     RECT  14.605 41.904 14.789 46.776 ;
     RECT  14.393 30.288 14.821 40.872 ;
     RECT  14.789 41.904 14.821 46.584 ;
     RECT  14.681 53.808 14.857 59.928 ;
     RECT  14.749 75.792 14.867 76.392 ;
     RECT  14.821 30.288 14.897 46.584 ;
     RECT  14.681 61.2 15.077 72.84 ;
     RECT  14.393 47.808 15.212 52.536 ;
     RECT  14.857 53.568 15.212 59.928 ;
     RECT  14.867 75.792 15.26 75.816 ;
     RECT  14.393 3.12 15.289 29.016 ;
     RECT  15.077 68.64 15.349 72.84 ;
     RECT  15.253 74.112 15.349 74.136 ;
     RECT  15.349 68.64 15.395 74.136 ;
     RECT  14.897 38.016 15.437 46.584 ;
     RECT  15.26 75.264 15.587 75.816 ;
     RECT  15.395 68.64 15.653 73.512 ;
     RECT  15.212 47.808 15.721 59.928 ;
     RECT  15.077 61.2 15.721 67.656 ;
     RECT  15.437 42 15.757 46.584 ;
     RECT  15.721 47.808 15.757 67.656 ;
     RECT  15.289 2.88 15.781 29.016 ;
     RECT  14.897 30.288 15.781 37.032 ;
     RECT  15.587 75.792 15.941 75.816 ;
     RECT  15.781 2.88 15.973 37.032 ;
     RECT  15.437 38.016 16.049 40.92 ;
     RECT  15.937 74.64 16.049 74.664 ;
     RECT  15.757 42 16.085 67.656 ;
     RECT  15.973 2.832 16.409 37.032 ;
     RECT  16.049 38.112 16.477 40.92 ;
     RECT  16.085 42 16.477 66.312 ;
     RECT  16.477 38.112 16.732 66.312 ;
     RECT  16.409 34.8 16.765 37.032 ;
     RECT  15.653 68.64 16.801 72.552 ;
     RECT  16.765 34.8 16.841 37.128 ;
     RECT  16.085 67.632 16.873 67.656 ;
     RECT  16.801 68.64 16.873 72.936 ;
     RECT  16.732 38.496 16.883 66.312 ;
     RECT  16.883 38.496 16.913 43.032 ;
     RECT  16.883 44.064 17.053 66.312 ;
     RECT  16.873 67.632 17.053 72.936 ;
     RECT  16.409 2.832 17.057 33.72 ;
     RECT  17.057 2.928 17.129 33.72 ;
     RECT  17.053 44.064 17.237 72.936 ;
     RECT  17.237 45.504 17.629 72.936 ;
     RECT  16.841 34.944 18.169 37.128 ;
     RECT  18.169 34.944 18.205 37.608 ;
     RECT  17.129 3.12 18.421 33.72 ;
     RECT  18.205 34.944 18.421 37.704 ;
     RECT  18.421 3.12 18.608 37.704 ;
     RECT  16.913 38.688 18.608 43.032 ;
     RECT  17.237 44.16 18.608 44.424 ;
     RECT  17.629 45.504 18.608 73.656 ;
     RECT  18.608 2.148 18.712 75.612 ;
     RECT  18.712 2.418 18.904 75.342 ;
     RECT  18.904 73.968 19.037 74.088 ;
     RECT  18.904 36.624 19.145 72.84 ;
     RECT  19.145 42 19.253 72.84 ;
     RECT  19.253 42.096 19.541 72.84 ;
     RECT  19.037 73.968 19.907 73.992 ;
     RECT  18.904 3.12 20.401 35.208 ;
     RECT  19.145 36.624 20.581 40.92 ;
     RECT  19.541 42.096 20.581 50.328 ;
     RECT  19.541 51.552 20.653 72.84 ;
     RECT  20.653 51.408 20.765 72.84 ;
     RECT  20.581 36.624 21.049 50.328 ;
     RECT  20.765 51.408 21.049 53.976 ;
     RECT  20.401 3.12 21.301 35.592 ;
     RECT  21.049 36.624 21.301 53.976 ;
     RECT  21.301 3.12 21.557 53.976 ;
     RECT  20.765 54.96 21.697 72.84 ;
     RECT  21.557 40.8 21.913 53.976 ;
     RECT  21.697 54.96 21.913 72.888 ;
     RECT  21.913 40.8 22.067 72.888 ;
     RECT  22.021 74.064 22.108 74.328 ;
     RECT  22.067 40.8 22.115 72.84 ;
     RECT  22.115 40.8 22.633 50.184 ;
     RECT  22.633 40.608 22.777 50.184 ;
     RECT  22.108 74.064 22.813 74.088 ;
     RECT  22.777 40.56 23.101 50.184 ;
     RECT  22.115 51.216 23.101 72.84 ;
     RECT  23.245 76.896 23.507 76.92 ;
     RECT  22.813 73.872 23.605 74.088 ;
     RECT  23.569 75.264 23.605 75.288 ;
     RECT  21.557 3.12 24.008 39.576 ;
     RECT  23.101 40.56 24.008 72.84 ;
     RECT  23.605 73.872 24.008 75.288 ;
     RECT  24.008 2.148 24.101 75.612 ;
     RECT  24.101 2.148 24.112 75.816 ;
     RECT  24.112 2.418 24.304 75.816 ;
     RECT  24.304 75.264 24.445 75.816 ;
     RECT  24.304 2.976 24.581 72.6 ;
     RECT  24.581 2.976 25.085 43.896 ;
     RECT  24.581 44.976 25.265 72.6 ;
     RECT  25.265 53.04 25.468 72.6 ;
     RECT  24.445 75.744 25.505 75.816 ;
     RECT  25.468 53.04 25.517 59.544 ;
     RECT  25.468 60.624 25.693 72.6 ;
     RECT  25.657 76.944 25.811 76.968 ;
     RECT  25.693 60.624 25.841 72.888 ;
     RECT  25.841 60.624 26.021 72.648 ;
     RECT  25.973 77.616 26.057 77.64 ;
     RECT  26.021 60.624 26.093 72.6 ;
     RECT  25.085 42.528 26.197 43.896 ;
     RECT  25.265 44.976 26.197 52.056 ;
     RECT  25.505 75.696 26.444 75.816 ;
     RECT  26.197 42.528 26.485 52.056 ;
     RECT  26.444 75.264 26.531 75.816 ;
     RECT  25.085 2.976 26.557 41.496 ;
     RECT  26.485 42.48 26.557 52.056 ;
     RECT  25.517 53.232 26.557 59.544 ;
     RECT  26.557 2.976 26.629 59.544 ;
     RECT  26.531 75.36 26.723 75.816 ;
     RECT  26.093 60.624 26.957 72.312 ;
     RECT  26.629 2.88 27.212 59.544 ;
     RECT  26.665 74.112 27.313 74.136 ;
     RECT  27.212 2.88 27.385 59.64 ;
     RECT  26.723 75.792 27.836 75.816 ;
     RECT  26.957 61.44 28.069 72.312 ;
     RECT  28.069 61.44 28.249 72.6 ;
     RECT  27.313 74.016 28.897 74.136 ;
     RECT  27.836 75.264 28.897 75.816 ;
     RECT  27.385 2.88 29.125 60.312 ;
     RECT  28.249 61.44 29.125 72.696 ;
     RECT  28.861 76.944 29.315 76.968 ;
     RECT  29.125 2.88 29.329 72.696 ;
     RECT  29.329 2.88 29.365 72.744 ;
     RECT  29.365 2.88 29.408 72.84 ;
     RECT  28.897 74.016 29.408 75.816 ;
     RECT  29.408 2.148 29.512 75.816 ;
     RECT  29.512 2.418 29.704 75.816 ;
     RECT  29.704 74.304 30.197 75.816 ;
     RECT  29.704 2.88 30.233 72.936 ;
     RECT  30.233 54.96 30.341 72.936 ;
     RECT  30.197 74.64 30.521 75.816 ;
     RECT  30.341 61.824 30.593 72.936 ;
     RECT  30.521 74.64 30.707 75.288 ;
     RECT  30.233 2.88 30.845 53.928 ;
     RECT  30.341 54.96 30.909 60.648 ;
     RECT  30.845 44.976 31.205 53.928 ;
     RECT  30.707 74.64 31.205 74.664 ;
     RECT  30.593 61.824 31.453 72.84 ;
     RECT  30.845 2.88 31.861 43.32 ;
     RECT  31.205 44.976 31.861 53.88 ;
     RECT  31.861 2.88 32.173 53.88 ;
     RECT  30.909 54.96 32.173 60.552 ;
     RECT  32.173 2.88 32.245 60.552 ;
     RECT  31.453 61.776 32.245 72.84 ;
     RECT  32.245 2.88 32.353 72.84 ;
     RECT  32.785 74.112 32.869 74.136 ;
     RECT  32.353 2.88 32.965 72.936 ;
     RECT  32.965 2.88 33.797 72.984 ;
     RECT  33.797 67.872 33.865 72.984 ;
     RECT  33.865 67.872 34.477 73.848 ;
     RECT  33.797 2.88 34.808 66.888 ;
     RECT  34.477 67.872 34.808 74.808 ;
     RECT  34.808 2.148 34.912 75.612 ;
     RECT  34.912 2.418 35.104 75.342 ;
     RECT  35.104 74.544 35.795 74.856 ;
     RECT  35.795 74.736 36.209 74.856 ;
     RECT  36.209 74.832 36.821 74.856 ;
     RECT  35.104 2.88 37.433 73.416 ;
     RECT  37.465 74.544 38.185 74.568 ;
     RECT  38.185 74.544 38.477 74.664 ;
     RECT  38.257 75.792 38.509 75.816 ;
     RECT  37.433 2.88 38.977 72.936 ;
     RECT  38.509 75.264 39.107 75.816 ;
     RECT  38.977 2.832 39.197 72.936 ;
     RECT  39.409 73.392 39.877 73.464 ;
     RECT  39.197 2.832 40.208 72.264 ;
     RECT  39.877 73.392 40.208 74.136 ;
     RECT  39.107 75.552 40.208 75.816 ;
     RECT  40.208 2.148 40.312 75.816 ;
     RECT  40.312 2.418 40.504 75.816 ;
     RECT  40.504 75.264 41.171 75.816 ;
     RECT  40.504 2.832 41.393 72.552 ;
     RECT  41.171 75.312 41.411 75.816 ;
     RECT  41.393 2.88 41.789 72.552 ;
     RECT  41.789 3.072 41.996 72.552 ;
     RECT  41.996 3.072 42.083 72.984 ;
     RECT  41.411 75.792 42.724 75.816 ;
     RECT  42.083 3.072 43.045 72.552 ;
     RECT  43.045 2.832 43.297 72.552 ;
     RECT  43.297 2.832 43.481 72.84 ;
     RECT  43.009 74.448 44.108 74.472 ;
     RECT  42.724 75.744 44.108 75.816 ;
     RECT  43.481 2.88 44.237 72.84 ;
     RECT  44.108 74.448 44.237 75.816 ;
     RECT  44.237 75.264 45.605 75.816 ;
     RECT  44.237 3.072 45.608 72.84 ;
     RECT  45.605 75.264 45.608 75.612 ;
     RECT  45.608 2.148 45.712 75.612 ;
     RECT  45.712 2.418 45.904 75.342 ;
     RECT  45.904 2.832 46.145 74.856 ;
     RECT  46.145 2.832 46.433 72.936 ;
     RECT  46.433 2.88 46.721 72.936 ;
     RECT  46.721 3.072 46.739 72.936 ;
     RECT  46.739 3.072 46.793 72.888 ;
     RECT  46.145 74.112 47.117 74.856 ;
     RECT  47.117 74.112 47.585 74.712 ;
     RECT  47.461 1.728 47.873 1.752 ;
     RECT  48.869 1.728 48.953 1.752 ;
     RECT  46.793 3.072 48.985 72.552 ;
     RECT  47.585 74.112 49.057 74.136 ;
     RECT  49.057 73.536 49.628 74.136 ;
     RECT  49.628 73.536 49.715 74.568 ;
     RECT  48.985 2.832 50.033 72.552 ;
     RECT  50.293 1.728 50.465 1.752 ;
     RECT  40.117 77.616 50.749 77.64 ;
     RECT  50.749 77.472 50.789 77.64 ;
     RECT  50.033 2.832 50.821 50.664 ;
     RECT  50.033 51.696 50.869 72.552 ;
     RECT  49.715 73.536 50.869 74.328 ;
     RECT  50.789 77.472 50.869 77.496 ;
     RECT  50.821 2.784 51.008 50.664 ;
     RECT  50.869 51.696 51.008 74.328 ;
     RECT  51.008 2.148 51.112 75.612 ;
     RECT  50.869 76.944 51.185 77.496 ;
     RECT  51.112 2.148 51.304 75.342 ;
     RECT  51.304 2.148 51.733 75.288 ;
     RECT  51.733 1.728 51.869 75.288 ;
     RECT  51.869 2.304 51.875 75.288 ;
     RECT  51.875 2.304 52.157 75.24 ;
     RECT  51.185 77.472 52.261 77.496 ;
     RECT  52.261 77.472 52.787 77.688 ;
     RECT  52.157 60.672 53.027 75.24 ;
     RECT  52.787 77.472 53.219 77.592 ;
     RECT  53.153 0.096 53.237 0.12 ;
     RECT  53.221 75.264 53.461 75.288 ;
     RECT  52.157 2.304 53.521 59.64 ;
     RECT  53.027 60.672 53.521 74.088 ;
     RECT  53.521 2.304 53.525 74.088 ;
     RECT  53.461 75.264 54.421 75.336 ;
     RECT  53.525 2.592 54.593 74.088 ;
     RECT  54.593 1.728 54.605 74.088 ;
     RECT  54.421 75.264 54.605 75.816 ;
     RECT  54.605 75.264 54.659 75.576 ;
     RECT  54.605 1.728 54.677 1.752 ;
     RECT  54.605 3.12 54.713 74.088 ;
     RECT  54.713 3.12 55.001 72.84 ;
     RECT  54.713 74.064 55.177 74.088 ;
     RECT  54.659 75.264 55.177 75.288 ;
     RECT  55.933 0.576 56.099 0.6 ;
     RECT  55.177 74.064 56.245 75.288 ;
     RECT  55.001 3.12 56.293 72.456 ;
     RECT  56.293 3.12 56.401 72.504 ;
     RECT  56.401 2.88 56.408 72.504 ;
     RECT  56.245 74.064 56.408 75.336 ;
     RECT  56.408 2.148 56.485 75.612 ;
     RECT  56.485 2.148 56.704 75.768 ;
     RECT  53.219 77.472 56.717 77.496 ;
     RECT  56.704 53.376 56.732 75.768 ;
     RECT  56.732 53.376 56.819 75.864 ;
     RECT  56.717 77.472 56.909 77.64 ;
     RECT  57.437 1.728 57.521 1.752 ;
     RECT  56.819 53.376 57.701 75.384 ;
     RECT  57.409 76.368 57.731 76.392 ;
     RECT  56.704 2.928 57.733 52.248 ;
     RECT  57.701 53.376 57.733 73.56 ;
     RECT  57.733 2.928 58.061 73.56 ;
     RECT  57.701 74.592 58.085 75.384 ;
     RECT  58.061 73.344 58.163 73.56 ;
     RECT  58.085 74.592 58.169 75.816 ;
     RECT  58.163 73.344 58.277 73.512 ;
     RECT  58.061 2.928 58.597 72.36 ;
     RECT  58.885 1.728 59.177 1.752 ;
     RECT  58.169 74.592 59.248 75.288 ;
     RECT  59.248 74.592 59.357 75.336 ;
     RECT  58.597 2.88 59.533 72.36 ;
     RECT  59.357 75.264 59.741 75.336 ;
     RECT  59.741 75.264 59.825 75.816 ;
     RECT  60.325 1.728 60.409 1.752 ;
     RECT  59.825 75.264 60.437 75.576 ;
     RECT  60.437 75.552 60.515 75.576 ;
     RECT  59.533 2.88 60.649 72.504 ;
     RECT  60.649 2.832 60.685 72.504 ;
     RECT  58.277 73.488 60.685 73.512 ;
     RECT  60.685 2.832 61.225 73.512 ;
     RECT  61.765 1.728 61.808 1.752 ;
     RECT  61.225 2.832 61.808 74.136 ;
     RECT  61.808 1.728 61.849 75.612 ;
     RECT  61.849 2.148 61.912 75.612 ;
     RECT  61.912 2.418 62.104 75.342 ;
     RECT  62.104 2.88 62.705 73.368 ;
     RECT  62.705 58.128 62.813 73.368 ;
     RECT  62.705 2.88 62.993 57.096 ;
     RECT  63.197 1.728 63.281 1.752 ;
     RECT  62.813 58.128 63.281 72.504 ;
     RECT  62.993 3.024 63.997 57.096 ;
     RECT  63.281 58.128 63.997 66.648 ;
     RECT  63.281 67.632 64.105 72.504 ;
     RECT  64.105 67.632 64.403 72.936 ;
     RECT  64.357 74.64 64.405 74.664 ;
     RECT  64.405 74.64 64.451 75.288 ;
     RECT  64.565 0.096 64.649 0.12 ;
     RECT  64.403 67.632 64.685 72.36 ;
     RECT  64.451 75.264 64.793 75.288 ;
     RECT  63.997 3.024 64.897 66.648 ;
     RECT  64.685 67.632 64.897 70.68 ;
     RECT  64.897 3.024 65.02 70.68 ;
     RECT  56.909 77.616 65.621 77.64 ;
     RECT  64.685 71.712 65.761 72.36 ;
     RECT  65.02 3.024 65.909 48.456 ;
     RECT  65.02 49.824 65.945 70.68 ;
     RECT  65.945 49.824 66.049 63.384 ;
     RECT  66.005 0.096 66.089 0.12 ;
     RECT  66.049 49.776 66.445 63.384 ;
     RECT  65.945 64.416 66.661 70.68 ;
     RECT  65.761 71.712 66.661 72.504 ;
     RECT  65.909 3.024 66.913 48.12 ;
     RECT  66.913 2.88 66.985 48.12 ;
     RECT  66.661 64.416 67.021 72.504 ;
     RECT  66.445 49.584 67.129 63.384 ;
     RECT  66.985 2.88 67.208 48.216 ;
     RECT  67.129 49.536 67.208 63.384 ;
     RECT  67.021 64.368 67.208 72.504 ;
     RECT  67.208 2.148 67.312 75.612 ;
     RECT  67.312 2.418 67.504 75.342 ;
     RECT  67.477 0.096 67.601 0.12 ;
     RECT  67.504 2.88 67.601 72.504 ;
     RECT  67.601 2.88 67.817 66.6 ;
     RECT  67.817 2.88 67.852 55.56 ;
     RECT  67.817 56.592 67.853 66.6 ;
     RECT  67.601 67.584 68.069 72.504 ;
     RECT  67.853 58.512 68.141 66.6 ;
     RECT  68.069 67.584 68.141 70.68 ;
     RECT  67.504 75.264 68.581 75.288 ;
     RECT  68.069 71.808 68.675 72.312 ;
     RECT  67.852 49.536 68.785 55.56 ;
     RECT  67.853 56.592 68.785 57 ;
     RECT  68.675 72.288 68.861 72.312 ;
     RECT  67.504 73.584 68.897 73.608 ;
     RECT  68.141 58.704 68.917 66.6 ;
     RECT  68.141 67.584 68.917 70.152 ;
     RECT  68.713 1.728 68.963 1.752 ;
     RECT  67.852 2.88 68.969 48.216 ;
     RECT  68.917 58.704 68.969 70.152 ;
     RECT  68.581 75.264 68.969 75.336 ;
     RECT  68.969 44.928 69.061 48.216 ;
     RECT  68.785 49.536 69.061 57 ;
     RECT  69.061 44.928 69.217 57 ;
     RECT  69.217 44.928 69.221 57.624 ;
     RECT  68.969 2.88 69.356 43.944 ;
     RECT  69.221 57.6 69.397 57.624 ;
     RECT  68.969 58.704 69.397 69.624 ;
     RECT  69.221 44.928 69.436 56.616 ;
     RECT  69.356 2.592 69.443 43.944 ;
     RECT  69.436 44.976 69.725 56.616 ;
     RECT  69.577 72.816 69.829 72.84 ;
     RECT  69.061 75.744 70.213 75.816 ;
     RECT  70.189 0.576 70.355 0.6 ;
     RECT  69.685 71.28 70.405 71.304 ;
     RECT  69.829 72.384 70.405 72.84 ;
     RECT  70.213 75.552 70.453 75.816 ;
     RECT  70.453 75.408 70.549 75.816 ;
     RECT  69.725 46.224 70.585 56.616 ;
     RECT  69.397 57.6 70.585 69.624 ;
     RECT  70.405 71.28 70.585 72.84 ;
     RECT  69.145 74.304 70.585 74.328 ;
     RECT  70.585 46.224 70.589 69.624 ;
     RECT  70.589 46.224 70.625 57.624 ;
     RECT  70.589 58.656 70.697 69.624 ;
     RECT  70.697 58.704 70.733 69.624 ;
     RECT  70.549 75.408 70.739 76.392 ;
     RECT  69.443 2.784 70.805 43.944 ;
     RECT  69.725 44.976 70.837 45.144 ;
     RECT  70.625 46.224 70.837 57.336 ;
     RECT  70.837 44.976 70.877 57.336 ;
     RECT  70.585 71.28 70.985 74.328 ;
     RECT  70.805 2.784 71.125 43.896 ;
     RECT  70.733 60.672 71.161 69.624 ;
     RECT  71.161 60.672 71.197 69.768 ;
     RECT  70.985 71.28 71.197 72.984 ;
     RECT  71.125 2.64 71.212 43.896 ;
     RECT  70.985 74.304 71.341 74.328 ;
     RECT  70.739 75.408 71.341 75.816 ;
     RECT  71.197 60.672 71.417 72.984 ;
     RECT  71.341 74.304 71.459 75.816 ;
     RECT  71.521 1.728 71.795 1.752 ;
     RECT  71.212 2.784 72.284 43.896 ;
     RECT  70.877 44.976 72.284 53.4 ;
     RECT  70.733 58.704 72.385 59.448 ;
     RECT  72.284 2.784 72.608 53.4 ;
     RECT  70.877 54.48 72.608 57.336 ;
     RECT  72.385 58.656 72.608 59.448 ;
     RECT  71.417 60.672 72.608 71.832 ;
     RECT  71.417 72.816 72.608 72.984 ;
     RECT  71.459 74.304 72.608 74.328 ;
     RECT  71.459 75.696 72.608 75.816 ;
     RECT  72.608 2.148 72.904 75.816 ;
     RECT  72.904 57.312 73.073 70.632 ;
     RECT  72.904 44.976 73.081 52.056 ;
     RECT  73.081 44.976 73.217 48.456 ;
     RECT  72.961 1.728 73.235 1.752 ;
     RECT  72.904 75.696 73.289 75.816 ;
     RECT  73.073 57.504 73.361 70.632 ;
     RECT  73.217 44.976 73.505 48.408 ;
     RECT  73.361 57.504 73.523 67.752 ;
     RECT  73.081 49.584 73.541 52.056 ;
     RECT  72.904 5.76 73.577 41.256 ;
     RECT  73.577 5.76 73.613 39.864 ;
     RECT  73.613 6.24 73.649 39.864 ;
     RECT  73.523 57.504 73.721 67.512 ;
     RECT  73.577 40.896 74.005 41.256 ;
     RECT  72.904 42.432 74.005 43.992 ;
     RECT  74.005 40.896 74.045 43.992 ;
     RECT  74.045 41.904 74.077 43.992 ;
     RECT  73.505 44.976 74.077 47.304 ;
     RECT  73.721 59.808 74.099 67.512 ;
     RECT  73.505 48.384 74.221 48.408 ;
     RECT  72.904 54.72 74.257 56.136 ;
     RECT  73.361 68.784 74.257 70.632 ;
     RECT  72.904 71.616 74.257 71.64 ;
     RECT  74.077 41.904 74.261 47.304 ;
     RECT  73.289 75.792 74.365 75.816 ;
     RECT  74.257 54.48 74.473 56.136 ;
     RECT  72.904 72.816 74.485 73.8 ;
     RECT  73.721 57.504 74.492 58.152 ;
     RECT  74.492 57.456 74.579 58.152 ;
     RECT  73.649 39.504 74.617 39.864 ;
     RECT  74.485 72.816 74.653 74.136 ;
     RECT  74.365 75.264 74.653 75.816 ;
     RECT  74.545 52.992 74.657 53.016 ;
     RECT  74.365 1.728 74.675 1.752 ;
     RECT  72.904 4.512 74.677 4.536 ;
     RECT  73.649 6.24 74.693 38.28 ;
     RECT  74.677 3.936 74.723 4.536 ;
     RECT  74.261 44.976 74.725 47.304 ;
     RECT  74.221 48.384 74.725 48.456 ;
     RECT  74.723 3.936 74.764 4.152 ;
     RECT  74.473 54.288 74.797 56.136 ;
     RECT  74.099 59.952 74.869 67.512 ;
     RECT  74.617 39.504 74.905 40.632 ;
     RECT  74.693 6.24 74.977 7.992 ;
     RECT  74.693 9.072 74.981 38.28 ;
     RECT  74.905 39.264 75.049 40.632 ;
     RECT  74.261 41.904 75.049 43.992 ;
     RECT  74.257 68.784 75.085 71.64 ;
     RECT  74.725 44.976 75.157 48.456 ;
     RECT  73.541 49.584 75.157 51.72 ;
     RECT  74.579 57.504 75.161 58.152 ;
     RECT  75.085 68.784 75.205 71.688 ;
     RECT  74.653 72.816 75.205 75.816 ;
     RECT  74.797 53.76 75.233 56.136 ;
     RECT  74.981 9.6 75.269 38.28 ;
     RECT  75.269 9.6 75.341 27.624 ;
     RECT  75.157 44.976 75.377 51.72 ;
     RECT  74.869 59.952 75.397 67.656 ;
     RECT  75.161 57.648 75.445 58.152 ;
     RECT  75.397 59.808 75.445 67.656 ;
     RECT  74.764 4.128 75.449 4.152 ;
     RECT  75.269 28.608 75.521 38.28 ;
     RECT  75.377 44.976 75.557 45 ;
     RECT  75.049 39.264 75.593 43.992 ;
     RECT  75.205 68.784 75.593 75.816 ;
     RECT  75.593 68.784 75.665 74.904 ;
     RECT  75.521 29.04 75.685 38.28 ;
     RECT  75.593 39.264 75.685 41.208 ;
     RECT  74.977 6.144 75.737 7.992 ;
     RECT  75.445 57.648 75.769 67.656 ;
     RECT  75.665 68.784 75.769 74.808 ;
     RECT  75.341 9.6 75.773 27.528 ;
     RECT  75.685 29.04 75.773 41.208 ;
     RECT  75.773 29.04 75.809 38.28 ;
     RECT  75.625 52.704 75.841 52.728 ;
     RECT  75.233 53.76 75.841 55.896 ;
     RECT  75.737 6.24 75.845 7.992 ;
     RECT  75.773 9.6 75.953 17.16 ;
     RECT  75.809 29.04 75.953 38.04 ;
     RECT  75.953 9.6 75.985 10.488 ;
     RECT  75.841 1.728 76.115 1.752 ;
     RECT  75.593 42.336 76.117 43.992 ;
     RECT  75.953 11.52 76.133 17.16 ;
     RECT  76.133 11.52 76.205 17.064 ;
     RECT  75.953 29.04 76.205 37.992 ;
     RECT  76.117 42.336 76.205 44.616 ;
     RECT  75.769 57.648 76.205 74.808 ;
     RECT  76.205 57.648 76.241 64.44 ;
     RECT  75.773 18.144 76.277 27.528 ;
     RECT  76.277 18.24 76.313 27.528 ;
     RECT  75.377 46.272 76.417 51.72 ;
     RECT  75.841 52.704 76.417 55.896 ;
     RECT  76.417 46.272 76.453 55.896 ;
     RECT  76.241 57.648 76.457 60.6 ;
     RECT  76.205 65.424 76.457 74.808 ;
     RECT  76.457 57.648 76.565 59.304 ;
     RECT  76.205 12.816 76.673 17.064 ;
     RECT  76.565 57.648 76.673 58.056 ;
     RECT  76.241 61.584 76.673 64.44 ;
     RECT  75.773 39.264 76.705 41.208 ;
     RECT  76.205 42.336 76.705 44.28 ;
     RECT  76.705 39.264 76.745 44.28 ;
     RECT  76.745 39.264 76.781 42.36 ;
     RECT  76.453 45.6 76.781 55.896 ;
     RECT  76.673 14.256 76.817 17.064 ;
     RECT  76.205 29.232 76.853 37.992 ;
     RECT  76.313 18.48 76.889 27.528 ;
     RECT  76.889 18.672 76.925 27.528 ;
     RECT  76.817 14.256 76.961 16.92 ;
     RECT  76.853 34.512 76.961 37.992 ;
     RECT  76.781 39.264 76.961 40.872 ;
     RECT  75.845 6.24 76.997 7.944 ;
     RECT  76.961 39.264 76.997 39.912 ;
     RECT  76.961 37.008 77.033 37.992 ;
     RECT  77.033 37.344 77.065 37.992 ;
     RECT  76.673 57.648 77.173 57.96 ;
     RECT  76.981 76.944 77.173 76.968 ;
     RECT  77.173 76.944 77.249 77.064 ;
     RECT  75.985 9.504 77.281 10.488 ;
     RECT  76.205 11.52 77.281 11.784 ;
     RECT  75.805 3.408 77.372 3.432 ;
     RECT  76.853 29.232 77.389 33.384 ;
     RECT  77.372 2.88 77.413 3.432 ;
     RECT  76.745 43.344 77.413 44.28 ;
     RECT  76.781 45.6 77.413 49.032 ;
     RECT  77.389 29.04 77.42 33.384 ;
     RECT  77.249 77.04 77.42 77.064 ;
     RECT  77.245 1.728 77.507 1.752 ;
     RECT  77.413 2.88 77.564 3.72 ;
     RECT  77.173 56.88 77.641 57.96 ;
     RECT  76.565 59.28 77.641 59.304 ;
     RECT  77.42 77.04 77.717 77.688 ;
     RECT  77.281 9.504 77.797 11.784 ;
     RECT  77.413 43.344 77.821 49.032 ;
     RECT  77.42 28.8 77.965 33.384 ;
     RECT  77.564 2.88 78.008 4.536 ;
     RECT  76.997 6.24 78.008 6.264 ;
     RECT  76.997 7.392 78.008 7.944 ;
     RECT  77.797 9.072 78.008 11.784 ;
     RECT  76.673 12.816 78.008 13.128 ;
     RECT  76.961 14.448 78.008 16.92 ;
     RECT  76.925 18.672 78.008 19.656 ;
     RECT  76.925 20.736 78.008 27.528 ;
     RECT  77.965 28.704 78.008 33.384 ;
     RECT  76.961 34.512 78.008 36.024 ;
     RECT  77.065 37.344 78.008 38.76 ;
     RECT  76.781 42 78.008 42.36 ;
     RECT  77.821 43.344 78.008 49.08 ;
     RECT  76.781 50.16 78.008 55.896 ;
     RECT  77.641 56.88 78.008 59.304 ;
     RECT  76.457 60.384 78.008 60.6 ;
     RECT  76.673 61.632 78.008 64.44 ;
     RECT  76.457 65.424 78.008 74.376 ;
     RECT  78.008 2.148 78.112 75.612 ;
     RECT  78.112 2.148 78.304 75.342 ;
     RECT  78.304 43.296 78.329 50.376 ;
     RECT  78.304 18.816 78.365 19.032 ;
     RECT  78.304 23.04 78.365 24.936 ;
     RECT  78.304 34.608 78.365 36.024 ;
     RECT  78.304 55.248 78.365 63.384 ;
     RECT  78.304 31.728 78.401 32.52 ;
     RECT  78.365 60.576 78.401 63.336 ;
     RECT  77.717 77.664 78.419 77.688 ;
     RECT  78.304 9.072 78.437 12.072 ;
     RECT  78.304 28.704 78.437 30.696 ;
     RECT  78.304 68.592 78.473 73.8 ;
     RECT  78.304 3.696 78.509 3.72 ;
     RECT  78.365 55.248 78.509 59.592 ;
     RECT  78.304 14.64 78.545 16.632 ;
     RECT  78.437 29.856 78.545 30.696 ;
     RECT  78.304 52.176 78.545 52.872 ;
     RECT  78.401 61.104 78.545 63.336 ;
     RECT  78.365 24.912 78.581 24.936 ;
     RECT  78.304 37.44 78.581 38.76 ;
     RECT  78.509 55.248 78.604 59.304 ;
     RECT  78.545 14.64 78.617 15.576 ;
     RECT  78.365 18.96 78.617 19.032 ;
     RECT  78.304 7.68 78.653 7.704 ;
     RECT  78.617 15.552 78.653 15.576 ;
     RECT  78.304 26.112 78.653 27.432 ;
     RECT  78.365 34.608 78.653 35.832 ;
     RECT  78.581 38.16 78.653 38.712 ;
     RECT  78.545 61.104 78.653 62.808 ;
     RECT  78.329 43.296 78.659 50.04 ;
     RECT  78.437 9.6 78.689 12.072 ;
     RECT  78.545 16.608 78.689 16.632 ;
     RECT  78.659 45.6 78.689 48.984 ;
     RECT  78.545 52.8 78.689 52.872 ;
     RECT  78.304 54.096 78.689 54.12 ;
     RECT  78.659 43.632 78.697 44.232 ;
     RECT  78.653 62.688 78.707 62.808 ;
     RECT  78.304 13.104 78.717 13.512 ;
     RECT  78.689 48.384 78.725 48.984 ;
     RECT  78.473 68.592 78.755 73.56 ;
     RECT  78.613 76.368 78.755 76.392 ;
     RECT  78.689 10.848 78.761 12.072 ;
     RECT  78.304 66.768 78.761 67.608 ;
     RECT  78.761 10.848 78.797 11.976 ;
     RECT  78.365 23.04 78.797 23.592 ;
     RECT  78.689 46.032 78.797 46.872 ;
     RECT  78.689 9.6 78.833 9.624 ;
     RECT  78.797 10.848 78.833 11.256 ;
     RECT  78.717 13.104 78.833 13.128 ;
     RECT  78.617 18.96 78.833 18.984 ;
     RECT  78.304 21.504 78.833 21.528 ;
     RECT  78.401 32.448 78.833 32.52 ;
     RECT  78.653 34.944 78.833 35.832 ;
     RECT  78.659 50.016 78.833 50.04 ;
     RECT  78.604 58.704 78.833 59.304 ;
     RECT  78.707 62.784 78.833 62.808 ;
     RECT  78.304 65.424 78.833 65.448 ;
     RECT  78.761 67.056 78.833 67.08 ;
     RECT  78.604 55.248 78.851 57.384 ;
     RECT  78.545 29.856 78.869 29.88 ;
     RECT  78.851 56.448 78.869 57.384 ;
     RECT  78.797 46.032 78.905 46.824 ;
     RECT  78.833 58.704 78.905 59.256 ;
     RECT  78.725 48.384 78.941 48.936 ;
     RECT  78.755 70.272 78.941 73.56 ;
     RECT  78.685 1.728 78.947 1.752 ;
     RECT  78.905 46.608 78.977 46.824 ;
     RECT  78.869 57.36 78.977 57.384 ;
     RECT  78.653 26.112 79.049 26.328 ;
     RECT  78.941 71.088 79.049 73.56 ;
     RECT  78.833 10.848 79.121 10.872 ;
     RECT  79.049 26.112 79.121 26.136 ;
     RECT  78.833 32.496 79.121 32.52 ;
     RECT  78.697 43.632 79.121 43.656 ;
     RECT  78.977 46.8 79.121 46.824 ;
     RECT  78.653 61.104 79.121 61.128 ;
     RECT  78.755 68.592 79.121 69.096 ;
     RECT  78.689 52.848 79.193 52.872 ;
     RECT  78.905 58.704 79.265 58.728 ;
     RECT  79.121 68.688 79.301 69.096 ;
     RECT  78.653 27.408 79.337 27.432 ;
     RECT  79.301 69.072 79.337 69.096 ;
     RECT  79.049 71.088 79.337 73.512 ;
     RECT  79.337 72.048 79.373 73.512 ;
     RECT  79.373 72.048 79.445 72.072 ;
     RECT  78.653 38.16 79.661 38.184 ;
     RECT  78.941 48.912 79.661 48.936 ;
     RECT  79.373 73.488 79.733 73.512 ;
     RECT  79.724 77.664 79.811 77.688 ;
     RECT  79.765 70.08 79.849 70.104 ;
     RECT  80.341 0.576 80.425 0.6 ;
     RECT  81.889 1.68 82.044 1.704 ;
     RECT  80.881 3.024 82.044 3.048 ;
     RECT  81.961 4.368 82.044 4.392 ;
     RECT  80.773 5.712 82.044 5.736 ;
     RECT  80.881 7.056 82.044 7.08 ;
     RECT  80.341 8.448 82.044 8.472 ;
     RECT  80.341 9.792 82.044 9.816 ;
     RECT  80.701 11.136 82.044 11.16 ;
     RECT  80.917 12.48 82.044 12.504 ;
     RECT  79.765 13.824 82.044 13.848 ;
     RECT  80.917 15.216 82.044 15.24 ;
     RECT  80.917 16.56 82.044 16.584 ;
     RECT  80.917 17.904 82.044 17.928 ;
     RECT  80.917 19.248 82.044 19.272 ;
     RECT  80.917 20.592 82.044 20.616 ;
     RECT  80.917 21.936 82.044 21.96 ;
     RECT  81.493 23.328 82.044 23.352 ;
     RECT  80.917 24.672 82.044 24.696 ;
     RECT  80.917 26.016 82.044 26.04 ;
     RECT  81.457 27.36 82.044 27.384 ;
     RECT  80.917 28.704 82.044 28.728 ;
     RECT  81.961 30.096 82.044 30.12 ;
     RECT  80.917 31.44 82.044 31.464 ;
     RECT  80.341 32.784 82.044 32.808 ;
     RECT  80.917 34.128 82.044 34.152 ;
     RECT  80.341 35.472 82.044 35.496 ;
     RECT  80.917 36.816 82.044 36.84 ;
     RECT  81.457 38.208 82.044 38.232 ;
     RECT  80.917 39.552 82.044 39.576 ;
     RECT  80.341 40.896 82.044 40.92 ;
     RECT  80.377 42.24 82.044 42.264 ;
     RECT  80.917 43.584 82.044 43.608 ;
     RECT  80.917 44.976 82.044 45 ;
     RECT  80.881 46.32 82.044 46.344 ;
     RECT  80.341 47.664 82.044 47.688 ;
     RECT  80.953 49.008 82.044 49.032 ;
     RECT  80.881 50.352 82.044 50.376 ;
     RECT  80.917 51.744 82.044 51.768 ;
     RECT  80.917 53.088 82.044 53.112 ;
     RECT  80.917 54.432 82.044 54.456 ;
     RECT  80.917 55.776 82.044 55.8 ;
     RECT  80.917 57.12 82.044 57.144 ;
     RECT  80.917 58.464 82.044 58.488 ;
     RECT  80.917 59.856 82.044 59.88 ;
     RECT  80.917 61.2 82.044 61.224 ;
     RECT  80.917 62.544 82.044 62.568 ;
     RECT  81.457 63.888 82.044 63.912 ;
     RECT  80.917 65.232 82.044 65.256 ;
     RECT  81.457 66.624 82.044 66.648 ;
     RECT  80.377 67.968 82.044 67.992 ;
     RECT  80.953 69.312 82.044 69.336 ;
     RECT  80.377 70.656 82.044 70.68 ;
     RECT  80.377 72 82.044 72.024 ;
     RECT  80.881 73.344 82.044 73.368 ;
     RECT  80.917 74.736 82.044 74.76 ;
     RECT  80.377 76.08 82.044 76.104 ;
    LAYER M5 ;
     RECT  53.184 0.016 53.208 0.131 ;
     RECT  64.608 0.016 64.632 0.131 ;
     RECT  66.048 0.016 66.072 0.131 ;
     RECT  67.488 0.016 67.512 0.131 ;
     RECT  56.064 0.016 56.088 0.611 ;
     RECT  70.32 0.016 70.344 0.611 ;
     RECT  80.352 0.016 80.376 0.611 ;
     RECT  47.472 0.016 47.496 1.763 ;
     RECT  48.912 0.016 48.936 1.763 ;
     RECT  50.304 0.016 50.328 1.763 ;
     RECT  51.744 0.016 51.768 1.763 ;
     RECT  54.624 0.016 54.648 1.763 ;
     RECT  57.456 0.016 57.48 1.763 ;
     RECT  58.896 0.016 58.92 1.763 ;
     RECT  60.336 0.016 60.36 1.763 ;
     RECT  61.776 0.016 61.8 1.763 ;
     RECT  63.216 0.016 63.24 1.763 ;
     RECT  68.928 0.016 68.952 1.763 ;
     RECT  71.76 0.016 71.784 1.763 ;
     RECT  73.2 0.016 73.224 1.763 ;
     RECT  74.64 0.016 74.664 1.763 ;
     RECT  76.08 0.016 76.104 1.763 ;
     RECT  77.472 0.016 77.496 1.763 ;
     RECT  78.912 0.016 78.936 1.763 ;
     RECT  2.4 2.137 2.52 2.151 ;
     RECT  7.8 2.137 7.92 2.151 ;
     RECT  13.2 2.137 13.32 2.151 ;
     RECT  18.6 2.137 18.72 2.151 ;
     RECT  24 2.137 24.12 2.151 ;
     RECT  29.4 2.137 29.52 2.151 ;
     RECT  34.8 2.137 34.92 2.151 ;
     RECT  40.2 2.137 40.32 2.151 ;
     RECT  45.6 2.137 45.72 2.151 ;
     RECT  61.8 2.137 61.92 2.151 ;
     RECT  67.2 2.137 67.32 2.151 ;
     RECT  61.8 2.151 62.112 2.821 ;
     RECT  78 2.137 78.312 2.869 ;
     RECT  69.408 2.581 69.432 3.013 ;
     RECT  51 2.137 51.312 3.061 ;
     RECT  40.2 2.151 40.512 3.157 ;
     RECT  72.6 2.137 72.912 3.301 ;
     RECT  48.816 3.061 48.84 3.349 ;
     RECT  7.8 2.151 8.112 3.397 ;
     RECT  24 2.151 24.312 3.397 ;
     RECT  45.6 2.151 45.912 3.397 ;
     RECT  50.736 3.061 51.312 3.397 ;
     RECT  71.136 2.629 71.16 3.397 ;
     RECT  72.336 3.301 72.912 3.397 ;
     RECT  69.312 3.013 69.432 3.587 ;
     RECT  67.2 2.151 67.512 3.589 ;
     RECT  77.424 2.869 78.312 3.731 ;
     RECT  37.344 3.205 37.368 3.733 ;
     RECT  40.2 3.157 40.68 3.733 ;
     RECT  18.6 2.151 18.912 3.829 ;
     RECT  26.64 2.869 26.664 3.829 ;
     RECT  48.816 3.349 49.512 3.829 ;
     RECT  67.056 3.589 68.28 3.877 ;
     RECT  71.136 3.397 72.912 3.877 ;
     RECT  16.32 3.877 16.344 3.925 ;
     RECT  18.6 3.829 19.416 3.925 ;
     RECT  20.976 3.829 21 3.925 ;
     RECT  26.64 3.829 27 3.925 ;
     RECT  53.088 3.589 53.112 4.019 ;
     RECT  60.96 2.821 62.112 4.019 ;
     RECT  37.344 3.733 37.608 4.021 ;
     RECT  7.488 3.397 8.112 4.067 ;
     RECT  4.512 3.925 4.536 4.117 ;
     RECT  13.2 2.151 13.512 4.117 ;
     RECT  14.736 3.925 14.76 4.117 ;
     RECT  16.32 3.925 16.536 4.117 ;
     RECT  20.64 3.925 21 4.165 ;
     RECT  29.4 2.151 29.712 4.165 ;
     RECT  50.688 3.397 51.312 4.165 ;
     RECT  66.96 3.877 68.28 4.213 ;
     RECT  20.64 4.165 21.48 4.261 ;
     RECT  36.48 4.021 37.608 4.405 ;
     RECT  38.976 3.685 39 4.405 ;
     RECT  40.2 3.733 41.448 4.405 ;
     RECT  54.48 4.261 54.504 4.501 ;
     RECT  29.088 4.165 29.712 4.547 ;
     RECT  74.688 3.925 74.712 4.547 ;
     RECT  14.736 4.117 16.536 4.691 ;
     RECT  66.72 4.213 68.28 4.693 ;
     RECT  54.096 4.501 54.504 4.741 ;
     RECT  36.48 4.405 41.448 4.883 ;
     RECT  23.76 3.397 24.888 5.029 ;
     RECT  50.496 4.165 51.312 5.029 ;
     RECT  54.096 4.741 55.176 5.077 ;
     RECT  56.4 2.137 56.712 5.077 ;
     RECT  54.096 5.077 56.712 5.125 ;
     RECT  36.624 4.883 41.448 5.221 ;
     RECT  26.64 3.925 27.672 5.269 ;
     RECT  50.496 5.029 52.152 5.365 ;
     RECT  15.36 4.691 16.536 5.411 ;
     RECT  29.4 4.547 29.712 5.461 ;
     RECT  43.92 5.221 43.944 5.461 ;
     RECT  50.496 5.365 53.064 5.507 ;
     RECT  43.92 5.461 44.28 5.557 ;
     RECT  61.68 4.019 62.112 5.605 ;
     RECT  54.096 5.125 57.192 5.747 ;
     RECT  23.76 5.029 25.608 5.749 ;
     RECT  9.12 5.125 9.144 5.795 ;
     RECT  36.624 5.221 42.168 5.845 ;
     RECT  66.144 4.693 68.28 5.845 ;
     RECT  69.312 3.587 69.336 5.845 ;
     RECT  43.824 5.557 44.28 5.893 ;
     RECT  70.8 3.877 72.912 6.085 ;
     RECT  23.712 5.749 25.608 6.133 ;
     RECT  26.64 5.269 28.008 6.133 ;
     RECT  29.4 5.461 30.264 6.133 ;
     RECT  43.776 5.893 44.28 6.181 ;
     RECT  45.6 3.397 46.872 6.229 ;
     RECT  48 3.829 49.512 6.229 ;
     RECT  70.8 6.085 73.56 6.229 ;
     RECT  70.8 6.229 74.04 6.275 ;
     RECT  3.936 4.117 4.536 6.323 ;
     RECT  66.144 5.845 69.336 6.323 ;
     RECT  18.6 3.925 19.656 6.325 ;
     RECT  20.64 4.261 21.624 6.325 ;
     RECT  34.8 2.151 35.112 6.325 ;
     RECT  56.4 5.747 57.192 6.325 ;
     RECT  36.624 5.845 42.552 6.373 ;
     RECT  43.536 6.181 44.28 6.373 ;
     RECT  45.6 6.229 49.512 6.373 ;
     RECT  18.6 6.325 21.624 6.467 ;
     RECT  32.16 5.317 32.184 6.467 ;
     RECT  36.624 6.373 49.512 6.611 ;
     RECT  18.6 6.467 19.656 6.613 ;
     RECT  34.8 6.325 35.208 6.659 ;
     RECT  50.496 5.507 52.824 6.659 ;
     RECT  61.68 5.605 62.712 6.707 ;
     RECT  31.584 6.613 31.704 6.755 ;
     RECT  61.68 6.707 62.232 6.805 ;
     RECT  4.032 6.323 4.536 6.851 ;
     RECT  11.088 4.789 11.112 6.851 ;
     RECT  16.32 5.411 16.536 6.853 ;
     RECT  26.64 6.133 30.264 6.899 ;
     RECT  59.04 6.133 59.064 6.899 ;
     RECT  52.8 6.659 52.824 6.901 ;
     RECT  61.632 6.805 62.232 6.949 ;
     RECT  33.36 3.733 33.384 6.997 ;
     RECT  45.6 6.611 49.512 6.997 ;
     RECT  50.496 6.659 51.312 6.997 ;
     RECT  36.624 6.611 44.28 7.043 ;
     RECT  66.96 6.323 69.336 7.139 ;
     RECT  15.504 6.853 16.536 7.187 ;
     RECT  54.384 5.747 55.176 7.189 ;
     RECT  43.44 7.043 44.28 7.283 ;
     RECT  45.6 6.997 51.312 7.331 ;
     RECT  60.96 6.949 62.232 7.331 ;
     RECT  66.96 7.139 68.28 7.333 ;
     RECT  77.616 3.731 78.312 7.427 ;
     RECT  18.432 6.613 19.656 7.621 ;
     RECT  50.208 7.331 51.312 7.717 ;
     RECT  20.64 6.467 21.624 7.765 ;
     RECT  28.752 6.899 30.264 7.765 ;
     RECT  31.68 6.755 31.704 7.765 ;
     RECT  32.784 6.997 33.384 7.765 ;
     RECT  34.8 6.659 35.112 7.765 ;
     RECT  43.536 7.283 44.28 7.765 ;
     RECT  45.6 7.331 49.224 7.765 ;
     RECT  64.992 7.765 65.016 7.813 ;
     RECT  23.184 6.133 25.608 7.909 ;
     RECT  26.64 6.899 27.672 7.909 ;
     RECT  59.088 6.949 59.112 7.909 ;
     RECT  20.64 7.765 21.96 7.957 ;
     RECT  23.184 7.909 27.672 7.957 ;
     RECT  59.088 7.909 59.544 7.957 ;
     RECT  9.312 6.661 9.336 8.003 ;
     RECT  52.8 6.901 52.92 8.053 ;
     RECT  54.048 7.189 55.176 8.053 ;
     RECT  59.088 7.957 60.312 8.053 ;
     RECT  61.632 7.331 62.232 8.101 ;
     RECT  63.552 7.765 63.576 8.101 ;
     RECT  14.832 7.813 14.856 8.147 ;
     RECT  70.8 6.275 72.912 8.149 ;
     RECT  66.432 7.333 68.28 8.195 ;
     RECT  28.752 7.765 33.384 8.341 ;
     RECT  20.64 7.957 27.672 8.387 ;
     RECT  58.944 8.053 60.312 8.389 ;
     RECT  61.632 8.101 63.576 8.389 ;
     RECT  64.656 7.813 65.016 8.389 ;
     RECT  43.536 7.765 49.224 8.437 ;
     RECT  50.208 7.717 51.624 8.437 ;
     RECT  56.4 6.325 57.864 8.437 ;
     RECT  58.944 8.389 65.016 8.437 ;
     RECT  16.32 7.187 16.536 8.485 ;
     RECT  52.8 8.053 55.176 8.485 ;
     RECT  70.704 8.149 72.912 8.531 ;
     RECT  34.8 7.765 35.352 8.533 ;
     RECT  43.536 8.437 51.624 8.533 ;
     RECT  52.608 8.485 55.176 8.533 ;
     RECT  43.536 8.533 55.176 8.581 ;
     RECT  12.816 4.117 13.512 8.629 ;
     RECT  36.624 7.043 42.312 8.629 ;
     RECT  43.344 8.581 55.176 8.629 ;
     RECT  36.624 8.629 55.176 8.675 ;
     RECT  36.624 8.675 51.816 8.771 ;
     RECT  4.032 6.851 4.056 8.773 ;
     RECT  28.752 8.341 33.768 8.773 ;
     RECT  34.8 8.533 35.4 8.773 ;
     RECT  52.8 8.675 55.176 8.773 ;
     RECT  4.032 8.773 4.728 8.819 ;
     RECT  36.624 8.771 51.432 8.963 ;
     RECT  28.752 8.773 35.4 9.011 ;
     RECT  77.904 7.427 78.312 9.061 ;
     RECT  56.4 8.437 65.016 9.107 ;
     RECT  17.712 7.621 19.656 9.397 ;
     RECT  4.704 8.819 4.728 9.541 ;
     RECT  61.392 9.107 65.016 9.541 ;
     RECT  28.752 9.011 35.352 9.587 ;
     RECT  20.64 8.387 25.608 9.589 ;
     RECT  66.96 8.195 68.28 9.589 ;
     RECT  69.312 7.139 69.336 9.589 ;
     RECT  61.392 9.541 65.544 9.635 ;
     RECT  4.704 9.541 5.688 9.637 ;
     RECT  6.768 7.765 6.792 9.637 ;
     RECT  36.624 8.963 51.312 9.637 ;
     RECT  56.4 9.107 60.312 9.683 ;
     RECT  61.632 9.635 65.544 9.779 ;
     RECT  4.704 9.637 6.792 9.827 ;
     RECT  20.64 9.589 25.656 9.971 ;
     RECT  52.8 8.773 55.272 9.973 ;
     RECT  56.4 9.683 57.24 9.973 ;
     RECT  4.704 9.827 6.312 10.067 ;
     RECT  14.88 9.925 14.904 10.117 ;
     RECT  11.424 8.965 11.448 10.165 ;
     RECT  12.528 8.629 13.512 10.165 ;
     RECT  11.424 10.165 13.512 10.211 ;
     RECT  52.8 9.973 57.24 10.211 ;
     RECT  28.752 9.587 35.256 10.307 ;
     RECT  16.32 8.485 16.584 10.405 ;
     RECT  17.616 9.397 19.656 10.405 ;
     RECT  36.528 9.637 51.312 10.405 ;
     RECT  16.32 10.405 19.656 10.547 ;
     RECT  36.528 10.405 51.432 10.547 ;
     RECT  61.632 9.779 62.664 10.741 ;
     RECT  63.84 9.779 65.544 10.741 ;
     RECT  61.632 10.741 65.544 10.835 ;
     RECT  11.952 10.211 13.512 10.837 ;
     RECT  14.88 10.117 15.048 10.883 ;
     RECT  16.32 10.547 16.584 10.883 ;
     RECT  66.96 9.589 69.336 10.885 ;
     RECT  58.272 9.683 60.312 10.933 ;
     RECT  61.632 10.835 65.112 10.933 ;
     RECT  5.664 10.067 6.312 11.027 ;
     RECT  11.952 10.837 13.704 11.027 ;
     RECT  66.864 10.885 69.336 11.077 ;
     RECT  58.272 10.933 65.112 11.219 ;
     RECT  28.752 10.307 33.384 11.317 ;
     RECT  34.704 10.307 35.256 11.317 ;
     RECT  12.528 11.027 13.704 11.411 ;
     RECT  70.8 8.531 72.912 11.461 ;
     RECT  77.808 9.061 78.312 11.461 ;
     RECT  58.272 11.219 65.016 11.605 ;
     RECT  74.016 6.275 74.04 11.605 ;
     RECT  58.224 11.605 65.016 11.795 ;
     RECT  16.32 10.883 16.536 11.893 ;
     RECT  17.856 10.547 19.656 11.941 ;
     RECT  20.64 9.971 25.608 11.941 ;
     RECT  16.32 11.893 16.728 11.989 ;
     RECT  36.528 10.547 51.312 11.989 ;
     RECT  52.8 10.211 55.272 11.989 ;
     RECT  17.856 11.941 25.608 12.133 ;
     RECT  26.64 8.387 27.672 12.133 ;
     RECT  56.4 10.211 57.24 12.181 ;
     RECT  66.144 11.077 69.336 12.229 ;
     RECT  70.704 11.461 72.912 12.229 ;
     RECT  28.752 11.317 35.256 12.373 ;
     RECT  36.528 11.989 55.272 12.373 ;
     RECT  16.32 11.989 16.872 12.421 ;
     RECT  17.856 12.133 27.672 12.421 ;
     RECT  66.144 12.229 72.912 12.469 ;
     RECT  73.92 11.605 74.04 12.469 ;
     RECT  66.144 12.469 74.04 12.515 ;
     RECT  7.8 4.067 8.112 12.517 ;
     RECT  56.304 12.181 57.24 12.661 ;
     RECT  28.752 12.373 55.272 12.757 ;
     RECT  56.256 12.661 57.24 12.757 ;
     RECT  16.32 12.421 27.672 12.803 ;
     RECT  58.944 11.795 65.016 12.853 ;
     RECT  66.144 12.515 73.56 12.853 ;
     RECT  58.944 12.853 73.56 12.899 ;
     RECT  58.944 12.899 68.28 13.043 ;
     RECT  5.664 11.027 5.688 13.045 ;
     RECT  77.568 11.461 78.312 13.093 ;
     RECT  5.472 13.045 5.688 13.139 ;
     RECT  11.04 12.325 11.064 13.139 ;
     RECT  58.944 13.043 64.68 13.139 ;
     RECT  7.8 12.517 8.28 13.331 ;
     RECT  12.816 11.411 13.704 13.381 ;
     RECT  69.312 12.899 73.56 13.427 ;
     RECT  77.568 13.093 78.696 13.523 ;
     RECT  12.816 13.381 13.896 13.571 ;
     RECT  28.752 12.757 57.24 13.621 ;
     RECT  58.944 13.139 59.256 13.621 ;
     RECT  16.32 12.803 19.656 13.715 ;
     RECT  28.752 13.621 59.256 13.811 ;
     RECT  28.752 13.811 59.112 14.099 ;
     RECT  15.024 10.883 15.048 14.149 ;
     RECT  16.32 13.715 16.872 14.149 ;
     RECT  5.472 13.139 5.592 14.197 ;
     RECT  65.712 13.043 68.28 14.197 ;
     RECT  15.024 14.149 16.872 14.243 ;
     RECT  9.12 14.389 9.144 14.579 ;
     RECT  69.312 13.427 73.08 14.627 ;
     RECT  75.696 6.613 75.72 14.629 ;
     RECT  28.752 14.099 59.016 14.771 ;
     RECT  60.288 13.139 64.68 14.771 ;
     RECT  12.96 13.571 13.896 14.915 ;
     RECT  5.472 14.197 5.688 15.059 ;
     RECT  60.624 14.771 64.68 15.205 ;
     RECT  65.712 14.197 68.328 15.205 ;
     RECT  69.312 14.627 73.032 15.205 ;
     RECT  7.8 13.331 8.112 15.301 ;
     RECT  11.952 14.821 11.976 15.443 ;
     RECT  15.024 14.243 16.536 15.443 ;
     RECT  9.696 14.821 9.72 15.491 ;
     RECT  60.624 15.205 73.032 15.491 ;
     RECT  12.96 14.915 13.512 15.779 ;
     RECT  60.624 15.491 72.912 15.925 ;
     RECT  17.856 13.715 19.656 16.069 ;
     RECT  20.64 12.803 27.672 16.069 ;
     RECT  77.568 13.523 78.312 16.163 ;
     RECT  13.2 15.779 13.512 16.213 ;
     RECT  15.12 15.443 16.536 16.259 ;
     RECT  7.8 15.301 8.568 16.357 ;
     RECT  16.32 16.259 16.536 16.357 ;
     RECT  17.856 16.069 27.672 16.357 ;
     RECT  28.752 14.771 53.448 16.357 ;
     RECT  54.48 14.771 59.016 16.405 ;
     RECT  60.432 15.925 72.912 16.405 ;
     RECT  13.2 16.213 13.8 16.453 ;
     RECT  15.12 16.259 15.144 16.453 ;
     RECT  16.32 16.357 16.584 16.693 ;
     RECT  13.2 16.453 15.144 16.741 ;
     RECT  75.696 14.629 76.008 16.787 ;
     RECT  7.8 16.357 8.664 16.789 ;
     RECT  10.464 16.741 10.488 16.789 ;
     RECT  17.856 16.357 53.448 16.837 ;
     RECT  54.48 16.405 72.912 16.837 ;
     RECT  7.8 16.789 10.488 16.979 ;
     RECT  13.056 16.741 15.144 16.979 ;
     RECT  5.568 15.059 5.688 17.027 ;
     RECT  13.056 16.979 13.512 17.077 ;
     RECT  7.8 16.979 9.576 17.171 ;
     RECT  16.32 16.693 16.68 17.221 ;
     RECT  17.856 16.837 72.912 17.221 ;
     RECT  16.32 17.221 72.912 17.507 ;
     RECT  7.8 17.171 9.384 17.603 ;
     RECT  11.76 17.077 13.512 17.603 ;
     RECT  18.144 17.507 72.912 17.603 ;
     RECT  9.36 17.603 9.384 17.651 ;
     RECT  74.064 16.501 74.088 17.651 ;
     RECT  12.192 17.603 13.512 18.035 ;
     RECT  10.8 17.989 10.824 18.131 ;
     RECT  2.4 2.151 2.712 18.181 ;
     RECT  7.8 17.603 8.112 18.181 ;
     RECT  16.32 17.507 17.016 18.565 ;
     RECT  58.896 17.603 72.912 18.659 ;
     RECT  77.808 16.163 78.312 18.661 ;
     RECT  5.664 17.027 5.688 18.757 ;
     RECT  14.64 16.979 15.144 18.805 ;
     RECT  12.288 18.035 13.512 18.851 ;
     RECT  14.64 18.805 15.288 18.947 ;
     RECT  18.144 17.603 57.864 19.043 ;
     RECT  13.104 18.851 13.512 19.093 ;
     RECT  58.992 18.659 72.912 19.237 ;
     RECT  16.32 18.565 17.064 19.283 ;
     RECT  5.088 18.757 5.688 19.379 ;
     RECT  7.632 18.181 8.112 19.379 ;
     RECT  16.32 19.283 16.584 19.427 ;
     RECT  10.32 18.709 10.344 19.477 ;
     RECT  10.08 19.477 10.344 19.523 ;
     RECT  13.104 19.093 13.656 19.571 ;
     RECT  18.144 19.043 57.768 19.907 ;
     RECT  75.696 16.787 75.72 19.909 ;
     RECT  13.2 19.571 13.656 20.003 ;
     RECT  58.992 19.237 73.128 20.101 ;
     RECT  10.08 19.523 10.104 20.339 ;
     RECT  7.68 19.379 8.112 20.485 ;
     RECT  7.68 20.485 8.712 20.579 ;
     RECT  2.4 18.181 3.24 20.627 ;
     RECT  13.2 20.003 13.608 20.915 ;
     RECT  12.192 20.437 12.216 20.965 ;
     RECT  58.992 20.101 73.464 21.013 ;
     RECT  16.32 19.427 16.536 21.061 ;
     RECT  12 20.965 12.216 21.107 ;
     RECT  75.216 19.909 75.72 21.155 ;
     RECT  7.8 20.579 8.712 21.299 ;
     RECT  18.144 19.907 57.576 21.301 ;
     RECT  12.192 21.107 12.216 21.587 ;
     RECT  77.184 18.661 78.312 21.683 ;
     RECT  58.944 21.013 73.56 21.779 ;
     RECT  18.144 21.301 57.912 21.781 ;
     RECT  58.944 21.779 73.464 21.781 ;
     RECT  18.144 21.781 73.464 21.923 ;
     RECT  13.2 20.915 13.512 22.117 ;
     RECT  16.32 21.061 16.584 22.307 ;
     RECT  28.704 21.923 73.464 22.739 ;
     RECT  7.8 21.299 8.52 22.835 ;
     RECT  13.2 22.117 13.608 23.125 ;
     RECT  28.704 22.739 59.496 23.125 ;
     RECT  2.4 20.627 2.712 23.317 ;
     RECT  4.176 20.965 4.2 23.411 ;
     RECT  75.696 21.155 75.72 23.557 ;
     RECT  10.512 23.029 10.536 23.845 ;
     RECT  10.272 23.845 10.536 23.891 ;
     RECT  28.656 23.125 59.496 23.893 ;
     RECT  60.624 22.739 73.464 23.893 ;
     RECT  28.656 23.893 73.464 23.939 ;
     RECT  12.24 23.125 13.608 24.131 ;
     RECT  18.144 21.923 27.672 24.133 ;
     RECT  28.656 23.939 57.912 24.133 ;
     RECT  58.896 23.939 73.464 24.181 ;
     RECT  75.072 23.557 75.72 24.181 ;
     RECT  75.072 24.181 75.864 24.277 ;
     RECT  75.072 24.277 76.68 24.323 ;
     RECT  2.4 23.317 2.904 24.515 ;
     RECT  10.272 23.891 10.296 24.563 ;
     RECT  9.168 24.421 9.192 24.707 ;
     RECT  16.32 22.307 16.536 24.901 ;
     RECT  18.144 24.133 57.912 24.901 ;
     RECT  58.896 24.181 74.04 24.901 ;
     RECT  75.696 24.323 76.68 24.901 ;
     RECT  77.808 21.683 78.312 24.901 ;
     RECT  7.8 22.835 8.112 25.285 ;
     RECT  5.664 19.379 5.688 25.429 ;
     RECT  6.768 22.069 6.792 25.475 ;
     RECT  7.8 25.285 8.232 25.477 ;
     RECT  6.864 25.477 8.232 25.619 ;
     RECT  13.2 24.131 13.608 25.621 ;
     RECT  16.32 24.901 74.04 25.715 ;
     RECT  7.68 25.619 8.232 25.811 ;
     RECT  75.696 24.901 78.312 26.051 ;
     RECT  12.576 25.621 13.608 26.485 ;
     RECT  12.576 26.485 13.656 26.677 ;
     RECT  14.64 18.947 15.144 26.677 ;
     RECT  4.896 25.429 5.688 26.773 ;
     RECT  7.68 25.811 8.112 26.915 ;
     RECT  16.32 25.715 73.464 27.059 ;
     RECT  76.128 26.051 78.312 27.059 ;
     RECT  4.224 26.773 5.688 27.731 ;
     RECT  9.84 27.493 9.864 27.731 ;
     RECT  11.424 27.301 11.448 27.923 ;
     RECT  12.576 26.677 15.144 27.923 ;
     RECT  16.32 27.059 73.368 28.115 ;
     RECT  13.056 27.923 15.144 28.163 ;
     RECT  75.024 27.013 75.048 28.163 ;
     RECT  16.32 28.115 73.32 28.451 ;
     RECT  76.128 27.059 76.584 28.789 ;
     RECT  77.808 27.059 78.312 28.789 ;
     RECT  13.056 28.163 13.512 28.835 ;
     RECT  11.904 28.453 11.928 29.075 ;
     RECT  16.32 28.451 33.384 29.075 ;
     RECT  34.656 28.451 73.32 29.075 ;
     RECT  76.128 28.789 78.312 29.075 ;
     RECT  76.56 29.075 78.312 29.363 ;
     RECT  7.8 26.915 8.112 29.365 ;
     RECT  10.848 28.453 10.872 29.651 ;
     RECT  34.656 29.075 73.272 29.795 ;
     RECT  18.48 29.075 33.384 29.797 ;
     RECT  34.656 29.795 68.28 29.797 ;
     RECT  18.48 29.797 68.28 29.843 ;
     RECT  15.12 28.163 15.144 29.893 ;
     RECT  16.32 29.075 17.304 29.893 ;
     RECT  69.312 29.795 73.272 30.181 ;
     RECT  18.6 29.843 68.28 30.563 ;
     RECT  4.896 27.731 5.688 30.757 ;
     RECT  28.704 30.563 68.28 30.757 ;
     RECT  69.312 30.181 74.136 30.757 ;
     RECT  13.2 28.835 13.512 30.949 ;
     RECT  18.6 30.563 27.72 31.091 ;
     RECT  77.808 29.363 78.312 31.139 ;
     RECT  7.8 29.365 9.096 31.331 ;
     RECT  15.12 29.893 17.304 31.573 ;
     RECT  15.12 31.573 17.592 31.619 ;
     RECT  28.704 30.757 74.136 31.667 ;
     RECT  3.936 30.757 5.688 31.955 ;
     RECT  28.704 31.667 73.56 32.099 ;
     RECT  58.608 32.099 73.56 32.483 ;
     RECT  23.472 31.091 27.72 32.677 ;
     RECT  28.704 32.099 57.576 32.677 ;
     RECT  15.12 31.619 16.536 32.771 ;
     RECT  23.472 32.677 57.576 32.867 ;
     RECT  12.864 30.949 13.512 33.059 ;
     RECT  33.024 32.867 57.576 33.059 ;
     RECT  18.6 31.091 22.056 33.061 ;
     RECT  23.472 32.867 32.04 33.061 ;
     RECT  18.6 33.061 32.04 33.203 ;
     RECT  15.12 32.771 15.144 33.347 ;
     RECT  76.56 29.363 76.584 33.397 ;
     RECT  24 33.203 32.04 33.491 ;
     RECT  18.6 33.203 22.968 33.587 ;
     RECT  33.12 33.059 57.576 33.973 ;
     RECT  58.608 32.483 73.032 33.973 ;
     RECT  33.12 33.973 73.032 34.019 ;
     RECT  75.792 33.397 76.584 34.211 ;
     RECT  50.88 34.019 73.032 34.259 ;
     RECT  50.88 34.259 64.776 34.403 ;
     RECT  76.56 34.211 76.584 34.501 ;
     RECT  78 31.139 78.312 34.501 ;
     RECT  28.704 33.491 32.04 34.835 ;
     RECT  65.76 34.259 73.032 35.123 ;
     RECT  33.12 34.019 49.56 35.219 ;
     RECT  33.12 35.219 33.624 35.221 ;
     RECT  4.896 31.955 5.688 35.363 ;
     RECT  12.096 34.117 12.12 35.363 ;
     RECT  33.072 35.221 33.624 35.507 ;
     RECT  50.88 34.403 58.632 35.747 ;
     RECT  2.4 24.515 2.712 35.797 ;
     RECT  59.664 34.403 64.776 35.797 ;
     RECT  65.76 35.123 68.28 35.797 ;
     RECT  29.04 34.835 32.04 35.891 ;
     RECT  59.664 35.797 68.28 35.939 ;
     RECT  76.56 34.501 78.312 35.939 ;
     RECT  17.568 31.619 17.592 35.987 ;
     RECT  53.856 35.747 58.632 36.085 ;
     RECT  59.664 35.939 64.584 36.085 ;
     RECT  53.856 36.085 64.584 36.131 ;
     RECT  34.8 35.219 49.56 36.275 ;
     RECT  33.072 35.507 33.432 36.371 ;
     RECT  34.8 36.275 41.448 36.421 ;
     RECT  42.672 36.275 49.56 36.467 ;
     RECT  53.856 36.131 62.952 36.467 ;
     RECT  53.856 36.467 58.632 36.515 ;
     RECT  76.56 35.939 76.92 36.515 ;
     RECT  16.512 32.771 16.536 36.517 ;
     RECT  50.88 35.747 52.68 36.709 ;
     RECT  2.4 35.797 2.952 36.851 ;
     RECT  50.832 36.709 52.68 36.853 ;
     RECT  53.856 36.515 58.392 36.853 ;
     RECT  29.4 35.891 32.04 36.899 ;
     RECT  50.832 36.853 58.392 36.947 ;
     RECT  58.128 36.947 58.392 36.995 ;
     RECT  5.664 35.363 5.688 36.997 ;
     RECT  13.2 33.059 13.512 36.997 ;
     RECT  42.72 36.467 49.56 36.997 ;
     RECT  50.832 36.947 56.952 36.997 ;
     RECT  65.76 35.939 68.28 36.997 ;
     RECT  69.312 35.123 73.032 36.997 ;
     RECT  16.512 36.517 17.208 37.043 ;
     RECT  29.4 36.899 30.84 37.043 ;
     RECT  50.784 36.997 56.952 37.043 ;
     RECT  58.272 36.995 58.392 37.091 ;
     RECT  42.72 36.997 49.704 37.139 ;
     RECT  50.784 37.043 52.872 37.139 ;
     RECT  65.76 36.997 73.032 37.139 ;
     RECT  18.6 33.587 22.056 37.189 ;
     RECT  52.656 37.139 52.872 37.235 ;
     RECT  64.032 36.131 64.584 37.237 ;
     RECT  65.76 37.139 68.28 37.237 ;
     RECT  9.792 35.509 9.816 37.379 ;
     RECT  53.856 37.043 56.952 37.475 ;
     RECT  42.72 37.139 47.352 37.571 ;
     RECT  50.784 37.139 51.672 37.571 ;
     RECT  69.264 37.139 73.032 37.571 ;
     RECT  59.664 36.467 62.952 37.573 ;
     RECT  54.48 37.475 56.952 37.667 ;
     RECT  74.448 36.565 74.472 38.003 ;
     RECT  32.016 36.899 32.04 38.101 ;
     RECT  33.264 36.371 33.432 38.101 ;
     RECT  16.512 37.043 16.68 38.147 ;
     RECT  59.664 37.573 63 38.147 ;
     RECT  64.032 37.237 68.28 38.147 ;
     RECT  75.648 37.573 75.672 38.147 ;
     RECT  58.368 37.091 58.392 38.149 ;
     RECT  59.664 38.147 60.264 38.149 ;
     RECT  4.368 37.429 4.392 38.195 ;
     RECT  32.016 38.101 33.432 38.195 ;
     RECT  5.664 36.997 6.408 38.243 ;
     RECT  18.6 37.189 22.392 38.243 ;
     RECT  44.208 37.571 47.352 38.243 ;
     RECT  48.384 37.139 49.704 38.243 ;
     RECT  42.72 37.571 43.08 38.387 ;
     RECT  52.656 37.235 52.68 38.437 ;
     RECT  44.208 38.243 46.872 38.629 ;
     RECT  50.832 37.571 51.672 38.677 ;
     RECT  52.656 38.437 53.016 38.677 ;
     RECT  48.768 38.243 49.224 38.723 ;
     RECT  12.912 36.997 13.512 38.725 ;
     RECT  54.48 37.667 54.984 38.819 ;
     RECT  65.76 38.147 68.28 38.819 ;
     RECT  56.4 37.667 56.952 38.867 ;
     RECT  61.536 38.147 63 38.869 ;
     RECT  64.032 38.147 64.728 38.869 ;
     RECT  48.768 38.723 49.032 38.915 ;
     RECT  18.6 38.243 22.056 39.059 ;
     RECT  24 33.491 27.672 39.061 ;
     RECT  61.536 38.869 64.728 39.155 ;
     RECT  50.832 38.677 53.016 39.251 ;
     RECT  18.6 39.059 21.912 39.299 ;
     RECT  34.704 36.421 41.448 39.299 ;
     RECT  29.4 37.043 29.712 39.301 ;
     RECT  20.64 39.299 21.912 39.395 ;
     RECT  43.968 38.629 46.872 39.395 ;
     RECT  58.368 38.149 60.264 39.395 ;
     RECT  61.536 39.155 63 39.395 ;
     RECT  76.896 36.515 76.92 39.395 ;
     RECT  61.536 39.395 62.112 39.493 ;
     RECT  54.48 38.819 54.744 39.539 ;
     RECT  58.368 39.395 59.4 39.539 ;
     RECT  44.208 39.395 46.872 39.587 ;
     RECT  50.832 39.251 52.872 39.587 ;
     RECT  69.312 37.571 73.032 39.589 ;
     RECT  32.016 38.195 33.384 39.731 ;
     RECT  59.232 39.539 59.4 39.731 ;
     RECT  3.792 39.013 3.816 39.779 ;
     RECT  50.832 39.587 51.624 39.877 ;
     RECT  42.72 38.387 42.984 39.923 ;
     RECT  52.848 39.587 52.872 39.923 ;
     RECT  24 39.061 27.912 40.019 ;
     RECT  60.384 39.493 62.112 40.019 ;
     RECT  64.032 39.155 64.728 40.067 ;
     RECT  50.688 39.877 51.624 40.115 ;
     RECT  56.4 38.867 56.904 40.165 ;
     RECT  64.032 40.067 64.056 40.261 ;
     RECT  69.312 39.589 73.08 40.499 ;
     RECT  32.352 39.731 33.384 40.547 ;
     RECT  26.64 40.019 27.912 40.595 ;
     RECT  34.8 39.299 41.448 40.595 ;
     RECT  75.696 38.677 75.72 40.595 ;
     RECT  34.8 40.595 37.704 40.835 ;
     RECT  50.688 40.115 51.432 40.835 ;
     RECT  54.48 39.539 54.696 40.837 ;
     RECT  16.512 38.147 16.536 40.981 ;
     RECT  24 40.019 25.608 40.981 ;
     RECT  44.208 39.587 44.232 40.981 ;
     RECT  45.456 39.587 46.872 40.981 ;
     RECT  44.208 40.981 46.872 41.027 ;
     RECT  30.816 37.043 30.84 41.075 ;
     RECT  34.8 40.835 35.208 41.075 ;
     RECT  63.84 40.261 64.056 41.075 ;
     RECT  20.832 39.395 21.912 41.125 ;
     RECT  36.288 40.835 37.704 41.171 ;
     RECT  12.864 38.725 13.512 41.219 ;
     RECT  29.4 39.301 29.832 41.221 ;
     RECT  56.4 40.165 57.624 41.315 ;
     RECT  56.4 41.315 57.048 41.363 ;
     RECT  32.352 40.547 32.376 41.365 ;
     RECT  59.376 39.731 59.4 41.365 ;
     RECT  56.4 41.363 56.904 41.461 ;
     RECT  58.464 41.365 59.4 41.507 ;
     RECT  56.016 41.461 56.904 41.603 ;
     RECT  44.976 41.027 46.872 41.651 ;
     RECT  51 40.835 51.432 41.651 ;
     RECT  60.384 40.019 60.408 41.651 ;
     RECT  54.384 40.837 54.696 41.699 ;
     RECT  42.72 39.923 42.744 41.749 ;
     RECT  54.48 41.699 54.696 41.845 ;
     RECT  75.504 41.509 75.528 41.939 ;
     RECT  54.48 41.845 55.416 41.987 ;
     RECT  5.664 38.243 5.688 42.085 ;
     RECT  38.976 40.595 41.448 42.133 ;
     RECT  66.048 38.819 68.28 42.133 ;
     RECT  69.312 40.499 73.032 42.133 ;
     RECT  38.976 42.133 41.64 42.181 ;
     RECT  20.832 41.125 22.776 42.227 ;
     RECT  29.4 41.221 30.216 42.227 ;
     RECT  36.288 41.171 36.312 42.227 ;
     RECT  42.72 41.749 43.272 42.227 ;
     RECT  38.928 42.181 41.64 42.229 ;
     RECT  38.736 42.229 41.64 42.325 ;
     RECT  42.72 42.227 42.744 42.325 ;
     RECT  38.736 42.325 42.744 42.371 ;
     RECT  56.4 41.603 56.904 42.467 ;
     RECT  45.264 41.651 46.872 42.469 ;
     RECT  38.928 42.371 42.744 42.515 ;
     RECT  16.512 40.981 16.872 42.563 ;
     RECT  64.752 42.277 64.776 42.563 ;
     RECT  51 41.651 51.312 42.565 ;
     RECT  45.264 42.469 47.304 42.611 ;
     RECT  52.752 41.749 52.776 42.611 ;
     RECT  37.392 41.171 37.704 42.755 ;
     RECT  23.856 40.981 25.608 42.803 ;
     RECT  38.928 42.515 41.64 42.803 ;
     RECT  66.048 42.133 73.032 42.803 ;
     RECT  7.8 31.331 8.112 42.805 ;
     RECT  66.912 42.803 73.032 43.043 ;
     RECT  58.032 43.093 58.056 43.189 ;
     RECT  59.376 41.507 59.4 43.189 ;
     RECT  31.44 41.365 32.376 43.235 ;
     RECT  4.848 42.085 5.688 43.285 ;
     RECT  34.8 41.075 35.112 43.285 ;
     RECT  48.768 38.915 48.888 43.285 ;
     RECT  78 35.939 78.312 43.285 ;
     RECT  63.552 42.709 63.576 43.331 ;
     RECT  18.6 39.299 19.656 43.477 ;
     RECT  15.36 42.757 15.384 43.523 ;
     RECT  61.68 40.019 62.112 43.523 ;
     RECT  34.8 43.285 35.88 43.525 ;
     RECT  7.8 42.805 8.232 43.571 ;
     RECT  12.912 41.219 13.512 43.571 ;
     RECT  58.032 43.189 59.4 43.715 ;
     RECT  54.48 41.987 54.696 43.717 ;
     RECT  54.432 43.717 54.696 43.763 ;
     RECT  54.432 43.763 54.504 43.813 ;
     RECT  23.856 42.803 24.888 43.861 ;
     RECT  42.72 42.515 42.744 43.955 ;
     RECT  54.24 43.813 54.504 43.955 ;
     RECT  34.8 43.525 36.504 44.005 ;
     RECT  38.976 42.803 41.448 44.005 ;
     RECT  50.256 42.565 51.312 44.197 ;
     RECT  76.128 43.909 76.152 44.245 ;
     RECT  4.848 43.285 6.072 44.339 ;
     RECT  34.704 44.005 36.504 44.387 ;
     RECT  66.912 43.043 72.912 44.435 ;
     RECT  31.872 43.235 32.376 44.437 ;
     RECT  33.36 40.547 33.384 44.437 ;
     RECT  54.24 43.955 54.456 44.437 ;
     RECT  11.952 43.957 11.976 44.581 ;
     RECT  38.976 44.005 42.264 44.627 ;
     RECT  76.128 44.245 76.392 44.627 ;
     RECT  34.704 44.387 35.112 44.675 ;
     RECT  48.288 43.285 48.888 44.867 ;
     RECT  11.376 44.581 11.976 44.915 ;
     RECT  61.8 43.523 62.112 44.917 ;
     RECT  16.848 42.563 16.872 44.965 ;
     RECT  18.6 43.477 19.752 44.965 ;
     RECT  59.376 43.715 59.4 45.013 ;
     RECT  78 43.285 78.648 45.013 ;
     RECT  16.848 44.965 17.112 45.107 ;
     RECT  64.512 44.341 64.536 45.443 ;
     RECT  31.872 44.437 33.384 45.445 ;
     RECT  31.584 45.445 33.384 45.491 ;
     RECT  38.976 44.627 41.448 45.493 ;
     RECT  45.264 42.611 46.872 45.493 ;
     RECT  50.16 44.197 51.312 45.539 ;
     RECT  7.8 43.571 8.112 45.541 ;
     RECT  31.584 45.491 31.896 45.541 ;
     RECT  4.848 44.339 5.688 45.589 ;
     RECT  54.144 44.437 54.456 45.635 ;
     RECT  61.8 44.917 62.76 45.635 ;
     RECT  77.424 45.013 78.648 45.635 ;
     RECT  34.8 44.675 35.112 45.637 ;
     RECT  36.48 44.387 36.504 45.637 ;
     RECT  13.104 43.571 13.512 45.683 ;
     RECT  54.144 45.635 54.408 45.683 ;
     RECT  23.856 43.861 25.128 45.731 ;
     RECT  34.8 45.637 36.504 45.731 ;
     RECT  58.032 43.715 58.056 45.731 ;
     RECT  18.6 44.965 19.8 45.781 ;
     RECT  66.96 44.435 72.912 45.875 ;
     RECT  18.6 45.781 19.848 46.067 ;
     RECT  26.64 40.595 27.672 46.117 ;
     RECT  66.96 45.875 68.808 46.163 ;
     RECT  11.376 44.915 11.4 46.211 ;
     RECT  45.216 45.493 47.736 46.211 ;
     RECT  7.536 45.541 8.112 46.259 ;
     RECT  7.8 46.259 8.112 46.405 ;
     RECT  4.848 45.589 5.736 46.499 ;
     RECT  31.344 45.541 31.896 46.499 ;
     RECT  38.736 45.493 41.448 46.499 ;
     RECT  78 45.635 78.504 46.499 ;
     RECT  76.368 44.627 76.392 46.501 ;
     RECT  37.68 42.755 37.704 46.693 ;
     RECT  38.736 46.499 39 46.787 ;
     RECT  68.544 46.163 68.808 46.787 ;
     RECT  59.28 45.013 59.4 46.835 ;
     RECT  23.856 45.731 24.888 47.077 ;
     RECT  52.512 45.829 52.536 47.123 ;
     RECT  13.2 45.683 13.512 47.173 ;
     RECT  51 45.539 51.312 47.173 ;
     RECT  33.36 45.491 33.384 47.221 ;
     RECT  16.848 45.107 16.872 47.269 ;
     RECT  45.216 46.211 47.64 47.269 ;
     RECT  66.96 46.163 67.512 47.269 ;
     RECT  25.92 46.117 27.672 47.363 ;
     RECT  7.8 46.405 8.232 47.603 ;
     RECT  42.432 47.125 42.456 47.749 ;
     RECT  34.8 45.731 35.928 47.797 ;
     RECT  23.664 47.077 24.888 47.845 ;
     RECT  56.4 42.467 56.712 47.845 ;
     RECT  76.368 46.501 76.968 47.845 ;
     RECT  29.4 42.227 29.712 47.893 ;
     RECT  75.504 47.845 76.968 47.939 ;
     RECT  66.672 47.269 67.512 48.131 ;
     RECT  50.88 47.173 51.312 48.179 ;
     RECT  13.2 47.173 14.28 48.277 ;
     RECT  38.736 46.787 38.76 48.277 ;
     RECT  13.2 48.277 14.616 48.373 ;
     RECT  15.984 47.269 16.872 48.421 ;
     RECT  32.88 47.221 33.384 48.421 ;
     RECT  40.032 46.499 41.448 48.421 ;
     RECT  42.432 47.749 43.368 48.421 ;
     RECT  12.72 48.373 14.616 48.467 ;
     RECT  40.032 48.421 43.368 48.515 ;
     RECT  32.88 48.421 33.624 48.659 ;
     RECT  45.216 47.269 47.688 48.659 ;
     RECT  51 48.179 51.312 48.661 ;
     RECT  78 46.499 78.312 48.661 ;
     RECT  54.384 45.683 54.408 48.707 ;
     RECT  56.4 47.845 56.808 48.757 ;
     RECT  30.816 47.989 30.84 48.805 ;
     RECT  31.872 46.499 31.896 48.805 ;
     RECT  4.848 46.499 5.688 48.901 ;
     RECT  61.8 45.635 62.664 48.901 ;
     RECT  4.608 48.901 6.648 48.947 ;
     RECT  30.816 48.805 31.896 48.947 ;
     RECT  64.896 47.317 64.92 48.947 ;
     RECT  29.28 47.893 29.712 48.949 ;
     RECT  30.816 48.947 31.368 48.949 ;
     RECT  38.736 48.277 39 48.949 ;
     RECT  40.032 48.515 42.888 48.949 ;
     RECT  68.544 46.787 68.568 48.949 ;
     RECT  69.888 45.875 72.912 48.949 ;
     RECT  56.4 48.757 57 48.995 ;
     RECT  66.96 48.131 67.512 48.997 ;
     RECT  68.544 48.949 73.032 48.997 ;
     RECT  78 48.661 78.648 48.997 ;
     RECT  26.208 47.363 27.672 49.043 ;
     RECT  60.96 48.901 62.664 49.043 ;
     RECT  33.36 48.659 33.624 49.045 ;
     RECT  34.8 47.797 36.072 49.045 ;
     RECT  18.6 46.067 19.752 49.091 ;
     RECT  38.736 48.949 42.888 49.091 ;
     RECT  75.504 47.939 76.392 49.091 ;
     RECT  15.984 48.421 17.256 49.235 ;
     RECT  37.296 46.693 37.704 49.235 ;
     RECT  23.424 47.845 24.888 49.429 ;
     RECT  12.72 48.467 14.136 49.475 ;
     RECT  38.736 49.091 42.456 49.571 ;
     RECT  5.664 48.947 6.648 49.619 ;
     RECT  15.984 49.235 16.872 49.619 ;
     RECT  66.96 48.997 73.032 49.619 ;
     RECT  75.504 49.091 75.816 49.667 ;
     RECT  75.504 49.667 75.528 49.763 ;
     RECT  15.984 49.619 16.008 49.861 ;
     RECT  18.6 49.091 19.368 49.907 ;
     RECT  33.36 49.045 36.072 49.909 ;
     RECT  59.376 46.835 59.4 49.909 ;
     RECT  45.216 48.659 47.64 49.957 ;
     RECT  48.768 44.867 48.888 49.957 ;
     RECT  77.424 48.997 78.648 50.051 ;
     RECT  45.216 49.957 48.888 50.099 ;
     RECT  23.424 49.429 25.56 50.147 ;
     RECT  51 48.661 51.912 50.149 ;
     RECT  53.472 49.717 53.496 50.149 ;
     RECT  12.72 49.475 13.512 50.195 ;
     RECT  15.408 49.861 16.008 50.195 ;
     RECT  29.28 48.949 31.368 50.195 ;
     RECT  33.168 49.909 36.072 50.291 ;
     RECT  66.96 49.619 72.912 50.293 ;
     RECT  20.832 42.227 21.912 50.389 ;
     RECT  39.936 49.571 42.456 50.435 ;
     RECT  66.72 50.293 72.912 50.531 ;
     RECT  61.8 49.043 62.664 50.677 ;
     RECT  51 50.149 53.496 50.819 ;
     RECT  63.84 50.149 63.864 50.819 ;
     RECT  37.632 49.235 37.704 50.867 ;
     RECT  66.72 50.531 68.568 51.059 ;
     RECT  15.408 50.195 15.432 51.109 ;
     RECT  4.608 48.947 4.632 51.205 ;
     RECT  5.664 49.619 5.688 51.205 ;
     RECT  13.2 50.195 13.512 51.253 ;
     RECT  18.6 49.907 18.912 51.253 ;
     RECT  17.136 50.581 17.16 51.635 ;
     RECT  20.832 50.389 22.104 51.683 ;
     RECT  45.216 50.099 47.64 51.683 ;
     RECT  60.912 50.677 62.664 51.683 ;
     RECT  14.976 51.109 15.432 51.829 ;
     RECT  33.168 50.291 33.384 51.875 ;
     RECT  40.032 50.435 42.456 51.875 ;
     RECT  26.64 49.043 27.672 51.877 ;
     RECT  29.4 50.195 31.368 51.877 ;
     RECT  20.832 51.683 21.912 51.923 ;
     RECT  59.376 49.909 59.928 51.923 ;
     RECT  23.616 50.147 25.56 51.971 ;
     RECT  26.64 51.877 31.368 51.971 ;
     RECT  12.816 51.253 13.512 52.165 ;
     RECT  14.928 51.829 15.432 52.261 ;
     RECT  14.64 52.261 15.432 52.403 ;
     RECT  51 50.819 51.912 52.405 ;
     RECT  66.96 51.059 68.568 52.405 ;
     RECT  66.96 52.405 68.856 52.451 ;
     RECT  66.96 52.451 67.8 52.453 ;
     RECT  59.904 51.923 59.928 52.499 ;
     RECT  23.616 51.971 24.984 52.787 ;
     RECT  33.264 51.875 33.384 52.981 ;
     RECT  61.8 51.683 62.664 52.981 ;
     RECT  4.608 51.205 5.688 53.075 ;
     RECT  26.64 51.971 30.552 53.075 ;
     RECT  48.768 50.099 48.888 53.075 ;
     RECT  45.6 51.683 47.64 53.173 ;
     RECT  15.264 52.403 15.432 53.219 ;
     RECT  34.368 50.291 36.072 53.317 ;
     RECT  53.472 50.819 53.496 53.317 ;
     RECT  68.832 52.451 68.856 53.317 ;
     RECT  69.888 50.531 72.912 53.317 ;
     RECT  34.368 53.317 36.36 53.365 ;
     RECT  37.68 50.867 37.704 53.365 ;
     RECT  77.424 50.051 78.312 53.365 ;
     RECT  38.736 49.571 38.76 53.411 ;
     RECT  66.096 52.453 67.8 53.411 ;
     RECT  53.472 53.317 53.928 53.507 ;
     RECT  76.032 52.693 76.056 53.507 ;
     RECT  20.832 51.923 21.48 53.557 ;
     RECT  45.6 53.173 47.688 53.557 ;
     RECT  58.128 52.405 58.152 53.557 ;
     RECT  61.584 52.981 62.664 53.557 ;
     RECT  5.184 53.075 5.688 53.603 ;
     RECT  26.64 53.075 29.88 53.603 ;
     RECT  32.592 52.981 33.384 53.603 ;
     RECT  51 52.405 52.2 53.603 ;
     RECT  18.6 51.253 19.032 53.653 ;
     RECT  51 53.603 52.056 53.749 ;
     RECT  58.128 53.557 58.584 53.795 ;
     RECT  66.96 53.411 67.8 53.795 ;
     RECT  61.584 53.557 63.528 53.797 ;
     RECT  17.664 53.653 19.032 53.843 ;
     RECT  61.584 53.797 64.44 53.843 ;
     RECT  15.408 53.219 15.432 53.941 ;
     RECT  15.408 53.941 15.768 53.987 ;
     RECT  61.584 53.843 62.112 54.083 ;
     RECT  40.032 51.875 41.448 54.085 ;
     RECT  42.432 51.875 42.456 54.085 ;
     RECT  34.368 53.365 37.704 54.131 ;
     RECT  67.056 53.795 67.8 54.131 ;
     RECT  54.72 53.557 54.744 54.179 ;
     RECT  50.88 53.749 52.056 54.227 ;
     RECT  17.664 53.843 18.912 54.515 ;
     RECT  63.504 53.843 64.44 54.563 ;
     RECT  68.832 53.317 72.912 54.563 ;
     RECT  45.504 53.557 47.688 54.565 ;
     RECT  58.464 53.795 58.584 54.565 ;
     RECT  40.032 54.085 42.456 54.659 ;
     RECT  23.616 52.787 24.888 54.661 ;
     RECT  26.64 53.603 29.712 54.661 ;
     RECT  50.88 54.227 51.624 54.661 ;
     RECT  58.464 54.565 58.632 54.709 ;
     RECT  23.616 54.661 29.712 54.755 ;
     RECT  20.832 53.557 21.96 54.899 ;
     RECT  23.616 54.755 27 55.141 ;
     RECT  77.04 53.365 78.312 55.237 ;
     RECT  23.088 55.141 27 55.379 ;
     RECT  67.056 54.131 67.752 55.427 ;
     RECT  64.416 54.563 64.44 55.429 ;
     RECT  43.92 54.085 43.944 55.475 ;
     RECT  2.4 36.851 2.712 55.525 ;
     RECT  45.024 54.565 47.688 55.571 ;
     RECT  18.6 54.515 18.912 55.669 ;
     RECT  50.352 54.661 51.624 55.715 ;
     RECT  58.464 54.709 59.304 55.765 ;
     RECT  58.032 55.765 59.304 55.811 ;
     RECT  33.36 53.603 33.384 55.861 ;
     RECT  34.56 54.131 37.704 55.861 ;
     RECT  31.776 55.237 31.8 55.907 ;
     RECT  40.032 54.659 41.88 55.907 ;
     RECT  59.28 55.811 59.304 55.907 ;
     RECT  64.416 55.429 64.488 55.907 ;
     RECT  40.032 55.907 41.64 55.955 ;
     RECT  23.088 55.379 24.888 56.003 ;
     RECT  15.744 53.987 15.768 56.005 ;
     RECT  33.36 55.861 37.704 56.051 ;
     RECT  28.56 54.755 29.712 56.053 ;
     RECT  64.464 55.907 64.488 56.195 ;
     RECT  10.32 54.997 10.344 56.435 ;
     RECT  54.96 55.957 54.984 56.435 ;
     RECT  20.832 54.899 21.48 56.483 ;
     RECT  33.36 56.051 36.072 56.483 ;
     RECT  37.68 56.051 37.704 56.483 ;
     RECT  77.04 55.237 78.84 56.483 ;
     RECT  2.4 55.525 3 56.531 ;
     RECT  15.744 56.005 16.296 56.533 ;
     RECT  12.672 52.165 13.512 56.725 ;
     RECT  18.6 55.669 19.56 56.965 ;
     RECT  28.56 56.053 30.264 57.013 ;
     RECT  40.032 55.955 41.448 57.013 ;
     RECT  53.472 53.507 53.496 57.013 ;
     RECT  23.136 56.003 24.888 57.107 ;
     RECT  28.56 57.013 30.984 57.203 ;
     RECT  15.744 56.533 16.392 57.205 ;
     RECT  18.24 56.965 19.56 57.395 ;
     RECT  74.496 43.861 74.52 57.445 ;
     RECT  18.24 57.395 18.912 57.635 ;
     RECT  65.904 56.869 65.928 57.635 ;
     RECT  67.056 55.427 67.704 57.683 ;
     RECT  20.832 56.483 21 57.685 ;
     RECT  15.36 57.205 16.392 57.731 ;
     RECT  51 55.715 51.624 57.925 ;
     RECT  48.864 53.075 48.888 57.973 ;
     RECT  23.136 57.107 24.792 58.115 ;
     RECT  2.4 56.531 2.712 58.117 ;
     RECT  5.664 53.603 5.688 58.117 ;
     RECT  20.832 57.685 21.672 58.163 ;
     RECT  26.64 55.379 27 58.163 ;
     RECT  40.032 57.013 42.264 58.163 ;
     RECT  74.496 57.445 74.568 58.163 ;
     RECT  50.16 57.925 51.624 58.211 ;
     RECT  28.56 57.203 30.264 58.403 ;
     RECT  5.664 58.117 5.928 58.501 ;
     RECT  40.032 58.163 41.448 58.645 ;
     RECT  48.864 57.973 49.176 58.645 ;
     RECT  59.328 57.589 59.352 58.691 ;
     RECT  51 58.211 51.624 58.693 ;
     RECT  39.264 58.645 41.448 58.739 ;
     RECT  2.4 58.117 2.904 58.741 ;
     RECT  5.664 58.501 6.264 58.787 ;
     RECT  39.264 58.739 40.92 58.787 ;
     RECT  52.992 57.013 53.496 58.787 ;
     RECT  2.4 58.741 3 58.883 ;
     RECT  20.976 58.163 21.672 59.077 ;
     RECT  23.136 58.115 24.504 59.077 ;
     RECT  34.56 56.483 36.072 59.171 ;
     RECT  33.36 56.483 33.384 59.173 ;
     RECT  18.6 57.635 18.912 59.221 ;
     RECT  48.864 58.645 49.56 59.221 ;
     RECT  51 58.693 51.768 59.221 ;
     RECT  2.4 58.883 2.904 59.315 ;
     RECT  77.04 56.483 78.552 59.315 ;
     RECT  48.864 59.221 51.768 59.459 ;
     RECT  43.872 57.541 43.896 59.461 ;
     RECT  20.976 59.077 24.504 59.507 ;
     RECT  43.872 59.461 44.04 59.507 ;
     RECT  28.56 58.403 29.712 59.509 ;
     RECT  7.8 47.603 8.112 59.605 ;
     RECT  26.64 58.163 26.664 59.605 ;
     RECT  38.208 57.445 38.232 59.701 ;
     RECT  39.264 58.787 40.872 59.701 ;
     RECT  38.208 59.701 40.872 59.747 ;
     RECT  28.56 59.509 30.408 59.749 ;
     RECT  61.8 54.083 62.112 59.797 ;
     RECT  74.496 58.163 74.52 59.797 ;
     RECT  38.496 59.747 40.872 59.891 ;
     RECT  45.6 55.571 47.688 59.891 ;
     RECT  48.864 59.459 48.888 59.891 ;
     RECT  47.184 59.891 47.688 59.939 ;
     RECT  54.624 58.645 54.648 59.941 ;
     RECT  54.624 59.941 55.08 59.987 ;
     RECT  32.832 59.173 33.384 59.989 ;
     RECT  34.56 59.171 35.928 59.989 ;
     RECT  38.496 59.891 38.52 60.035 ;
     RECT  63.216 59.221 63.24 60.035 ;
     RECT  32.832 59.989 35.928 60.083 ;
     RECT  74.064 59.797 75.432 60.181 ;
     RECT  61.8 59.797 62.232 60.277 ;
     RECT  22.176 59.507 24.504 60.373 ;
     RECT  7.392 59.605 8.112 60.467 ;
     RECT  50.4 59.459 51.768 60.467 ;
     RECT  55.056 59.987 55.08 60.515 ;
     RECT  74.064 60.181 75.768 60.563 ;
     RECT  28.56 59.749 30.744 60.613 ;
     RECT  51 60.467 51.768 60.709 ;
     RECT  5.664 58.787 5.928 60.805 ;
     RECT  22.176 60.373 25.416 60.851 ;
     RECT  44.016 59.507 44.04 60.949 ;
     RECT  43.92 60.949 44.04 60.995 ;
     RECT  18.6 59.221 19.56 60.997 ;
     RECT  22.176 60.851 22.2 61.043 ;
     RECT  47.184 59.939 47.208 61.043 ;
     RECT  56.4 48.995 56.712 61.093 ;
     RECT  58.032 55.811 58.056 61.093 ;
     RECT  61.8 60.277 62.664 61.189 ;
     RECT  74.496 60.563 75.768 61.237 ;
     RECT  61.8 61.189 63.432 61.331 ;
     RECT  23.328 60.851 25.416 61.379 ;
     RECT  32.832 60.083 35.64 61.427 ;
     RECT  7.8 60.467 8.112 61.429 ;
     RECT  20.976 59.507 21 61.525 ;
     RECT  67.056 57.683 67.512 61.525 ;
     RECT  56.4 61.093 58.056 61.571 ;
     RECT  5.184 60.805 5.928 61.619 ;
     RECT  15.744 57.731 16.392 61.619 ;
     RECT  20.976 61.525 21.672 61.619 ;
     RECT  26.64 59.605 27.288 61.619 ;
     RECT  18.6 60.997 19.656 61.717 ;
     RECT  23.328 61.379 24.504 61.813 ;
     RECT  63.408 61.331 63.432 61.859 ;
     RECT  69.744 54.563 72.912 61.955 ;
     RECT  5.664 61.619 5.928 62.003 ;
     RECT  18.6 61.717 20.136 62.003 ;
     RECT  65.088 58.117 65.112 62.005 ;
     RECT  28.56 60.613 30.84 62.053 ;
     RECT  7.68 61.429 8.112 62.101 ;
     RECT  5.904 62.003 5.928 62.195 ;
     RECT  12.672 56.725 13.944 62.195 ;
     RECT  32.928 61.427 35.64 62.195 ;
     RECT  11.424 61.477 11.448 62.581 ;
     RECT  49.2 61.093 49.224 62.629 ;
     RECT  13.056 62.195 13.944 62.675 ;
     RECT  28.56 62.053 30.888 62.675 ;
     RECT  65.088 62.005 65.544 62.675 ;
     RECT  77.04 59.315 78.312 62.677 ;
     RECT  10.896 62.581 11.448 62.723 ;
     RECT  13.056 62.675 13.848 62.723 ;
     RECT  18.6 62.003 19.656 62.723 ;
     RECT  23.136 61.813 24.504 62.723 ;
     RECT  2.4 59.315 2.712 62.725 ;
     RECT  28.56 62.675 30.792 62.771 ;
     RECT  48.912 62.629 49.224 62.915 ;
     RECT  42.672 61.189 42.696 63.011 ;
     RECT  57.888 61.571 58.056 63.013 ;
     RECT  11.424 62.723 11.448 63.059 ;
     RECT  27.264 61.619 27.288 63.157 ;
     RECT  7.344 62.101 8.112 63.203 ;
     RECT  21.648 61.619 21.672 63.203 ;
     RECT  27.168 63.157 27.288 63.205 ;
     RECT  56.4 61.571 56.712 63.253 ;
     RECT  57.888 63.013 58.68 63.253 ;
     RECT  7.68 63.203 8.112 63.299 ;
     RECT  43.92 60.995 43.944 63.299 ;
     RECT  67.056 61.525 68.424 63.299 ;
     RECT  67.2 63.299 68.424 63.445 ;
     RECT  67.2 63.445 68.664 63.491 ;
     RECT  15.744 61.619 16.296 63.493 ;
     RECT  27.168 63.205 27.384 63.587 ;
     RECT  74.496 61.237 75.864 63.635 ;
     RECT  13.2 62.723 13.848 63.781 ;
     RECT  23.808 62.723 24.504 63.781 ;
     RECT  31.872 62.581 31.896 63.827 ;
     RECT  40.032 59.891 40.512 63.829 ;
     RECT  34.56 62.195 35.64 63.875 ;
     RECT  49.2 62.915 49.224 63.875 ;
     RECT  65.52 62.675 65.544 64.019 ;
     RECT  14.832 63.493 16.296 64.163 ;
     RECT  56.4 63.253 58.68 64.163 ;
     RECT  74.496 63.635 75.336 64.355 ;
     RECT  12.72 63.781 13.848 64.357 ;
     RECT  34.8 63.875 35.64 64.357 ;
     RECT  37.056 63.877 37.08 64.357 ;
     RECT  2.4 62.725 3.576 64.403 ;
     RECT  34.8 64.357 37.08 64.403 ;
     RECT  64.08 63.781 64.104 64.451 ;
     RECT  29.4 62.771 30.696 64.595 ;
     RECT  45.6 59.891 45.912 64.693 ;
     RECT  23.808 63.781 25.128 64.787 ;
     RECT  12.672 64.357 13.848 64.837 ;
     RECT  27.264 63.587 27.384 64.837 ;
     RECT  27.264 64.837 28.008 64.883 ;
     RECT  51 60.709 51.96 64.885 ;
     RECT  23.808 64.787 24.504 64.931 ;
     RECT  12.672 64.837 13.944 65.027 ;
     RECT  27.312 64.883 28.008 65.027 ;
     RECT  54.672 64.357 54.696 65.027 ;
     RECT  34.8 64.403 36.12 65.123 ;
     RECT  17.328 64.597 17.352 65.171 ;
     RECT  45.6 64.693 46.824 65.219 ;
     RECT  21.792 64.933 21.816 65.411 ;
     RECT  53.472 58.787 53.496 65.749 ;
     RECT  40.032 63.829 41.112 65.939 ;
     RECT  27.36 65.027 28.008 65.989 ;
     RECT  56.4 64.163 57.912 65.989 ;
     RECT  7.8 63.299 8.112 66.085 ;
     RECT  27.36 65.989 28.104 66.133 ;
     RECT  29.4 64.595 30.408 66.133 ;
     RECT  32.928 62.195 32.952 66.133 ;
     RECT  34.8 65.123 35.64 66.133 ;
     RECT  15.744 64.163 16.296 66.371 ;
     RECT  18.6 62.723 18.912 66.469 ;
     RECT  51 64.885 52.152 66.613 ;
     RECT  2.4 64.403 2.712 66.661 ;
     RECT  32.928 66.133 35.64 66.661 ;
     RECT  20.016 66.133 20.04 66.707 ;
     RECT  27.36 66.133 30.408 66.707 ;
     RECT  50.4 66.613 52.152 66.709 ;
     RECT  53.472 65.749 54.312 66.709 ;
     RECT  32.928 66.661 36.792 66.755 ;
     RECT  34.8 66.755 36.792 66.853 ;
     RECT  23.808 64.931 24.408 66.901 ;
     RECT  34.8 66.853 37.08 66.995 ;
     RECT  47.904 65.077 47.928 67.043 ;
     RECT  69.888 61.955 72.912 67.141 ;
     RECT  68.64 63.491 68.664 67.237 ;
     RECT  69.888 67.141 73.512 67.237 ;
     RECT  34.8 66.995 36.792 67.283 ;
     RECT  50.4 66.709 54.312 67.283 ;
     RECT  7.8 66.085 8.232 67.331 ;
     RECT  18.48 66.469 18.912 67.331 ;
     RECT  42.768 66.085 42.792 67.331 ;
     RECT  51 67.283 54.312 67.427 ;
     RECT  12.72 65.027 13.944 67.669 ;
     RECT  27.888 66.707 30.408 67.669 ;
     RECT  61.8 61.331 62.112 67.669 ;
     RECT  7.8 67.331 8.112 67.765 ;
     RECT  45.6 65.219 45.912 67.765 ;
     RECT  49.056 65.989 49.08 67.813 ;
     RECT  51 67.427 53.496 67.859 ;
     RECT  10.512 67.669 10.536 67.907 ;
     RECT  68.64 67.237 73.512 67.907 ;
     RECT  41.616 66.661 41.64 68.099 ;
     RECT  70.752 67.907 73.512 68.099 ;
     RECT  27.888 67.669 30.648 68.101 ;
     RECT  68.64 67.907 68.952 68.147 ;
     RECT  71.04 68.099 73.512 68.147 ;
     RECT  44.928 67.765 45.912 68.197 ;
     RECT  34.8 67.283 36.168 68.243 ;
     RECT  40.032 65.939 40.512 68.341 ;
     RECT  61.8 67.669 62.76 68.341 ;
     RECT  22.176 68.341 22.2 68.581 ;
     RECT  43.776 67.285 43.8 68.627 ;
     RECT  49.056 67.813 49.56 68.627 ;
     RECT  56.4 65.989 58.68 68.675 ;
     RECT  49.056 68.627 49.08 68.723 ;
     RECT  56.4 68.675 58.152 68.869 ;
     RECT  43.68 68.725 43.704 68.915 ;
     RECT  23.424 66.901 24.408 68.917 ;
     RECT  71.52 68.147 73.512 68.917 ;
     RECT  74.496 64.355 74.52 68.917 ;
     RECT  12.24 67.669 13.944 68.963 ;
     RECT  71.52 68.917 74.52 68.963 ;
     RECT  23.328 68.917 24.408 68.965 ;
     RECT  51 67.859 52.152 68.965 ;
     RECT  67.2 63.491 67.512 68.965 ;
     RECT  21.792 68.581 22.2 69.155 ;
     RECT  27.84 68.101 30.648 69.155 ;
     RECT  50.736 68.965 52.152 69.157 ;
     RECT  53.472 67.859 53.496 69.157 ;
     RECT  64.464 66.325 64.488 69.253 ;
     RECT  64.464 69.253 64.584 69.299 ;
     RECT  56.304 68.869 58.152 69.301 ;
     RECT  12.672 68.963 13.944 69.349 ;
     RECT  10.608 68.821 10.632 69.397 ;
     RECT  34.8 68.243 35.112 69.445 ;
     RECT  12.672 69.349 14.328 69.493 ;
     RECT  18.6 67.331 18.912 69.493 ;
     RECT  34.176 69.445 35.112 69.493 ;
     RECT  50.736 69.157 53.496 69.493 ;
     RECT  56.256 69.301 58.152 69.493 ;
     RECT  61.536 68.341 62.76 69.493 ;
     RECT  74.448 68.963 74.52 69.493 ;
     RECT  75.648 68.917 75.672 69.493 ;
     RECT  77.04 62.677 78.696 69.493 ;
     RECT  74.448 69.493 75.672 69.587 ;
     RECT  7.008 67.765 8.112 69.827 ;
     RECT  77.04 69.493 78.744 69.827 ;
     RECT  16.272 66.371 16.296 69.829 ;
     RECT  60.288 69.493 62.76 69.829 ;
     RECT  74.496 69.587 75.672 69.875 ;
     RECT  56.112 69.493 58.152 69.877 ;
     RECT  16.272 69.829 16.776 69.973 ;
     RECT  18.48 69.493 18.912 69.973 ;
     RECT  12.672 69.493 15.096 70.067 ;
     RECT  64.56 69.299 64.584 70.067 ;
     RECT  27.84 69.155 28.392 70.069 ;
     RECT  32.448 69.589 32.472 70.069 ;
     RECT  44.928 68.197 46.728 70.069 ;
     RECT  60.288 69.829 63.24 70.115 ;
     RECT  32.4 70.069 32.472 70.117 ;
     RECT  39.936 68.341 40.512 70.117 ;
     RECT  23.328 68.965 24.6 70.213 ;
     RECT  25.584 68.293 25.608 70.213 ;
     RECT  23.328 70.213 25.608 70.259 ;
     RECT  44.208 70.069 46.728 70.259 ;
     RECT  65.568 69.493 65.592 70.259 ;
     RECT  50.736 69.493 53.544 70.307 ;
     RECT  15.072 70.067 15.096 70.403 ;
     RECT  33.888 69.493 35.112 70.453 ;
     RECT  36.144 68.243 36.168 70.453 ;
     RECT  27.024 70.069 28.392 70.501 ;
     RECT  29.4 69.155 30.648 70.501 ;
     RECT  32.4 70.117 32.664 70.547 ;
     RECT  74.496 69.875 75.48 70.547 ;
     RECT  45.6 70.259 46.728 70.549 ;
     RECT  51 70.307 53.544 70.549 ;
     RECT  12.672 70.067 13.944 70.595 ;
     RECT  33.648 70.453 36.168 70.595 ;
     RECT  60.288 70.115 62.112 70.643 ;
     RECT  2.4 66.661 3.672 70.645 ;
     RECT  4.8 67.765 4.824 70.645 ;
     RECT  22.176 69.155 22.2 70.645 ;
     RECT  61.152 70.643 62.112 70.691 ;
     RECT  2.4 70.645 4.824 70.739 ;
     RECT  37.872 69.685 37.896 70.739 ;
     RECT  55.824 69.877 58.152 70.739 ;
     RECT  16.272 69.973 18.912 70.787 ;
     RECT  22.176 70.645 22.248 70.787 ;
     RECT  33.648 70.595 35.112 70.787 ;
     RECT  10.608 69.397 11.4 70.835 ;
     RECT  27.024 70.501 30.648 70.835 ;
     RECT  51 70.549 53.784 70.835 ;
     RECT  22.224 70.787 22.248 70.885 ;
     RECT  23.328 70.259 25.08 70.885 ;
     RECT  44.208 70.259 44.232 71.075 ;
     RECT  22.224 70.885 25.08 71.123 ;
     RECT  77.136 69.827 78.744 71.221 ;
     RECT  7.44 69.827 8.112 71.267 ;
     RECT  16.272 70.787 17.064 71.267 ;
     RECT  45.6 70.549 47.496 71.267 ;
     RECT  45.6 71.267 46.728 71.269 ;
     RECT  3.936 70.739 4.824 71.315 ;
     RECT  27.84 70.835 30.648 71.315 ;
     RECT  56.112 70.739 58.152 71.315 ;
     RECT  23.808 71.123 25.08 71.363 ;
     RECT  51 70.835 53.64 71.363 ;
     RECT  71.52 68.963 72.912 71.363 ;
     RECT  27.84 71.315 28.392 71.411 ;
     RECT  45.024 71.269 46.728 71.411 ;
     RECT  76.992 71.221 78.744 71.413 ;
     RECT  29.4 71.315 30.648 71.507 ;
     RECT  74.496 70.547 75.096 71.605 ;
     RECT  71.52 71.363 71.544 71.651 ;
     RECT  74.256 71.605 75.096 71.653 ;
     RECT  67.2 68.965 67.656 71.747 ;
     RECT  12.72 70.595 13.944 71.843 ;
     RECT  39.36 70.117 40.512 71.843 ;
     RECT  42.144 70.645 42.168 71.843 ;
     RECT  68.64 68.147 68.664 71.843 ;
     RECT  22.224 71.123 22.248 71.891 ;
     RECT  63.216 70.115 63.24 71.939 ;
     RECT  32.4 70.547 32.472 71.941 ;
     RECT  33.648 70.787 33.672 71.941 ;
     RECT  32.4 71.941 33.672 71.987 ;
     RECT  36.144 70.595 36.168 71.987 ;
     RECT  11.376 70.835 11.4 72.131 ;
     RECT  32.832 71.987 33.672 72.131 ;
     RECT  3.936 71.315 3.96 72.419 ;
     RECT  16.272 71.267 16.296 72.419 ;
     RECT  28.08 71.411 28.392 72.419 ;
     RECT  48.48 70.933 48.504 72.419 ;
     RECT  18.24 70.787 18.912 72.421 ;
     RECT  12.768 71.843 13.944 72.467 ;
     RECT  18.24 72.421 19.896 72.467 ;
     RECT  23.808 71.363 24.312 72.467 ;
     RECT  61.488 70.691 62.112 72.467 ;
     RECT  51 71.363 53.544 72.659 ;
     RECT  7.8 71.267 8.112 72.901 ;
     RECT  12.768 72.467 13.704 72.901 ;
     RECT  72.6 71.363 72.912 72.901 ;
     RECT  74.256 71.653 75.24 72.901 ;
     RECT  45.6 71.411 46.728 72.947 ;
     RECT  64.368 71.701 64.392 72.947 ;
     RECT  42.048 72.133 42.072 72.995 ;
     RECT  72.6 72.901 75.24 72.995 ;
     RECT  34.8 70.787 35.112 72.997 ;
     RECT  76.992 71.413 78.792 73.043 ;
     RECT  51 72.659 53.208 73.333 ;
     RECT  40.032 71.843 40.512 73.381 ;
     RECT  56.4 71.315 58.152 73.571 ;
     RECT  56.4 73.571 57.576 73.619 ;
     RECT  56.4 73.619 57.192 73.763 ;
     RECT  72.6 72.995 74.52 73.811 ;
     RECT  12.672 72.901 13.704 73.907 ;
     RECT  18.6 72.467 19.896 74.003 ;
     RECT  74.496 73.811 74.52 74.005 ;
     RECT  6.816 72.901 8.112 74.099 ;
     RECT  12.672 73.907 13.656 74.099 ;
     RECT  45.6 72.947 46.104 74.101 ;
     RECT  13.2 74.099 13.656 74.147 ;
     RECT  15.36 73.477 15.384 74.147 ;
     RECT  28.368 72.419 28.392 74.147 ;
     RECT  32.832 72.131 32.856 74.147 ;
     RECT  39.888 73.381 40.512 74.147 ;
     RECT  74.496 74.005 75.24 74.147 ;
     RECT  22.032 72.853 22.056 74.339 ;
     RECT  34.8 72.997 35.784 74.579 ;
     RECT  49.68 73.525 49.704 74.579 ;
     RECT  45.6 74.101 46.776 74.627 ;
     RECT  29.4 71.507 29.712 74.629 ;
     RECT  75.216 74.147 75.24 74.723 ;
     RECT  7.8 74.099 8.112 75.253 ;
     RECT  13.2 74.147 13.512 75.253 ;
     RECT  24 72.467 24.312 75.253 ;
     RECT  29.4 74.629 30.216 75.253 ;
     RECT  40.032 74.147 40.512 75.253 ;
     RECT  45.6 74.627 45.912 75.253 ;
     RECT  50.88 73.333 53.208 75.253 ;
     RECT  56.4 73.763 56.952 75.253 ;
     RECT  67.2 71.747 67.512 75.253 ;
     RECT  64.416 74.629 64.44 75.299 ;
     RECT  38.592 75.253 41.16 75.301 ;
     RECT  26.496 75.253 26.52 75.349 ;
     RECT  71.424 75.253 71.448 75.397 ;
     RECT  50.88 75.253 60.264 75.541 ;
     RECT  70.464 75.397 71.448 75.541 ;
     RECT  2.4 70.739 2.712 75.609 ;
     RECT  18.6 74.003 18.912 75.609 ;
     RECT  34.8 74.579 35.112 75.609 ;
     RECT  44.16 75.253 45.912 75.609 ;
     RECT  50.88 75.541 60.504 75.609 ;
     RECT  61.8 72.467 62.112 75.609 ;
     RECT  2.4 75.609 2.52 75.623 ;
     RECT  7.8 75.253 13.944 75.623 ;
     RECT  18.6 75.609 18.72 75.623 ;
     RECT  34.8 75.609 34.92 75.623 ;
     RECT  44.16 75.609 45.72 75.623 ;
     RECT  50.88 75.609 51.12 75.623 ;
     RECT  61.8 75.609 61.92 75.623 ;
     RECT  67.2 75.253 68.856 75.623 ;
     RECT  26.496 75.349 26.712 75.685 ;
     RECT  70.224 75.541 71.448 75.685 ;
     RECT  72.6 73.811 72.912 75.685 ;
     RECT  23.664 75.253 24.408 75.733 ;
     RECT  25.536 75.685 26.712 75.733 ;
     RECT  44.16 75.623 45.576 75.733 ;
     RECT  68.16 75.623 68.856 75.733 ;
     RECT  70.224 75.685 73.272 75.733 ;
     RECT  8.544 75.623 13.944 75.781 ;
     RECT  15.312 75.253 15.576 75.781 ;
     RECT  23.664 75.733 26.712 75.781 ;
     RECT  27.888 75.253 30.696 75.781 ;
     RECT  38.592 75.301 41.4 75.781 ;
     RECT  42.768 75.733 45.576 75.781 ;
     RECT  68.16 75.733 73.272 75.781 ;
     RECT  74.448 75.253 74.712 75.781 ;
     RECT  76.992 73.043 78.744 76.403 ;
     RECT  23.664 75.781 30.696 76.885 ;
     RECT  50.88 75.623 50.904 76.979 ;
     RECT  76.992 76.403 78.408 76.979 ;
     RECT  52.272 75.609 60.504 77.699 ;
     RECT  77.472 76.979 78.408 77.699 ;
     RECT  79.776 70.069 79.8 77.699 ;
     RECT  8.544 75.781 15.816 77.712 ;
     RECT  23.472 76.885 30.696 77.712 ;
     RECT  38.352 75.781 45.576 77.712 ;
     RECT  53.232 77.699 60.504 77.712 ;
     RECT  68.16 75.781 75.384 77.712 ;
  END
END ot_hgi_coll_fj_q2_r128
END LIBRARY
